VERSION 5.8 ;
BUSBITCHARS "[]" ;
DIVIDERCHAR "/" ;
UNITS
    DATABASE MICRONS 1000 ;
END UNITS

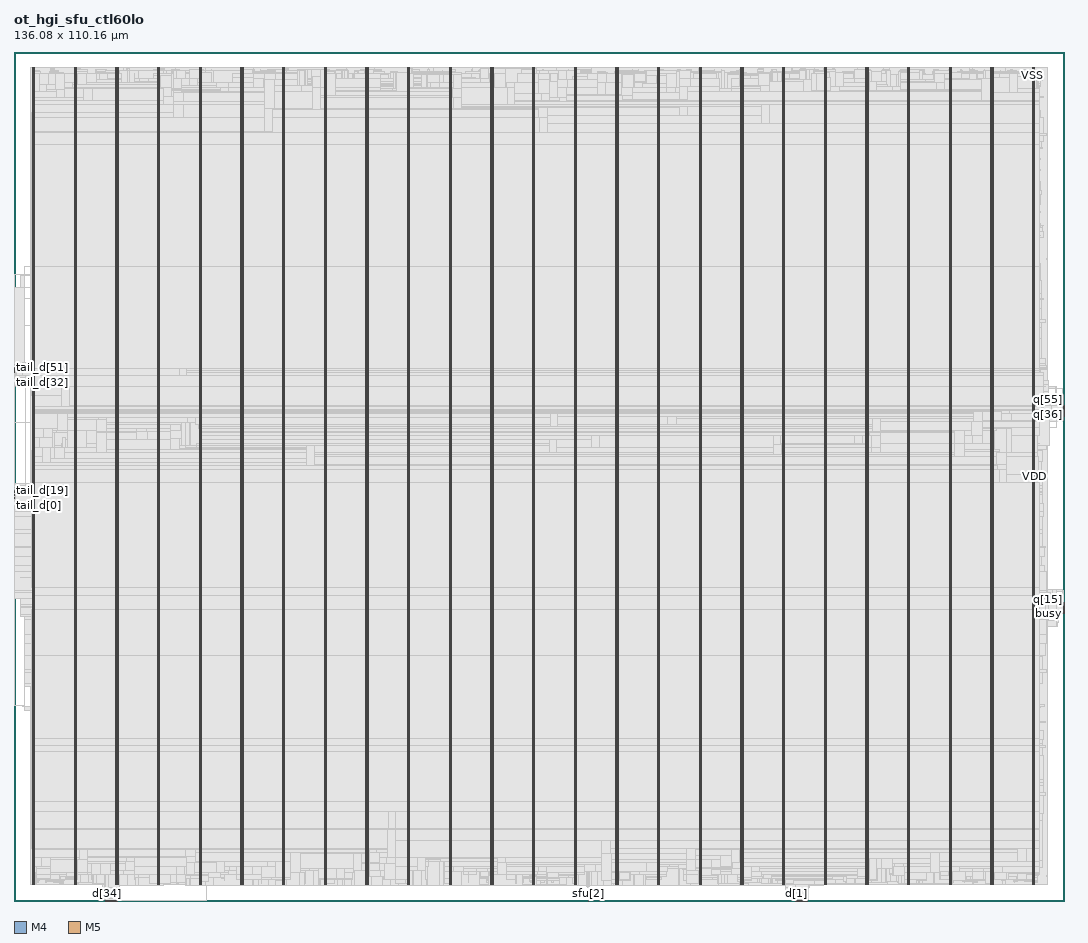
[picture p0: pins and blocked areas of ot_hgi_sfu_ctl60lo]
MACRO ot_hgi_sfu_ctl60lo
  FOREIGN ot_hgi_sfu_ctl60lo 0 0 ;
  CLASS BLOCK ;
  SIZE 136.08 BY 110.16 ;
  PIN busy
    DIRECTION OUTPUT ;
    USE SIGNAL ;
    PORT
      LAYER M4 ;
        RECT  135.996 37.2 136.08 37.224 ;
    END
  END busy
  PIN clk
    DIRECTION INPUT ;
    USE SIGNAL ;
    PORT
      LAYER M5 ;
        RECT  101.328 0 101.352 0.084 ;
    END
  END clk
  PIN coll
    DIRECTION OUTPUT ;
    USE SIGNAL ;
    PORT
      LAYER M4 ;
        RECT  135.996 37.248 136.08 37.272 ;
    END
  END coll
  PIN d[0]
    DIRECTION INPUT ;
    USE SIGNAL ;
    PORT
      LAYER M5 ;
        RECT  101.376 0 101.4 0.084 ;
    END
  END d[0]
  PIN d[10]
    DIRECTION INPUT ;
    USE SIGNAL ;
    PORT
      LAYER M5 ;
        RECT  101.856 0 101.88 0.084 ;
    END
  END d[10]
  PIN d[11]
    DIRECTION INPUT ;
    USE SIGNAL ;
    PORT
      LAYER M5 ;
        RECT  101.904 0 101.928 0.084 ;
    END
  END d[11]
  PIN d[12]
    DIRECTION INPUT ;
    USE SIGNAL ;
    PORT
      LAYER M5 ;
        RECT  101.952 0 101.976 0.084 ;
    END
  END d[12]
  PIN d[13]
    DIRECTION INPUT ;
    USE SIGNAL ;
    PORT
      LAYER M5 ;
        RECT  102 0 102.024 0.084 ;
    END
  END d[13]
  PIN d[14]
    DIRECTION INPUT ;
    USE SIGNAL ;
    PORT
      LAYER M5 ;
        RECT  102.048 0 102.072 0.084 ;
    END
  END d[14]
  PIN d[15]
    DIRECTION INPUT ;
    USE SIGNAL ;
    PORT
      LAYER M5 ;
        RECT  102.096 0 102.12 0.084 ;
    END
  END d[15]
  PIN d[16]
    DIRECTION INPUT ;
    USE SIGNAL ;
    PORT
      LAYER M5 ;
        RECT  102.144 0 102.168 0.084 ;
    END
  END d[16]
  PIN d[17]
    DIRECTION INPUT ;
    USE SIGNAL ;
    PORT
      LAYER M5 ;
        RECT  102.192 0 102.216 0.084 ;
    END
  END d[17]
  PIN d[18]
    DIRECTION INPUT ;
    USE SIGNAL ;
    PORT
      LAYER M5 ;
        RECT  102.24 0 102.264 0.084 ;
    END
  END d[18]
  PIN d[19]
    DIRECTION INPUT ;
    USE SIGNAL ;
    PORT
      LAYER M5 ;
        RECT  102.288 0 102.312 0.084 ;
    END
  END d[19]
  PIN d[1]
    DIRECTION INPUT ;
    USE SIGNAL ;
    PORT
      LAYER M5 ;
        RECT  101.424 0 101.448 0.084 ;
    END
  END d[1]
  PIN d[20]
    DIRECTION INPUT ;
    USE SIGNAL ;
    PORT
      LAYER M5 ;
        RECT  102.336 0 102.36 0.084 ;
    END
  END d[20]
  PIN d[21]
    DIRECTION INPUT ;
    USE SIGNAL ;
    PORT
      LAYER M5 ;
        RECT  102.384 0 102.408 0.084 ;
    END
  END d[21]
  PIN d[22]
    DIRECTION INPUT ;
    USE SIGNAL ;
    PORT
      LAYER M5 ;
        RECT  102.432 0 102.456 0.084 ;
    END
  END d[22]
  PIN d[23]
    DIRECTION INPUT ;
    USE SIGNAL ;
    PORT
      LAYER M5 ;
        RECT  102.48 0 102.504 0.084 ;
    END
  END d[23]
  PIN d[24]
    DIRECTION INPUT ;
    USE SIGNAL ;
    PORT
      LAYER M5 ;
        RECT  102.528 0 102.552 0.084 ;
    END
  END d[24]
  PIN d[25]
    DIRECTION INPUT ;
    USE SIGNAL ;
    PORT
      LAYER M5 ;
        RECT  102.576 0 102.6 0.084 ;
    END
  END d[25]
  PIN d[26]
    DIRECTION INPUT ;
    USE SIGNAL ;
    PORT
      LAYER M5 ;
        RECT  102.624 0 102.648 0.084 ;
    END
  END d[26]
  PIN d[27]
    DIRECTION INPUT ;
    USE SIGNAL ;
    PORT
      LAYER M5 ;
        RECT  102.672 0 102.696 0.084 ;
    END
  END d[27]
  PIN d[28]
    DIRECTION INPUT ;
    USE SIGNAL ;
    PORT
      LAYER M5 ;
        RECT  102.72 0 102.744 0.084 ;
    END
  END d[28]
  PIN d[29]
    DIRECTION INPUT ;
    USE SIGNAL ;
    PORT
      LAYER M5 ;
        RECT  102.768 0 102.792 0.084 ;
    END
  END d[29]
  PIN d[2]
    DIRECTION INPUT ;
    USE SIGNAL ;
    PORT
      LAYER M5 ;
        RECT  101.472 0 101.496 0.084 ;
    END
  END d[2]
  PIN d[30]
    DIRECTION INPUT ;
    USE SIGNAL ;
    PORT
      LAYER M5 ;
        RECT  102.816 0 102.84 0.084 ;
    END
  END d[30]
  PIN d[31]
    DIRECTION INPUT ;
    USE SIGNAL ;
    PORT
      LAYER M5 ;
        RECT  11.856 0 11.88 0.084 ;
    END
  END d[31]
  PIN d[32]
    DIRECTION INPUT ;
    USE SIGNAL ;
    PORT
      LAYER M5 ;
        RECT  11.904 0 11.928 0.084 ;
    END
  END d[32]
  PIN d[33]
    DIRECTION INPUT ;
    USE SIGNAL ;
    PORT
      LAYER M5 ;
        RECT  11.952 0 11.976 0.084 ;
    END
  END d[33]
  PIN d[34]
    DIRECTION INPUT ;
    USE SIGNAL ;
    PORT
      LAYER M5 ;
        RECT  12 0 12.024 0.084 ;
    END
  END d[34]
  PIN d[35]
    DIRECTION INPUT ;
    USE SIGNAL ;
    PORT
      LAYER M5 ;
        RECT  12.048 0 12.072 0.084 ;
    END
  END d[35]
  PIN d[36]
    DIRECTION INPUT ;
    USE SIGNAL ;
    PORT
      LAYER M5 ;
        RECT  12.096 0 12.12 0.084 ;
    END
  END d[36]
  PIN d[37]
    DIRECTION INPUT ;
    USE SIGNAL ;
    PORT
      LAYER M5 ;
        RECT  12.144 0 12.168 0.084 ;
    END
  END d[37]
  PIN d[38]
    DIRECTION INPUT ;
    USE SIGNAL ;
    PORT
      LAYER M5 ;
        RECT  12.192 0 12.216 0.084 ;
    END
  END d[38]
  PIN d[39]
    DIRECTION INPUT ;
    USE SIGNAL ;
    PORT
      LAYER M5 ;
        RECT  12.24 0 12.264 0.084 ;
    END
  END d[39]
  PIN d[3]
    DIRECTION INPUT ;
    USE SIGNAL ;
    PORT
      LAYER M5 ;
        RECT  101.52 0 101.544 0.084 ;
    END
  END d[3]
  PIN d[40]
    DIRECTION INPUT ;
    USE SIGNAL ;
    PORT
      LAYER M5 ;
        RECT  12.288 0 12.312 0.084 ;
    END
  END d[40]
  PIN d[41]
    DIRECTION INPUT ;
    USE SIGNAL ;
    PORT
      LAYER M5 ;
        RECT  12.336 0 12.36 0.084 ;
    END
  END d[41]
  PIN d[42]
    DIRECTION INPUT ;
    USE SIGNAL ;
    PORT
      LAYER M5 ;
        RECT  12.384 0 12.408 0.084 ;
    END
  END d[42]
  PIN d[43]
    DIRECTION INPUT ;
    USE SIGNAL ;
    PORT
      LAYER M5 ;
        RECT  12.432 0 12.456 0.084 ;
    END
  END d[43]
  PIN d[44]
    DIRECTION INPUT ;
    USE SIGNAL ;
    PORT
      LAYER M5 ;
        RECT  12.48 0 12.504 0.084 ;
    END
  END d[44]
  PIN d[45]
    DIRECTION INPUT ;
    USE SIGNAL ;
    PORT
      LAYER M5 ;
        RECT  12.528 0 12.552 0.084 ;
    END
  END d[45]
  PIN d[46]
    DIRECTION INPUT ;
    USE SIGNAL ;
    PORT
      LAYER M5 ;
        RECT  12.576 0 12.6 0.084 ;
    END
  END d[46]
  PIN d[47]
    DIRECTION INPUT ;
    USE SIGNAL ;
    PORT
      LAYER M5 ;
        RECT  12.624 0 12.648 0.084 ;
    END
  END d[47]
  PIN d[48]
    DIRECTION INPUT ;
    USE SIGNAL ;
    PORT
      LAYER M5 ;
        RECT  12.672 0 12.696 0.084 ;
    END
  END d[48]
  PIN d[49]
    DIRECTION INPUT ;
    USE SIGNAL ;
    PORT
      LAYER M5 ;
        RECT  12.72 0 12.744 0.084 ;
    END
  END d[49]
  PIN d[4]
    DIRECTION INPUT ;
    USE SIGNAL ;
    PORT
      LAYER M5 ;
        RECT  101.568 0 101.592 0.084 ;
    END
  END d[4]
  PIN d[50]
    DIRECTION INPUT ;
    USE SIGNAL ;
    PORT
      LAYER M5 ;
        RECT  12.768 0 12.792 0.084 ;
    END
  END d[50]
  PIN d[51]
    DIRECTION INPUT ;
    USE SIGNAL ;
    PORT
      LAYER M5 ;
        RECT  12.816 0 12.84 0.084 ;
    END
  END d[51]
  PIN d[52]
    DIRECTION INPUT ;
    USE SIGNAL ;
    PORT
      LAYER M5 ;
        RECT  12.864 0 12.888 0.084 ;
    END
  END d[52]
  PIN d[53]
    DIRECTION INPUT ;
    USE SIGNAL ;
    PORT
      LAYER M5 ;
        RECT  12.912 0 12.936 0.084 ;
    END
  END d[53]
  PIN d[54]
    DIRECTION INPUT ;
    USE SIGNAL ;
    PORT
      LAYER M5 ;
        RECT  12.96 0 12.984 0.084 ;
    END
  END d[54]
  PIN d[55]
    DIRECTION INPUT ;
    USE SIGNAL ;
    PORT
      LAYER M5 ;
        RECT  13.008 0 13.032 0.084 ;
    END
  END d[55]
  PIN d[56]
    DIRECTION INPUT ;
    USE SIGNAL ;
    PORT
      LAYER M5 ;
        RECT  13.056 0 13.08 0.084 ;
    END
  END d[56]
  PIN d[57]
    DIRECTION INPUT ;
    USE SIGNAL ;
    PORT
      LAYER M5 ;
        RECT  13.104 0 13.128 0.084 ;
    END
  END d[57]
  PIN d[58]
    DIRECTION INPUT ;
    USE SIGNAL ;
    PORT
      LAYER M5 ;
        RECT  13.152 0 13.176 0.084 ;
    END
  END d[58]
  PIN d[59]
    DIRECTION INPUT ;
    USE SIGNAL ;
    PORT
      LAYER M5 ;
        RECT  13.2 0 13.224 0.084 ;
    END
  END d[59]
  PIN d[5]
    DIRECTION INPUT ;
    USE SIGNAL ;
    PORT
      LAYER M5 ;
        RECT  101.616 0 101.64 0.084 ;
    END
  END d[5]
  PIN d[6]
    DIRECTION INPUT ;
    USE SIGNAL ;
    PORT
      LAYER M5 ;
        RECT  101.664 0 101.688 0.084 ;
    END
  END d[6]
  PIN d[7]
    DIRECTION INPUT ;
    USE SIGNAL ;
    PORT
      LAYER M5 ;
        RECT  101.712 0 101.736 0.084 ;
    END
  END d[7]
  PIN d[8]
    DIRECTION INPUT ;
    USE SIGNAL ;
    PORT
      LAYER M5 ;
        RECT  101.76 0 101.784 0.084 ;
    END
  END d[8]
  PIN d[9]
    DIRECTION INPUT ;
    USE SIGNAL ;
    PORT
      LAYER M5 ;
        RECT  101.808 0 101.832 0.084 ;
    END
  END d[9]
  PIN q[0]
    DIRECTION OUTPUT ;
    USE SIGNAL ;
    PORT
      LAYER M4 ;
        RECT  135.996 37.296 136.08 37.32 ;
    END
  END q[0]
  PIN q[10]
    DIRECTION OUTPUT ;
    USE SIGNAL ;
    PORT
      LAYER M4 ;
        RECT  135.996 37.776 136.08 37.8 ;
    END
  END q[10]
  PIN q[11]
    DIRECTION OUTPUT ;
    USE SIGNAL ;
    PORT
      LAYER M4 ;
        RECT  135.996 37.824 136.08 37.848 ;
    END
  END q[11]
  PIN q[12]
    DIRECTION OUTPUT ;
    USE SIGNAL ;
    PORT
      LAYER M4 ;
        RECT  135.996 37.872 136.08 37.896 ;
    END
  END q[12]
  PIN q[13]
    DIRECTION OUTPUT ;
    USE SIGNAL ;
    PORT
      LAYER M4 ;
        RECT  135.996 37.92 136.08 37.944 ;
    END
  END q[13]
  PIN q[14]
    DIRECTION OUTPUT ;
    USE SIGNAL ;
    PORT
      LAYER M4 ;
        RECT  135.996 37.968 136.08 37.992 ;
    END
  END q[14]
  PIN q[15]
    DIRECTION OUTPUT ;
    USE SIGNAL ;
    PORT
      LAYER M4 ;
        RECT  135.996 38.016 136.08 38.04 ;
    END
  END q[15]
  PIN q[16]
    DIRECTION OUTPUT ;
    USE SIGNAL ;
    PORT
      LAYER M4 ;
        RECT  135.996 38.064 136.08 38.088 ;
    END
  END q[16]
  PIN q[17]
    DIRECTION OUTPUT ;
    USE SIGNAL ;
    PORT
      LAYER M4 ;
        RECT  135.996 38.112 136.08 38.136 ;
    END
  END q[17]
  PIN q[18]
    DIRECTION OUTPUT ;
    USE SIGNAL ;
    PORT
      LAYER M4 ;
        RECT  135.996 38.16 136.08 38.184 ;
    END
  END q[18]
  PIN q[19]
    DIRECTION OUTPUT ;
    USE SIGNAL ;
    PORT
      LAYER M4 ;
        RECT  135.996 38.208 136.08 38.232 ;
    END
  END q[19]
  PIN q[1]
    DIRECTION OUTPUT ;
    USE SIGNAL ;
    PORT
      LAYER M4 ;
        RECT  135.996 37.344 136.08 37.368 ;
    END
  END q[1]
  PIN q[20]
    DIRECTION OUTPUT ;
    USE SIGNAL ;
    PORT
      LAYER M4 ;
        RECT  135.996 38.256 136.08 38.28 ;
    END
  END q[20]
  PIN q[21]
    DIRECTION OUTPUT ;
    USE SIGNAL ;
    PORT
      LAYER M4 ;
        RECT  135.996 38.304 136.08 38.328 ;
    END
  END q[21]
  PIN q[22]
    DIRECTION OUTPUT ;
    USE SIGNAL ;
    PORT
      LAYER M4 ;
        RECT  135.996 38.352 136.08 38.376 ;
    END
  END q[22]
  PIN q[23]
    DIRECTION OUTPUT ;
    USE SIGNAL ;
    PORT
      LAYER M4 ;
        RECT  135.996 38.4 136.08 38.424 ;
    END
  END q[23]
  PIN q[24]
    DIRECTION OUTPUT ;
    USE SIGNAL ;
    PORT
      LAYER M4 ;
        RECT  135.996 38.448 136.08 38.472 ;
    END
  END q[24]
  PIN q[25]
    DIRECTION OUTPUT ;
    USE SIGNAL ;
    PORT
      LAYER M4 ;
        RECT  135.996 38.496 136.08 38.52 ;
    END
  END q[25]
  PIN q[26]
    DIRECTION OUTPUT ;
    USE SIGNAL ;
    PORT
      LAYER M4 ;
        RECT  135.996 38.544 136.08 38.568 ;
    END
  END q[26]
  PIN q[27]
    DIRECTION OUTPUT ;
    USE SIGNAL ;
    PORT
      LAYER M4 ;
        RECT  135.996 38.592 136.08 38.616 ;
    END
  END q[27]
  PIN q[28]
    DIRECTION OUTPUT ;
    USE SIGNAL ;
    PORT
      LAYER M4 ;
        RECT  135.996 38.64 136.08 38.664 ;
    END
  END q[28]
  PIN q[29]
    DIRECTION OUTPUT ;
    USE SIGNAL ;
    PORT
      LAYER M4 ;
        RECT  135.996 38.688 136.08 38.712 ;
    END
  END q[29]
  PIN q[2]
    DIRECTION OUTPUT ;
    USE SIGNAL ;
    PORT
      LAYER M4 ;
        RECT  135.996 37.392 136.08 37.416 ;
    END
  END q[2]
  PIN q[30]
    DIRECTION OUTPUT ;
    USE SIGNAL ;
    PORT
      LAYER M4 ;
        RECT  135.996 62.784 136.08 62.808 ;
    END
  END q[30]
  PIN q[31]
    DIRECTION OUTPUT ;
    USE SIGNAL ;
    PORT
      LAYER M4 ;
        RECT  135.996 62.832 136.08 62.856 ;
    END
  END q[31]
  PIN q[32]
    DIRECTION OUTPUT ;
    USE SIGNAL ;
    PORT
      LAYER M4 ;
        RECT  135.996 62.88 136.08 62.904 ;
    END
  END q[32]
  PIN q[33]
    DIRECTION OUTPUT ;
    USE SIGNAL ;
    PORT
      LAYER M4 ;
        RECT  135.996 62.928 136.08 62.952 ;
    END
  END q[33]
  PIN q[34]
    DIRECTION OUTPUT ;
    USE SIGNAL ;
    PORT
      LAYER M4 ;
        RECT  135.996 62.976 136.08 63 ;
    END
  END q[34]
  PIN q[35]
    DIRECTION OUTPUT ;
    USE SIGNAL ;
    PORT
      LAYER M4 ;
        RECT  135.996 63.024 136.08 63.048 ;
    END
  END q[35]
  PIN q[36]
    DIRECTION OUTPUT ;
    USE SIGNAL ;
    PORT
      LAYER M4 ;
        RECT  135.996 63.072 136.08 63.096 ;
    END
  END q[36]
  PIN q[37]
    DIRECTION OUTPUT ;
    USE SIGNAL ;
    PORT
      LAYER M4 ;
        RECT  135.996 63.12 136.08 63.144 ;
    END
  END q[37]
  PIN q[38]
    DIRECTION OUTPUT ;
    USE SIGNAL ;
    PORT
      LAYER M4 ;
        RECT  135.996 63.168 136.08 63.192 ;
    END
  END q[38]
  PIN q[39]
    DIRECTION OUTPUT ;
    USE SIGNAL ;
    PORT
      LAYER M4 ;
        RECT  135.996 63.216 136.08 63.24 ;
    END
  END q[39]
  PIN q[3]
    DIRECTION OUTPUT ;
    USE SIGNAL ;
    PORT
      LAYER M4 ;
        RECT  135.996 37.44 136.08 37.464 ;
    END
  END q[3]
  PIN q[40]
    DIRECTION OUTPUT ;
    USE SIGNAL ;
    PORT
      LAYER M4 ;
        RECT  135.996 63.264 136.08 63.288 ;
    END
  END q[40]
  PIN q[41]
    DIRECTION OUTPUT ;
    USE SIGNAL ;
    PORT
      LAYER M4 ;
        RECT  135.996 63.312 136.08 63.336 ;
    END
  END q[41]
  PIN q[42]
    DIRECTION OUTPUT ;
    USE SIGNAL ;
    PORT
      LAYER M4 ;
        RECT  135.996 63.36 136.08 63.384 ;
    END
  END q[42]
  PIN q[43]
    DIRECTION OUTPUT ;
    USE SIGNAL ;
    PORT
      LAYER M4 ;
        RECT  135.996 63.408 136.08 63.432 ;
    END
  END q[43]
  PIN q[44]
    DIRECTION OUTPUT ;
    USE SIGNAL ;
    PORT
      LAYER M4 ;
        RECT  135.996 63.456 136.08 63.48 ;
    END
  END q[44]
  PIN q[45]
    DIRECTION OUTPUT ;
    USE SIGNAL ;
    PORT
      LAYER M4 ;
        RECT  135.996 63.504 136.08 63.528 ;
    END
  END q[45]
  PIN q[46]
    DIRECTION OUTPUT ;
    USE SIGNAL ;
    PORT
      LAYER M4 ;
        RECT  135.996 63.552 136.08 63.576 ;
    END
  END q[46]
  PIN q[47]
    DIRECTION OUTPUT ;
    USE SIGNAL ;
    PORT
      LAYER M4 ;
        RECT  135.996 63.6 136.08 63.624 ;
    END
  END q[47]
  PIN q[48]
    DIRECTION OUTPUT ;
    USE SIGNAL ;
    PORT
      LAYER M4 ;
        RECT  135.996 63.648 136.08 63.672 ;
    END
  END q[48]
  PIN q[49]
    DIRECTION OUTPUT ;
    USE SIGNAL ;
    PORT
      LAYER M4 ;
        RECT  135.996 63.696 136.08 63.72 ;
    END
  END q[49]
  PIN q[4]
    DIRECTION OUTPUT ;
    USE SIGNAL ;
    PORT
      LAYER M4 ;
        RECT  135.996 37.488 136.08 37.512 ;
    END
  END q[4]
  PIN q[50]
    DIRECTION OUTPUT ;
    USE SIGNAL ;
    PORT
      LAYER M4 ;
        RECT  135.996 63.744 136.08 63.768 ;
    END
  END q[50]
  PIN q[51]
    DIRECTION OUTPUT ;
    USE SIGNAL ;
    PORT
      LAYER M4 ;
        RECT  135.996 63.792 136.08 63.816 ;
    END
  END q[51]
  PIN q[52]
    DIRECTION OUTPUT ;
    USE SIGNAL ;
    PORT
      LAYER M4 ;
        RECT  135.996 63.84 136.08 63.864 ;
    END
  END q[52]
  PIN q[53]
    DIRECTION OUTPUT ;
    USE SIGNAL ;
    PORT
      LAYER M4 ;
        RECT  135.996 63.888 136.08 63.912 ;
    END
  END q[53]
  PIN q[54]
    DIRECTION OUTPUT ;
    USE SIGNAL ;
    PORT
      LAYER M4 ;
        RECT  135.996 63.936 136.08 63.96 ;
    END
  END q[54]
  PIN q[55]
    DIRECTION OUTPUT ;
    USE SIGNAL ;
    PORT
      LAYER M4 ;
        RECT  135.996 63.984 136.08 64.008 ;
    END
  END q[55]
  PIN q[56]
    DIRECTION OUTPUT ;
    USE SIGNAL ;
    PORT
      LAYER M4 ;
        RECT  135.996 64.032 136.08 64.056 ;
    END
  END q[56]
  PIN q[57]
    DIRECTION OUTPUT ;
    USE SIGNAL ;
    PORT
      LAYER M4 ;
        RECT  135.996 64.08 136.08 64.104 ;
    END
  END q[57]
  PIN q[58]
    DIRECTION OUTPUT ;
    USE SIGNAL ;
    PORT
      LAYER M4 ;
        RECT  135.996 64.128 136.08 64.152 ;
    END
  END q[58]
  PIN q[59]
    DIRECTION OUTPUT ;
    USE SIGNAL ;
    PORT
      LAYER M4 ;
        RECT  135.996 64.176 136.08 64.2 ;
    END
  END q[59]
  PIN q[5]
    DIRECTION OUTPUT ;
    USE SIGNAL ;
    PORT
      LAYER M4 ;
        RECT  135.996 37.536 136.08 37.56 ;
    END
  END q[5]
  PIN q[6]
    DIRECTION OUTPUT ;
    USE SIGNAL ;
    PORT
      LAYER M4 ;
        RECT  135.996 37.584 136.08 37.608 ;
    END
  END q[6]
  PIN q[7]
    DIRECTION OUTPUT ;
    USE SIGNAL ;
    PORT
      LAYER M4 ;
        RECT  135.996 37.632 136.08 37.656 ;
    END
  END q[7]
  PIN q[8]
    DIRECTION OUTPUT ;
    USE SIGNAL ;
    PORT
      LAYER M4 ;
        RECT  135.996 37.68 136.08 37.704 ;
    END
  END q[8]
  PIN q[9]
    DIRECTION OUTPUT ;
    USE SIGNAL ;
    PORT
      LAYER M4 ;
        RECT  135.996 37.728 136.08 37.752 ;
    END
  END q[9]
  PIN rst_n
    DIRECTION INPUT ;
    USE SIGNAL ;
    PORT
      LAYER M5 ;
        RECT  13.248 0 13.272 0.084 ;
    END
  END rst_n
  PIN sfu[0]
    DIRECTION INPUT ;
    USE SIGNAL ;
    PORT
      LAYER M5 ;
        RECT  13.296 0 13.32 0.084 ;
    END
  END sfu[0]
  PIN sfu[1]
    DIRECTION INPUT ;
    USE SIGNAL ;
    PORT
      LAYER M5 ;
        RECT  13.344 0 13.368 0.084 ;
    END
  END sfu[1]
  PIN sfu[2]
    DIRECTION INPUT ;
    USE SIGNAL ;
    PORT
      LAYER M5 ;
        RECT  74.448 0 74.472 0.084 ;
    END
  END sfu[2]
  PIN tail_d[0]
    DIRECTION INPUT ;
    USE SIGNAL ;
    PORT
      LAYER M4 ;
        RECT  0 52.224 0.084 52.248 ;
    END
  END tail_d[0]
  PIN tail_d[10]
    DIRECTION INPUT ;
    USE SIGNAL ;
    PORT
      LAYER M4 ;
        RECT  0 52.704 0.084 52.728 ;
    END
  END tail_d[10]
  PIN tail_d[11]
    DIRECTION INPUT ;
    USE SIGNAL ;
    PORT
      LAYER M4 ;
        RECT  0 52.752 0.084 52.776 ;
    END
  END tail_d[11]
  PIN tail_d[12]
    DIRECTION INPUT ;
    USE SIGNAL ;
    PORT
      LAYER M4 ;
        RECT  0 52.8 0.084 52.824 ;
    END
  END tail_d[12]
  PIN tail_d[13]
    DIRECTION INPUT ;
    USE SIGNAL ;
    PORT
      LAYER M4 ;
        RECT  0 52.848 0.084 52.872 ;
    END
  END tail_d[13]
  PIN tail_d[14]
    DIRECTION INPUT ;
    USE SIGNAL ;
    PORT
      LAYER M4 ;
        RECT  0 52.896 0.084 52.92 ;
    END
  END tail_d[14]
  PIN tail_d[15]
    DIRECTION INPUT ;
    USE SIGNAL ;
    PORT
      LAYER M4 ;
        RECT  0 52.944 0.084 52.968 ;
    END
  END tail_d[15]
  PIN tail_d[16]
    DIRECTION INPUT ;
    USE SIGNAL ;
    PORT
      LAYER M4 ;
        RECT  0 52.992 0.084 53.016 ;
    END
  END tail_d[16]
  PIN tail_d[17]
    DIRECTION INPUT ;
    USE SIGNAL ;
    PORT
      LAYER M4 ;
        RECT  0 53.04 0.084 53.064 ;
    END
  END tail_d[17]
  PIN tail_d[18]
    DIRECTION INPUT ;
    USE SIGNAL ;
    PORT
      LAYER M4 ;
        RECT  0 53.088 0.084 53.112 ;
    END
  END tail_d[18]
  PIN tail_d[19]
    DIRECTION INPUT ;
    USE SIGNAL ;
    PORT
      LAYER M4 ;
        RECT  0 53.136 0.084 53.16 ;
    END
  END tail_d[19]
  PIN tail_d[1]
    DIRECTION INPUT ;
    USE SIGNAL ;
    PORT
      LAYER M4 ;
        RECT  0 52.272 0.084 52.296 ;
    END
  END tail_d[1]
  PIN tail_d[20]
    DIRECTION INPUT ;
    USE SIGNAL ;
    PORT
      LAYER M4 ;
        RECT  0 53.184 0.084 53.208 ;
    END
  END tail_d[20]
  PIN tail_d[21]
    DIRECTION INPUT ;
    USE SIGNAL ;
    PORT
      LAYER M4 ;
        RECT  0 53.232 0.084 53.256 ;
    END
  END tail_d[21]
  PIN tail_d[22]
    DIRECTION INPUT ;
    USE SIGNAL ;
    PORT
      LAYER M4 ;
        RECT  0 53.28 0.084 53.304 ;
    END
  END tail_d[22]
  PIN tail_d[23]
    DIRECTION INPUT ;
    USE SIGNAL ;
    PORT
      LAYER M4 ;
        RECT  0 53.328 0.084 53.352 ;
    END
  END tail_d[23]
  PIN tail_d[24]
    DIRECTION INPUT ;
    USE SIGNAL ;
    PORT
      LAYER M4 ;
        RECT  0 53.376 0.084 53.4 ;
    END
  END tail_d[24]
  PIN tail_d[25]
    DIRECTION INPUT ;
    USE SIGNAL ;
    PORT
      LAYER M4 ;
        RECT  0 53.424 0.084 53.448 ;
    END
  END tail_d[25]
  PIN tail_d[26]
    DIRECTION INPUT ;
    USE SIGNAL ;
    PORT
      LAYER M4 ;
        RECT  0 53.472 0.084 53.496 ;
    END
  END tail_d[26]
  PIN tail_d[27]
    DIRECTION INPUT ;
    USE SIGNAL ;
    PORT
      LAYER M4 ;
        RECT  0 53.52 0.084 53.544 ;
    END
  END tail_d[27]
  PIN tail_d[28]
    DIRECTION INPUT ;
    USE SIGNAL ;
    PORT
      LAYER M4 ;
        RECT  0 53.568 0.084 53.592 ;
    END
  END tail_d[28]
  PIN tail_d[29]
    DIRECTION INPUT ;
    USE SIGNAL ;
    PORT
      LAYER M4 ;
        RECT  0 53.616 0.084 53.64 ;
    END
  END tail_d[29]
  PIN tail_d[2]
    DIRECTION INPUT ;
    USE SIGNAL ;
    PORT
      LAYER M4 ;
        RECT  0 52.32 0.084 52.344 ;
    END
  END tail_d[2]
  PIN tail_d[30]
    DIRECTION INPUT ;
    USE SIGNAL ;
    PORT
      LAYER M4 ;
        RECT  0 53.664 0.084 53.688 ;
    END
  END tail_d[30]
  PIN tail_d[31]
    DIRECTION INPUT ;
    USE SIGNAL ;
    PORT
      LAYER M4 ;
        RECT  0 53.712 0.084 53.736 ;
    END
  END tail_d[31]
  PIN tail_d[32]
    DIRECTION INPUT ;
    USE SIGNAL ;
    PORT
      LAYER M4 ;
        RECT  0 68.256 0.084 68.28 ;
    END
  END tail_d[32]
  PIN tail_d[33]
    DIRECTION INPUT ;
    USE SIGNAL ;
    PORT
      LAYER M4 ;
        RECT  0 68.304 0.084 68.328 ;
    END
  END tail_d[33]
  PIN tail_d[34]
    DIRECTION INPUT ;
    USE SIGNAL ;
    PORT
      LAYER M4 ;
        RECT  0 68.352 0.084 68.376 ;
    END
  END tail_d[34]
  PIN tail_d[35]
    DIRECTION INPUT ;
    USE SIGNAL ;
    PORT
      LAYER M4 ;
        RECT  0 68.4 0.084 68.424 ;
    END
  END tail_d[35]
  PIN tail_d[36]
    DIRECTION INPUT ;
    USE SIGNAL ;
    PORT
      LAYER M4 ;
        RECT  0 68.448 0.084 68.472 ;
    END
  END tail_d[36]
  PIN tail_d[37]
    DIRECTION INPUT ;
    USE SIGNAL ;
    PORT
      LAYER M4 ;
        RECT  0 68.496 0.084 68.52 ;
    END
  END tail_d[37]
  PIN tail_d[38]
    DIRECTION INPUT ;
    USE SIGNAL ;
    PORT
      LAYER M4 ;
        RECT  0 68.544 0.084 68.568 ;
    END
  END tail_d[38]
  PIN tail_d[39]
    DIRECTION INPUT ;
    USE SIGNAL ;
    PORT
      LAYER M4 ;
        RECT  0 68.592 0.084 68.616 ;
    END
  END tail_d[39]
  PIN tail_d[3]
    DIRECTION INPUT ;
    USE SIGNAL ;
    PORT
      LAYER M4 ;
        RECT  0 52.368 0.084 52.392 ;
    END
  END tail_d[3]
  PIN tail_d[40]
    DIRECTION INPUT ;
    USE SIGNAL ;
    PORT
      LAYER M4 ;
        RECT  0 68.64 0.084 68.664 ;
    END
  END tail_d[40]
  PIN tail_d[41]
    DIRECTION INPUT ;
    USE SIGNAL ;
    PORT
      LAYER M4 ;
        RECT  0 68.688 0.084 68.712 ;
    END
  END tail_d[41]
  PIN tail_d[42]
    DIRECTION INPUT ;
    USE SIGNAL ;
    PORT
      LAYER M4 ;
        RECT  0 68.736 0.084 68.76 ;
    END
  END tail_d[42]
  PIN tail_d[43]
    DIRECTION INPUT ;
    USE SIGNAL ;
    PORT
      LAYER M4 ;
        RECT  0 68.784 0.084 68.808 ;
    END
  END tail_d[43]
  PIN tail_d[44]
    DIRECTION INPUT ;
    USE SIGNAL ;
    PORT
      LAYER M4 ;
        RECT  0 68.832 0.084 68.856 ;
    END
  END tail_d[44]
  PIN tail_d[45]
    DIRECTION INPUT ;
    USE SIGNAL ;
    PORT
      LAYER M4 ;
        RECT  0 68.88 0.084 68.904 ;
    END
  END tail_d[45]
  PIN tail_d[46]
    DIRECTION INPUT ;
    USE SIGNAL ;
    PORT
      LAYER M4 ;
        RECT  0 68.928 0.084 68.952 ;
    END
  END tail_d[46]
  PIN tail_d[47]
    DIRECTION INPUT ;
    USE SIGNAL ;
    PORT
      LAYER M4 ;
        RECT  0 68.976 0.084 69 ;
    END
  END tail_d[47]
  PIN tail_d[48]
    DIRECTION INPUT ;
    USE SIGNAL ;
    PORT
      LAYER M4 ;
        RECT  0 69.024 0.084 69.048 ;
    END
  END tail_d[48]
  PIN tail_d[49]
    DIRECTION INPUT ;
    USE SIGNAL ;
    PORT
      LAYER M4 ;
        RECT  0 69.072 0.084 69.096 ;
    END
  END tail_d[49]
  PIN tail_d[4]
    DIRECTION INPUT ;
    USE SIGNAL ;
    PORT
      LAYER M4 ;
        RECT  0 52.416 0.084 52.44 ;
    END
  END tail_d[4]
  PIN tail_d[50]
    DIRECTION INPUT ;
    USE SIGNAL ;
    PORT
      LAYER M4 ;
        RECT  0 69.12 0.084 69.144 ;
    END
  END tail_d[50]
  PIN tail_d[51]
    DIRECTION INPUT ;
    USE SIGNAL ;
    PORT
      LAYER M4 ;
        RECT  0 69.168 0.084 69.192 ;
    END
  END tail_d[51]
  PIN tail_d[52]
    DIRECTION INPUT ;
    USE SIGNAL ;
    PORT
      LAYER M4 ;
        RECT  0 69.216 0.084 69.24 ;
    END
  END tail_d[52]
  PIN tail_d[53]
    DIRECTION INPUT ;
    USE SIGNAL ;
    PORT
      LAYER M4 ;
        RECT  0 69.264 0.084 69.288 ;
    END
  END tail_d[53]
  PIN tail_d[54]
    DIRECTION INPUT ;
    USE SIGNAL ;
    PORT
      LAYER M4 ;
        RECT  0 69.312 0.084 69.336 ;
    END
  END tail_d[54]
  PIN tail_d[55]
    DIRECTION INPUT ;
    USE SIGNAL ;
    PORT
      LAYER M4 ;
        RECT  0 69.36 0.084 69.384 ;
    END
  END tail_d[55]
  PIN tail_d[56]
    DIRECTION INPUT ;
    USE SIGNAL ;
    PORT
      LAYER M4 ;
        RECT  0 69.408 0.084 69.432 ;
    END
  END tail_d[56]
  PIN tail_d[57]
    DIRECTION INPUT ;
    USE SIGNAL ;
    PORT
      LAYER M4 ;
        RECT  0 69.456 0.084 69.48 ;
    END
  END tail_d[57]
  PIN tail_d[58]
    DIRECTION INPUT ;
    USE SIGNAL ;
    PORT
      LAYER M4 ;
        RECT  0 69.504 0.084 69.528 ;
    END
  END tail_d[58]
  PIN tail_d[59]
    DIRECTION INPUT ;
    USE SIGNAL ;
    PORT
      LAYER M4 ;
        RECT  0 69.552 0.084 69.576 ;
    END
  END tail_d[59]
  PIN tail_d[5]
    DIRECTION INPUT ;
    USE SIGNAL ;
    PORT
      LAYER M4 ;
        RECT  0 52.464 0.084 52.488 ;
    END
  END tail_d[5]
  PIN tail_d[6]
    DIRECTION INPUT ;
    USE SIGNAL ;
    PORT
      LAYER M4 ;
        RECT  0 52.512 0.084 52.536 ;
    END
  END tail_d[6]
  PIN tail_d[7]
    DIRECTION INPUT ;
    USE SIGNAL ;
    PORT
      LAYER M4 ;
        RECT  0 52.56 0.084 52.584 ;
    END
  END tail_d[7]
  PIN tail_d[8]
    DIRECTION INPUT ;
    USE SIGNAL ;
    PORT
      LAYER M4 ;
        RECT  0 52.608 0.084 52.632 ;
    END
  END tail_d[8]
  PIN tail_d[9]
    DIRECTION INPUT ;
    USE SIGNAL ;
    PORT
      LAYER M4 ;
        RECT  0 52.656 0.084 52.68 ;
    END
  END tail_d[9]
  PIN tail_v
    DIRECTION INPUT ;
    USE SIGNAL ;
    PORT
      LAYER M4 ;
        RECT  0 69.6 0.084 69.624 ;
    END
  END tail_v
  PIN v
    DIRECTION INPUT ;
    USE SIGNAL ;
    PORT
      LAYER M5 ;
        RECT  74.496 0 74.52 0.084 ;
    END
  END v
  PIN vo
    DIRECTION OUTPUT ;
    USE SIGNAL ;
    PORT
      LAYER M4 ;
        RECT  135.996 64.224 136.08 64.248 ;
    END
  END vo
  PIN VDD
    DIRECTION INOUT ;
    USE POWER ;
    PORT
      LAYER M5 ;
        RECT  132.192 2.151 132.312 108.009 ;
        RECT  126.792 2.151 126.912 108.009 ;
        RECT  121.392 2.151 121.512 108.009 ;
        RECT  115.992 2.151 116.112 108.009 ;
        RECT  110.592 2.151 110.712 108.009 ;
        RECT  105.192 2.151 105.312 108.009 ;
        RECT  99.792 2.151 99.912 108.009 ;
        RECT  94.392 2.151 94.512 108.009 ;
        RECT  88.992 2.151 89.112 108.009 ;
        RECT  83.592 2.151 83.712 108.009 ;
        RECT  78.192 2.151 78.312 108.009 ;
        RECT  72.792 2.151 72.912 108.009 ;
        RECT  67.392 2.151 67.512 108.009 ;
        RECT  61.992 2.151 62.112 108.009 ;
        RECT  56.592 2.151 56.712 108.009 ;
        RECT  51.192 2.151 51.312 108.009 ;
        RECT  45.792 2.151 45.912 108.009 ;
        RECT  40.392 2.151 40.512 108.009 ;
        RECT  34.992 2.151 35.112 108.009 ;
        RECT  29.592 2.151 29.712 108.009 ;
        RECT  24.192 2.151 24.312 108.009 ;
        RECT  18.792 2.151 18.912 108.009 ;
        RECT  13.392 2.151 13.512 108.009 ;
        RECT  7.992 2.151 8.112 108.009 ;
        RECT  2.592 2.151 2.712 108.009 ;
    END
  END VDD
  PIN VSS
    DIRECTION INOUT ;
    USE GROUND ;
    PORT
      LAYER M5 ;
        RECT  132 2.137 132.12 108.023 ;
        RECT  126.6 2.137 126.72 108.023 ;
        RECT  121.2 2.137 121.32 108.023 ;
        RECT  115.8 2.137 115.92 108.023 ;
        RECT  110.4 2.137 110.52 108.023 ;
        RECT  105 2.137 105.12 108.023 ;
        RECT  99.6 2.137 99.72 108.023 ;
        RECT  94.2 2.137 94.32 108.023 ;
        RECT  88.8 2.137 88.92 108.023 ;
        RECT  83.4 2.137 83.52 108.023 ;
        RECT  78 2.137 78.12 108.023 ;
        RECT  72.6 2.137 72.72 108.023 ;
        RECT  67.2 2.137 67.32 108.023 ;
        RECT  61.8 2.137 61.92 108.023 ;
        RECT  56.4 2.137 56.52 108.023 ;
        RECT  51 2.137 51.12 108.023 ;
        RECT  45.6 2.137 45.72 108.023 ;
        RECT  40.2 2.137 40.32 108.023 ;
        RECT  34.8 2.137 34.92 108.023 ;
        RECT  29.4 2.137 29.52 108.023 ;
        RECT  24 2.137 24.12 108.023 ;
        RECT  18.6 2.137 18.72 108.023 ;
        RECT  13.2 2.137 13.32 108.023 ;
        RECT  7.8 2.137 7.92 108.023 ;
        RECT  2.4 2.137 2.52 108.023 ;
    END
  END VSS
  # OT_OBS_CLOSED layer=M5 d_um=1.536 added=273
  OBS
    LAYER RVTN ;
     RECT  2.16 2.16 133.92 2.295 ;
     RECT  2.16 2.565 133.92 2.835 ;
     RECT  2.16 3.105 133.92 3.375 ;
     RECT  2.16 3.645 133.92 3.915 ;
     RECT  2.16 4.185 133.92 4.455 ;
     RECT  2.16 4.725 133.92 4.995 ;
     RECT  2.16 5.265 133.92 5.535 ;
     RECT  2.16 5.805 133.92 6.075 ;
     RECT  2.16 6.345 133.92 6.615 ;
     RECT  2.16 6.885 133.92 7.155 ;
     RECT  2.16 7.425 133.92 7.695 ;
     RECT  2.16 7.965 133.92 8.235 ;
     RECT  2.16 8.505 133.92 8.775 ;
     RECT  2.16 9.045 133.92 9.315 ;
     RECT  2.16 9.585 133.92 9.855 ;
     RECT  2.16 10.125 133.92 10.395 ;
     RECT  2.16 10.665 133.92 10.935 ;
     RECT  2.16 11.205 133.92 11.475 ;
     RECT  2.16 11.745 133.92 12.015 ;
     RECT  2.16 12.285 133.92 12.555 ;
     RECT  2.16 12.825 133.92 13.095 ;
     RECT  2.16 13.365 133.92 13.635 ;
     RECT  2.16 13.905 133.92 14.175 ;
     RECT  2.16 14.445 133.92 14.715 ;
     RECT  2.16 14.985 133.92 15.255 ;
     RECT  2.16 15.525 133.92 15.795 ;
     RECT  2.16 16.065 133.92 16.335 ;
     RECT  2.16 16.605 133.92 16.875 ;
     RECT  2.16 17.145 133.92 17.415 ;
     RECT  2.16 17.685 133.92 17.955 ;
     RECT  2.16 18.225 133.92 18.495 ;
     RECT  2.16 18.765 133.92 19.035 ;
     RECT  2.16 19.305 133.92 19.575 ;
     RECT  2.16 19.845 133.92 20.115 ;
     RECT  2.16 20.385 133.92 20.655 ;
     RECT  2.16 20.925 133.92 21.195 ;
     RECT  2.16 21.465 133.92 21.735 ;
     RECT  2.16 22.005 133.92 22.275 ;
     RECT  2.16 22.545 133.92 22.815 ;
     RECT  2.16 23.085 133.92 23.355 ;
     RECT  2.16 23.625 133.92 23.895 ;
     RECT  2.16 24.165 133.92 24.435 ;
     RECT  2.16 24.705 133.92 24.975 ;
     RECT  2.16 25.245 133.92 25.515 ;
     RECT  2.16 25.785 133.92 26.055 ;
     RECT  2.16 26.325 133.92 26.595 ;
     RECT  2.16 26.865 133.92 27.135 ;
     RECT  2.16 27.405 133.92 27.675 ;
     RECT  2.16 27.945 133.92 28.215 ;
     RECT  2.16 28.485 133.92 28.755 ;
     RECT  2.16 29.025 133.92 29.295 ;
     RECT  2.16 29.565 133.92 29.835 ;
     RECT  2.16 30.105 133.92 30.375 ;
     RECT  2.16 30.645 133.92 30.915 ;
     RECT  2.16 31.185 133.92 31.455 ;
     RECT  2.16 31.725 133.92 31.995 ;
     RECT  2.16 32.265 133.92 32.535 ;
     RECT  2.16 32.805 133.92 33.075 ;
     RECT  2.16 33.345 133.92 33.615 ;
     RECT  2.16 33.885 133.92 34.155 ;
     RECT  2.16 34.425 133.92 34.695 ;
     RECT  2.16 34.965 133.92 35.235 ;
     RECT  2.16 35.505 133.92 35.775 ;
     RECT  2.16 36.045 133.92 36.315 ;
     RECT  2.16 36.585 133.92 36.855 ;
     RECT  2.16 37.125 133.92 37.395 ;
     RECT  2.16 37.665 133.92 37.935 ;
     RECT  2.16 38.205 133.92 38.475 ;
     RECT  2.16 38.745 133.92 39.015 ;
     RECT  2.16 39.285 133.92 39.555 ;
     RECT  2.16 39.825 133.92 40.095 ;
     RECT  2.16 40.365 133.92 40.635 ;
     RECT  2.16 40.905 133.92 41.175 ;
     RECT  2.16 41.445 133.92 41.715 ;
     RECT  2.16 41.985 133.92 42.255 ;
     RECT  2.16 42.525 133.92 42.795 ;
     RECT  2.16 43.065 133.92 43.335 ;
     RECT  2.16 43.605 133.92 43.875 ;
     RECT  2.16 44.145 133.92 44.415 ;
     RECT  2.16 44.685 133.92 44.955 ;
     RECT  2.16 45.225 133.92 45.495 ;
     RECT  2.16 45.765 133.92 46.035 ;
     RECT  2.16 46.305 133.92 46.575 ;
     RECT  2.16 46.845 133.92 47.115 ;
     RECT  2.16 47.385 133.92 47.655 ;
     RECT  2.16 47.925 133.92 48.195 ;
     RECT  2.16 48.465 133.92 48.735 ;
     RECT  2.16 49.005 133.92 49.275 ;
     RECT  2.16 49.545 133.92 49.815 ;
     RECT  2.16 50.085 133.92 50.355 ;
     RECT  2.16 50.625 133.92 50.895 ;
     RECT  2.16 51.165 133.92 51.435 ;
     RECT  2.16 51.705 133.92 51.975 ;
     RECT  2.16 52.245 133.92 52.515 ;
     RECT  2.16 52.785 133.92 53.055 ;
     RECT  2.16 53.325 133.92 53.595 ;
     RECT  2.16 53.865 133.92 54.135 ;
     RECT  2.16 54.405 133.92 54.675 ;
     RECT  2.16 54.945 133.92 55.215 ;
     RECT  2.16 55.485 133.92 55.755 ;
     RECT  2.16 56.025 133.92 56.295 ;
     RECT  2.16 56.565 133.92 56.835 ;
     RECT  2.16 57.105 133.92 57.375 ;
     RECT  2.16 57.645 133.92 57.915 ;
     RECT  2.16 58.185 133.92 58.455 ;
     RECT  2.16 58.725 133.92 58.995 ;
     RECT  2.16 59.265 133.92 59.535 ;
     RECT  2.16 59.805 133.92 60.075 ;
     RECT  2.16 60.345 133.92 60.615 ;
     RECT  2.16 60.885 133.92 61.155 ;
     RECT  2.16 61.425 133.92 61.695 ;
     RECT  2.16 61.965 133.92 62.235 ;
     RECT  2.16 62.505 133.92 62.775 ;
     RECT  2.16 63.045 133.92 63.315 ;
     RECT  2.16 63.585 133.92 63.855 ;
     RECT  2.16 64.125 133.92 64.395 ;
     RECT  2.16 64.665 133.92 64.935 ;
     RECT  2.16 65.205 133.92 65.475 ;
     RECT  2.16 65.745 133.92 66.015 ;
     RECT  2.16 66.285 133.92 66.555 ;
     RECT  2.16 66.825 133.92 67.095 ;
     RECT  2.16 67.365 133.92 67.635 ;
     RECT  2.16 67.905 133.92 68.175 ;
     RECT  2.16 68.445 133.92 68.715 ;
     RECT  2.16 68.985 133.92 69.255 ;
     RECT  2.16 69.525 133.92 69.795 ;
     RECT  2.16 70.065 133.92 70.335 ;
     RECT  2.16 70.605 133.92 70.875 ;
     RECT  2.16 71.145 133.92 71.415 ;
     RECT  2.16 71.685 133.92 71.955 ;
     RECT  2.16 72.225 133.92 72.495 ;
     RECT  2.16 72.765 133.92 73.035 ;
     RECT  2.16 73.305 133.92 73.575 ;
     RECT  2.16 73.845 133.92 74.115 ;
     RECT  2.16 74.385 133.92 74.655 ;
     RECT  2.16 74.925 133.92 75.195 ;
     RECT  2.16 75.465 133.92 75.735 ;
     RECT  2.16 76.005 133.92 76.275 ;
     RECT  2.16 76.545 133.92 76.815 ;
     RECT  2.16 77.085 133.92 77.355 ;
     RECT  2.16 77.625 133.92 77.895 ;
     RECT  2.16 78.165 133.92 78.435 ;
     RECT  2.16 78.705 133.92 78.975 ;
     RECT  2.16 79.245 133.92 79.515 ;
     RECT  2.16 79.785 133.92 80.055 ;
     RECT  2.16 80.325 133.92 80.595 ;
     RECT  2.16 80.865 133.92 81.135 ;
     RECT  2.16 81.405 133.92 81.675 ;
     RECT  2.16 81.945 133.92 82.215 ;
     RECT  2.16 82.485 133.92 82.755 ;
     RECT  2.16 83.025 133.92 83.295 ;
     RECT  2.16 83.565 133.92 83.835 ;
     RECT  2.16 84.105 133.92 84.375 ;
     RECT  2.16 84.645 133.92 84.915 ;
     RECT  2.16 85.185 133.92 85.455 ;
     RECT  2.16 85.725 133.92 85.995 ;
     RECT  2.16 86.265 133.92 86.535 ;
     RECT  2.16 86.805 133.92 87.075 ;
     RECT  2.16 87.345 133.92 87.615 ;
     RECT  2.16 87.885 133.92 88.155 ;
     RECT  2.16 88.425 133.92 88.695 ;
     RECT  2.16 88.965 133.92 89.235 ;
     RECT  2.16 89.505 133.92 89.775 ;
     RECT  2.16 90.045 133.92 90.315 ;
     RECT  2.16 90.585 133.92 90.855 ;
     RECT  2.16 91.125 133.92 91.395 ;
     RECT  2.16 91.665 133.92 91.935 ;
     RECT  2.16 92.205 133.92 92.475 ;
     RECT  2.16 92.745 133.92 93.015 ;
     RECT  2.16 93.285 133.92 93.555 ;
     RECT  2.16 93.825 133.92 94.095 ;
     RECT  2.16 94.365 133.92 94.635 ;
     RECT  2.16 94.905 133.92 95.175 ;
     RECT  2.16 95.445 133.92 95.715 ;
     RECT  2.16 95.985 133.92 96.255 ;
     RECT  2.16 96.525 133.92 96.795 ;
     RECT  2.16 97.065 133.92 97.335 ;
     RECT  2.16 97.605 133.92 97.875 ;
     RECT  2.16 98.145 133.92 98.415 ;
     RECT  2.16 98.685 133.92 98.955 ;
     RECT  2.16 99.225 133.92 99.495 ;
     RECT  2.16 99.765 133.92 100.035 ;
     RECT  2.16 100.305 133.92 100.575 ;
     RECT  2.16 100.845 133.92 101.115 ;
     RECT  2.16 101.385 133.92 101.655 ;
     RECT  2.16 101.925 133.92 102.195 ;
     RECT  2.16 102.465 133.92 102.735 ;
     RECT  2.16 103.005 133.92 103.275 ;
     RECT  2.16 103.545 133.92 103.815 ;
     RECT  2.16 104.085 133.92 104.355 ;
     RECT  2.16 104.625 133.92 104.895 ;
     RECT  2.16 105.165 133.92 105.435 ;
     RECT  2.16 105.705 133.92 105.975 ;
     RECT  2.16 106.245 133.92 106.515 ;
     RECT  2.16 106.785 133.92 107.055 ;
     RECT  2.16 107.325 133.92 107.595 ;
     RECT  2.16 107.865 133.92 108 ;
    LAYER RVTP ;
     RECT  2.16 2.295 133.92 2.565 ;
     RECT  2.16 2.835 133.92 3.105 ;
     RECT  2.16 3.375 133.92 3.645 ;
     RECT  2.16 3.915 133.92 4.185 ;
     RECT  2.16 4.455 133.92 4.725 ;
     RECT  2.16 4.995 133.92 5.265 ;
     RECT  2.16 5.535 133.92 5.805 ;
     RECT  2.16 6.075 133.92 6.345 ;
     RECT  2.16 6.615 133.92 6.885 ;
     RECT  2.16 7.155 133.92 7.425 ;
     RECT  2.16 7.695 133.92 7.965 ;
     RECT  2.16 8.235 133.92 8.505 ;
     RECT  2.16 8.775 133.92 9.045 ;
     RECT  2.16 9.315 133.92 9.585 ;
     RECT  2.16 9.855 133.92 10.125 ;
     RECT  2.16 10.395 133.92 10.665 ;
     RECT  2.16 10.935 133.92 11.205 ;
     RECT  2.16 11.475 133.92 11.745 ;
     RECT  2.16 12.015 133.92 12.285 ;
     RECT  2.16 12.555 133.92 12.825 ;
     RECT  2.16 13.095 133.92 13.365 ;
     RECT  2.16 13.635 133.92 13.905 ;
     RECT  2.16 14.175 133.92 14.445 ;
     RECT  2.16 14.715 133.92 14.985 ;
     RECT  2.16 15.255 133.92 15.525 ;
     RECT  2.16 15.795 133.92 16.065 ;
     RECT  2.16 16.335 133.92 16.605 ;
     RECT  2.16 16.875 133.92 17.145 ;
     RECT  2.16 17.415 133.92 17.685 ;
     RECT  2.16 17.955 133.92 18.225 ;
     RECT  2.16 18.495 133.92 18.765 ;
     RECT  2.16 19.035 133.92 19.305 ;
     RECT  2.16 19.575 133.92 19.845 ;
     RECT  2.16 20.115 133.92 20.385 ;
     RECT  2.16 20.655 133.92 20.925 ;
     RECT  2.16 21.195 133.92 21.465 ;
     RECT  2.16 21.735 133.92 22.005 ;
     RECT  2.16 22.275 133.92 22.545 ;
     RECT  2.16 22.815 133.92 23.085 ;
     RECT  2.16 23.355 133.92 23.625 ;
     RECT  2.16 23.895 133.92 24.165 ;
     RECT  2.16 24.435 133.92 24.705 ;
     RECT  2.16 24.975 133.92 25.245 ;
     RECT  2.16 25.515 133.92 25.785 ;
     RECT  2.16 26.055 133.92 26.325 ;
     RECT  2.16 26.595 133.92 26.865 ;
     RECT  2.16 27.135 133.92 27.405 ;
     RECT  2.16 27.675 133.92 27.945 ;
     RECT  2.16 28.215 133.92 28.485 ;
     RECT  2.16 28.755 133.92 29.025 ;
     RECT  2.16 29.295 133.92 29.565 ;
     RECT  2.16 29.835 133.92 30.105 ;
     RECT  2.16 30.375 133.92 30.645 ;
     RECT  2.16 30.915 133.92 31.185 ;
     RECT  2.16 31.455 133.92 31.725 ;
     RECT  2.16 31.995 133.92 32.265 ;
     RECT  2.16 32.535 133.92 32.805 ;
     RECT  2.16 33.075 133.92 33.345 ;
     RECT  2.16 33.615 133.92 33.885 ;
     RECT  2.16 34.155 133.92 34.425 ;
     RECT  2.16 34.695 133.92 34.965 ;
     RECT  2.16 35.235 133.92 35.505 ;
     RECT  2.16 35.775 133.92 36.045 ;
     RECT  2.16 36.315 133.92 36.585 ;
     RECT  2.16 36.855 133.92 37.125 ;
     RECT  2.16 37.395 133.92 37.665 ;
     RECT  2.16 37.935 133.92 38.205 ;
     RECT  2.16 38.475 133.92 38.745 ;
     RECT  2.16 39.015 133.92 39.285 ;
     RECT  2.16 39.555 133.92 39.825 ;
     RECT  2.16 40.095 133.92 40.365 ;
     RECT  2.16 40.635 133.92 40.905 ;
     RECT  2.16 41.175 133.92 41.445 ;
     RECT  2.16 41.715 133.92 41.985 ;
     RECT  2.16 42.255 133.92 42.525 ;
     RECT  2.16 42.795 133.92 43.065 ;
     RECT  2.16 43.335 133.92 43.605 ;
     RECT  2.16 43.875 133.92 44.145 ;
     RECT  2.16 44.415 133.92 44.685 ;
     RECT  2.16 44.955 133.92 45.225 ;
     RECT  2.16 45.495 133.92 45.765 ;
     RECT  2.16 46.035 133.92 46.305 ;
     RECT  2.16 46.575 133.92 46.845 ;
     RECT  2.16 47.115 133.92 47.385 ;
     RECT  2.16 47.655 133.92 47.925 ;
     RECT  2.16 48.195 133.92 48.465 ;
     RECT  2.16 48.735 133.92 49.005 ;
     RECT  2.16 49.275 133.92 49.545 ;
     RECT  2.16 49.815 133.92 50.085 ;
     RECT  2.16 50.355 133.92 50.625 ;
     RECT  2.16 50.895 133.92 51.165 ;
     RECT  2.16 51.435 133.92 51.705 ;
     RECT  2.16 51.975 133.92 52.245 ;
     RECT  2.16 52.515 133.92 52.785 ;
     RECT  2.16 53.055 133.92 53.325 ;
     RECT  2.16 53.595 133.92 53.865 ;
     RECT  2.16 54.135 133.92 54.405 ;
     RECT  2.16 54.675 133.92 54.945 ;
     RECT  2.16 55.215 133.92 55.485 ;
     RECT  2.16 55.755 133.92 56.025 ;
     RECT  2.16 56.295 133.92 56.565 ;
     RECT  2.16 56.835 133.92 57.105 ;
     RECT  2.16 57.375 133.92 57.645 ;
     RECT  2.16 57.915 133.92 58.185 ;
     RECT  2.16 58.455 133.92 58.725 ;
     RECT  2.16 58.995 133.92 59.265 ;
     RECT  2.16 59.535 133.92 59.805 ;
     RECT  2.16 60.075 133.92 60.345 ;
     RECT  2.16 60.615 133.92 60.885 ;
     RECT  2.16 61.155 133.92 61.425 ;
     RECT  2.16 61.695 133.92 61.965 ;
     RECT  2.16 62.235 133.92 62.505 ;
     RECT  2.16 62.775 133.92 63.045 ;
     RECT  2.16 63.315 133.92 63.585 ;
     RECT  2.16 63.855 133.92 64.125 ;
     RECT  2.16 64.395 133.92 64.665 ;
     RECT  2.16 64.935 133.92 65.205 ;
     RECT  2.16 65.475 133.92 65.745 ;
     RECT  2.16 66.015 133.92 66.285 ;
     RECT  2.16 66.555 133.92 66.825 ;
     RECT  2.16 67.095 133.92 67.365 ;
     RECT  2.16 67.635 133.92 67.905 ;
     RECT  2.16 68.175 133.92 68.445 ;
     RECT  2.16 68.715 133.92 68.985 ;
     RECT  2.16 69.255 133.92 69.525 ;
     RECT  2.16 69.795 133.92 70.065 ;
     RECT  2.16 70.335 133.92 70.605 ;
     RECT  2.16 70.875 133.92 71.145 ;
     RECT  2.16 71.415 133.92 71.685 ;
     RECT  2.16 71.955 133.92 72.225 ;
     RECT  2.16 72.495 133.92 72.765 ;
     RECT  2.16 73.035 133.92 73.305 ;
     RECT  2.16 73.575 133.92 73.845 ;
     RECT  2.16 74.115 133.92 74.385 ;
     RECT  2.16 74.655 133.92 74.925 ;
     RECT  2.16 75.195 133.92 75.465 ;
     RECT  2.16 75.735 133.92 76.005 ;
     RECT  2.16 76.275 133.92 76.545 ;
     RECT  2.16 76.815 133.92 77.085 ;
     RECT  2.16 77.355 133.92 77.625 ;
     RECT  2.16 77.895 133.92 78.165 ;
     RECT  2.16 78.435 133.92 78.705 ;
     RECT  2.16 78.975 133.92 79.245 ;
     RECT  2.16 79.515 133.92 79.785 ;
     RECT  2.16 80.055 133.92 80.325 ;
     RECT  2.16 80.595 133.92 80.865 ;
     RECT  2.16 81.135 133.92 81.405 ;
     RECT  2.16 81.675 133.92 81.945 ;
     RECT  2.16 82.215 133.92 82.485 ;
     RECT  2.16 82.755 133.92 83.025 ;
     RECT  2.16 83.295 133.92 83.565 ;
     RECT  2.16 83.835 133.92 84.105 ;
     RECT  2.16 84.375 133.92 84.645 ;
     RECT  2.16 84.915 133.92 85.185 ;
     RECT  2.16 85.455 133.92 85.725 ;
     RECT  2.16 85.995 133.92 86.265 ;
     RECT  2.16 86.535 133.92 86.805 ;
     RECT  2.16 87.075 133.92 87.345 ;
     RECT  2.16 87.615 133.92 87.885 ;
     RECT  2.16 88.155 133.92 88.425 ;
     RECT  2.16 88.695 133.92 88.965 ;
     RECT  2.16 89.235 133.92 89.505 ;
     RECT  2.16 89.775 133.92 90.045 ;
     RECT  2.16 90.315 133.92 90.585 ;
     RECT  2.16 90.855 133.92 91.125 ;
     RECT  2.16 91.395 133.92 91.665 ;
     RECT  2.16 91.935 133.92 92.205 ;
     RECT  2.16 92.475 133.92 92.745 ;
     RECT  2.16 93.015 133.92 93.285 ;
     RECT  2.16 93.555 133.92 93.825 ;
     RECT  2.16 94.095 133.92 94.365 ;
     RECT  2.16 94.635 133.92 94.905 ;
     RECT  2.16 95.175 133.92 95.445 ;
     RECT  2.16 95.715 133.92 95.985 ;
     RECT  2.16 96.255 133.92 96.525 ;
     RECT  2.16 96.795 133.92 97.065 ;
     RECT  2.16 97.335 133.92 97.605 ;
     RECT  2.16 97.875 133.92 98.145 ;
     RECT  2.16 98.415 133.92 98.685 ;
     RECT  2.16 98.955 133.92 99.225 ;
     RECT  2.16 99.495 133.92 99.765 ;
     RECT  2.16 100.035 133.92 100.305 ;
     RECT  2.16 100.575 133.92 100.845 ;
     RECT  2.16 101.115 133.92 101.385 ;
     RECT  2.16 101.655 133.92 101.925 ;
     RECT  2.16 102.195 133.92 102.465 ;
     RECT  2.16 102.735 133.92 103.005 ;
     RECT  2.16 103.275 133.92 103.545 ;
     RECT  2.16 103.815 133.92 104.085 ;
     RECT  2.16 104.355 133.92 104.625 ;
     RECT  2.16 104.895 133.92 105.165 ;
     RECT  2.16 105.435 133.92 105.705 ;
     RECT  2.16 105.975 133.92 106.245 ;
     RECT  2.16 106.515 133.92 106.785 ;
     RECT  2.16 107.055 133.92 107.325 ;
     RECT  2.16 107.595 133.92 107.865 ;
    LAYER M1 ;
     RECT  2.16 2.151 133.92 108.009 ;
    LAYER M2 ;
     RECT  0.031 69.426 0.067 69.444 ;
     RECT  0.031 54.072 0.103 54.09 ;
     RECT  0.067 69.156 0.103 69.444 ;
     RECT  0.031 52.686 0.139 52.704 ;
     RECT  0.103 53.496 0.139 54.09 ;
     RECT  0.103 68.724 0.139 69.444 ;
     RECT  0.139 52.416 0.247 54.09 ;
     RECT  0.139 67.806 0.247 67.824 ;
     RECT  0.139 68.724 0.247 69.669 ;
     RECT  0.247 67.806 0.311 69.669 ;
     RECT  0.247 52.326 0.347 54.09 ;
     RECT  0.499 50.976 0.535 50.994 ;
     RECT  0.347 52.326 0.535 52.434 ;
     RECT  0.311 67.806 0.707 69.552 ;
     RECT  0.067 81.144 0.823 81.162 ;
     RECT  0.707 69.264 0.851 69.552 ;
     RECT  0.535 50.976 0.887 52.434 ;
     RECT  0.031 25.326 1.147 25.344 ;
     RECT  1.147 25.254 1.175 25.344 ;
     RECT  1.175 25.254 1.399 25.272 ;
     RECT  0.851 69.534 1.427 69.552 ;
     RECT  0.895 41.994 1.435 42.012 ;
     RECT  0.823 36.936 1.471 36.954 ;
     RECT  0.823 81.036 2.155 81.162 ;
     RECT  1.399 24.75 2.16 25.272 ;
     RECT  1.975 27.846 2.16 27.864 ;
     RECT  1.471 36.396 2.16 36.954 ;
     RECT  1.435 41.994 2.16 42.174 ;
     RECT  0.887 50.976 2.16 52.344 ;
     RECT  0.347 53.334 2.16 54.09 ;
     RECT  0.067 61.974 2.16 61.992 ;
     RECT  0.707 67.806 2.16 68.4 ;
     RECT  0.247 74.556 2.16 74.574 ;
     RECT  0.211 78.066 2.16 78.084 ;
     RECT  0.139 79.452 2.16 79.47 ;
     RECT  2.155 81.036 2.16 81.324 ;
     RECT  2.16 2.151 13.135 108.009 ;
     RECT  13.135 2.151 14.143 108.054 ;
     RECT  14.143 2.106 14.639 108.054 ;
     RECT  14.639 2.151 14.963 108.054 ;
     RECT  14.963 2.151 19.543 108.009 ;
     RECT  19.543 2.106 24.799 108.009 ;
     RECT  24.799 2.07 46.759 108.009 ;
     RECT  46.759 2.034 54.419 108.009 ;
     RECT  100.363 1.152 100.679 1.17 ;
     RECT  54.419 2.07 100.795 108.009 ;
     RECT  100.795 1.728 100.895 108.009 ;
     RECT  100.895 2.07 102.019 108.009 ;
     RECT  102.019 2.034 102.551 108.009 ;
     RECT  102.551 2.07 104.963 108.009 ;
     RECT  104.963 2.106 128.507 108.009 ;
     RECT  128.507 2.151 133.92 108.009 ;
     RECT  133.92 60.696 133.943 61.416 ;
     RECT  133.92 65.556 133.943 65.574 ;
     RECT  133.92 68.958 133.979 68.976 ;
     RECT  133.92 66.456 134.015 67.464 ;
     RECT  134.015 66.456 134.087 66.924 ;
     RECT  133.92 62.208 134.123 64.656 ;
     RECT  133.92 59.076 134.231 59.094 ;
     RECT  133.92 37.17 134.555 40.428 ;
     RECT  134.087 66.456 135.059 66.654 ;
     RECT  134.555 37.602 135.095 40.428 ;
     RECT  133.943 61.398 135.095 61.416 ;
     RECT  133.92 35.586 135.131 36.414 ;
     RECT  135.095 37.602 135.131 37.62 ;
     RECT  134.123 62.208 135.131 64.314 ;
     RECT  135.131 62.208 135.167 62.424 ;
     RECT  135.131 35.586 135.239 36.306 ;
     RECT  135.239 35.586 135.275 36.108 ;
     RECT  135.275 36.09 135.311 36.108 ;
     RECT  135.095 38.646 135.815 39.204 ;
     RECT  135.131 64.098 135.815 64.314 ;
     RECT  135.815 38.646 135.851 39.114 ;
     RECT  135.851 38.646 135.859 38.664 ;
     RECT  135.095 40.176 135.887 40.428 ;
     RECT  135.167 62.208 135.887 62.226 ;
     RECT  135.815 64.098 135.887 64.224 ;
     RECT  135.859 38.214 135.923 38.664 ;
     RECT  135.887 64.098 135.923 64.116 ;
     RECT  135.059 66.456 135.923 66.474 ;
     RECT  135.923 38.214 136.067 38.232 ;
     RECT  135.887 40.176 136.067 40.194 ;
    LAYER M3 ;
     RECT  11.556 0.139 11.574 0.187 ;
     RECT  13.14 0.139 13.158 0.187 ;
     RECT  100.872 0.139 100.89 0.187 ;
     RECT  13.14 0.187 13.698 0.283 ;
     RECT  99.972 0.475 99.99 0.523 ;
     RECT  100.872 0.187 101.358 0.523 ;
     RECT  11.556 0.187 11.97 0.571 ;
     RECT  99.972 0.523 101.358 0.571 ;
     RECT  102.492 0.139 102.51 0.571 ;
     RECT  11.556 0.571 12.33 1.099 ;
     RECT  13.104 0.283 13.698 1.099 ;
     RECT  11.556 1.099 13.698 1.147 ;
     RECT  99.972 0.571 102.51 1.723 ;
     RECT  99.972 1.723 102.582 1.771 ;
     RECT  74.34 1.723 74.358 1.819 ;
     RECT  24.912 0.043 24.93 2.065 ;
     RECT  11.412 1.147 13.698 2.101 ;
     RECT  19.368 2.059 19.386 2.101 ;
     RECT  24.804 2.065 24.93 2.101 ;
     RECT  50.616 2.029 50.742 2.101 ;
     RECT  54.396 2.029 54.414 2.101 ;
     RECT  19.368 2.101 19.566 2.143 ;
     RECT  24.804 2.101 25.434 2.143 ;
     RECT  50.544 2.101 50.742 2.143 ;
     RECT  99.972 1.771 103.122 2.143 ;
     RECT  104.94 2.065 104.958 2.143 ;
     RECT  11.412 2.101 14.634 2.191 ;
     RECT  18.615 2.143 19.566 2.191 ;
     RECT  24.015 2.143 25.434 2.191 ;
     RECT  29.415 2.143 29.505 2.191 ;
     RECT  34.815 2.143 34.905 2.191 ;
     RECT  45.615 2.143 45.705 2.191 ;
     RECT  46.764 2.029 46.782 2.191 ;
     RECT  58.968 2.101 58.986 2.191 ;
     RECT  74.232 1.819 74.358 2.191 ;
     RECT  78.015 2.143 78.105 2.191 ;
     RECT  90.252 2.101 90.27 2.191 ;
     RECT  91.224 2.059 91.242 2.191 ;
     RECT  94.215 2.143 94.305 2.191 ;
     RECT  99.615 2.143 103.122 2.191 ;
     RECT  110.415 2.143 110.505 2.191 ;
     RECT  126.615 2.143 126.705 2.191 ;
     RECT  18.216 2.191 19.566 2.227 ;
     RECT  49.5 2.101 49.518 2.227 ;
     RECT  53.064 2.101 53.082 2.227 ;
     RECT  54.324 2.101 54.414 2.227 ;
     RECT  55.368 2.191 55.386 2.227 ;
     RECT  77.184 2.191 77.202 2.227 ;
     RECT  78.015 2.191 78.39 2.227 ;
     RECT  83.415 2.143 83.505 2.227 ;
     RECT  114.588 2.191 114.606 2.227 ;
     RECT  115.815 2.143 115.905 2.227 ;
     RECT  17.64 2.227 19.566 2.251 ;
     RECT  31.68 2.191 31.698 2.251 ;
     RECT  36.828 2.101 36.846 2.251 ;
     RECT  40.215 2.143 40.305 2.251 ;
     RECT  88.815 2.143 88.905 2.251 ;
     RECT  99.615 2.191 104.13 2.251 ;
     RECT  115.815 2.227 116.19 2.251 ;
     RECT  126.324 2.191 126.705 2.251 ;
     RECT  2.415 2.143 2.505 2.263 ;
     RECT  7.815 2.143 7.905 2.263 ;
     RECT  17.64 2.251 20.286 2.263 ;
     RECT  31.68 2.251 32.058 2.263 ;
     RECT  48.528 2.227 48.546 2.263 ;
     RECT  49.5 2.227 49.626 2.263 ;
     RECT  53.064 2.227 53.406 2.263 ;
     RECT  54.324 2.227 55.386 2.263 ;
     RECT  76.392 2.191 76.41 2.263 ;
     RECT  77.184 2.227 78.39 2.263 ;
     RECT  83.415 2.227 84.222 2.263 ;
     RECT  90.252 2.191 91.242 2.263 ;
     RECT  94.032 2.191 94.41 2.263 ;
     RECT  95.148 2.191 95.166 2.263 ;
     RECT  99 2.251 104.13 2.263 ;
     RECT  104.94 2.143 105.105 2.263 ;
     RECT  109.728 2.191 110.505 2.263 ;
     RECT  10.188 2.191 14.634 2.299 ;
     RECT  16.848 2.263 20.286 2.299 ;
     RECT  21.096 2.227 21.114 2.299 ;
     RECT  22.752 2.101 22.842 2.299 ;
     RECT  31.464 2.263 32.058 2.299 ;
     RECT  34.092 2.191 34.905 2.299 ;
     RECT  36.504 2.251 36.846 2.299 ;
     RECT  37.656 2.251 37.674 2.299 ;
     RECT  42.444 2.263 42.75 2.299 ;
     RECT  45.615 2.191 46.782 2.299 ;
     RECT  47.772 2.263 49.626 2.299 ;
     RECT  53.064 2.263 55.386 2.299 ;
     RECT  56.415 2.143 56.505 2.299 ;
     RECT  58.968 2.191 59.058 2.299 ;
     RECT  72.432 2.101 72.882 2.299 ;
     RECT  76.392 2.263 78.39 2.299 ;
     RECT  82.548 2.263 82.566 2.299 ;
     RECT  83.415 2.263 85.482 2.299 ;
     RECT  86.724 2.227 87.102 2.299 ;
     RECT  88.632 2.251 88.905 2.299 ;
     RECT  99 2.263 105.105 2.299 ;
     RECT  106.344 2.263 106.686 2.299 ;
     RECT  107.748 2.227 107.766 2.299 ;
     RECT  109.404 2.263 110.505 2.299 ;
     RECT  115.815 2.251 116.802 2.299 ;
     RECT  117.54 2.227 117.558 2.299 ;
     RECT  121.215 2.143 121.305 2.299 ;
     RECT  2.415 2.263 2.97 2.335 ;
     RECT  21.096 2.299 21.294 2.335 ;
     RECT  33.732 2.299 34.905 2.335 ;
     RECT  36.504 2.299 37.674 2.335 ;
     RECT  38.772 2.299 38.79 2.335 ;
     RECT  41.544 2.227 41.562 2.335 ;
     RECT  42.444 2.299 42.966 2.335 ;
     RECT  58.464 2.299 59.454 2.335 ;
     RECT  61.815 2.143 61.905 2.335 ;
     RECT  64.98 2.251 64.998 2.335 ;
     RECT  67.215 2.143 67.305 2.335 ;
     RECT  68.256 2.299 68.274 2.335 ;
     RECT  72.432 2.299 72.954 2.335 ;
     RECT  76.392 2.299 78.678 2.335 ;
     RECT  96.912 2.299 96.93 2.335 ;
     RECT  107.712 2.299 107.766 2.335 ;
     RECT  114.588 2.227 114.858 2.335 ;
     RECT  115.815 2.299 117.558 2.335 ;
     RECT  57.42 2.335 57.438 2.347 ;
     RECT  58.464 2.335 59.706 2.347 ;
     RECT  61.272 2.335 61.938 2.347 ;
     RECT  94.032 2.263 95.166 2.347 ;
     RECT  107.424 2.335 107.766 2.347 ;
     RECT  2.415 2.335 3.042 2.371 ;
     RECT  5.832 2.263 6.39 2.371 ;
     RECT  7.815 2.263 8.406 2.371 ;
     RECT  16.596 2.299 20.286 2.371 ;
     RECT  21.096 2.335 21.33 2.371 ;
     RECT  22.752 2.299 22.986 2.371 ;
     RECT  36.468 2.335 37.674 2.371 ;
     RECT  38.736 2.335 38.79 2.371 ;
     RECT  40.215 2.251 40.59 2.371 ;
     RECT  41.544 2.335 43.542 2.371 ;
     RECT  45.615 2.299 49.626 2.371 ;
     RECT  50.544 2.143 51.105 2.371 ;
     RECT  57.42 2.347 59.706 2.371 ;
     RECT  64.368 2.335 64.998 2.371 ;
     RECT  71.892 2.335 72.954 2.371 ;
     RECT  73.692 2.191 74.466 2.371 ;
     RECT  76.212 2.335 78.678 2.371 ;
     RECT  88.632 2.299 88.974 2.371 ;
     RECT  90.252 2.263 91.89 2.371 ;
     RECT  99 2.299 106.686 2.371 ;
     RECT  114.444 2.335 114.858 2.371 ;
     RECT  115.74 2.335 117.558 2.371 ;
     RECT  118.584 2.299 118.674 2.371 ;
     RECT  132.015 2.143 132.105 2.371 ;
     RECT  33.66 2.335 34.905 2.413 ;
     RECT  45.615 2.371 51.105 2.413 ;
     RECT  53.064 2.299 56.505 2.413 ;
     RECT  66.924 2.335 67.305 2.413 ;
     RECT  108.828 2.299 110.505 2.413 ;
     RECT  125.892 2.251 126.705 2.413 ;
     RECT  16.596 2.371 21.33 2.443 ;
     RECT  57.42 2.371 60.21 2.443 ;
     RECT  87.984 2.371 91.89 2.443 ;
     RECT  108.828 2.413 110.697 2.443 ;
     RECT  113.22 2.299 113.238 2.443 ;
     RECT  4.14 2.371 4.158 2.461 ;
     RECT  29.415 2.191 29.862 2.461 ;
     RECT  30.78 2.299 32.058 2.461 ;
     RECT  40.215 2.371 43.542 2.461 ;
     RECT  44.46 2.347 44.478 2.461 ;
     RECT  53.064 2.413 56.697 2.461 ;
     RECT  57.42 2.443 60.282 2.461 ;
     RECT  70.668 2.299 70.686 2.461 ;
     RECT  71.892 2.371 74.466 2.461 ;
     RECT  75.564 2.371 78.75 2.461 ;
     RECT  86.652 2.299 87.102 2.461 ;
     RECT  87.984 2.443 91.998 2.461 ;
     RECT  108.828 2.443 110.79 2.461 ;
     RECT  121.215 2.299 121.554 2.461 ;
     RECT  124.272 2.299 124.29 2.461 ;
     RECT  29.268 2.461 29.862 2.491 ;
     RECT  30.708 2.461 32.382 2.491 ;
     RECT  33.66 2.413 35.097 2.491 ;
     RECT  35.928 2.371 38.79 2.491 ;
     RECT  96.228 2.335 96.93 2.491 ;
     RECT  97.812 2.371 97.83 2.491 ;
     RECT  33.552 2.491 35.097 2.497 ;
     RECT  63.216 2.371 63.342 2.497 ;
     RECT  64.26 2.371 64.998 2.497 ;
     RECT  66.924 2.413 67.497 2.497 ;
     RECT  81.864 2.299 85.482 2.497 ;
     RECT  93.996 2.347 95.166 2.497 ;
     RECT  114.444 2.371 117.558 2.497 ;
     RECT  119.88 2.461 120.042 2.497 ;
     RECT  123.228 2.335 123.246 2.497 ;
     RECT  129.708 2.461 129.726 2.497 ;
     RECT  132.015 2.371 132.678 2.497 ;
     RECT  2.415 2.371 3.114 2.533 ;
     RECT  4.14 2.461 4.23 2.533 ;
     RECT  5.148 2.371 6.39 2.533 ;
     RECT  22.5 2.371 22.986 2.533 ;
     RECT  24.015 2.191 25.614 2.533 ;
     RECT  27.504 2.461 27.594 2.533 ;
     RECT  44.388 2.461 44.478 2.533 ;
     RECT  81.36 2.497 85.482 2.533 ;
     RECT  129.708 2.497 129.978 2.533 ;
     RECT  131.688 2.497 132.678 2.533 ;
     RECT  33.48 2.497 35.097 2.539 ;
     RECT  35.892 2.491 38.79 2.539 ;
     RECT  40.215 2.461 43.65 2.539 ;
     RECT  93.492 2.497 95.166 2.539 ;
     RECT  96.228 2.491 97.83 2.539 ;
     RECT  10.188 2.299 15.678 2.569 ;
     RECT  29.268 2.491 32.382 2.569 ;
     RECT  39.564 2.539 43.65 2.569 ;
     RECT  44.388 2.533 44.658 2.569 ;
     RECT  45.615 2.413 51.297 2.569 ;
     RECT  52.596 2.461 60.282 2.569 ;
     RECT  79.668 2.533 79.686 2.569 ;
     RECT  80.964 2.533 85.482 2.569 ;
     RECT  86.652 2.461 91.998 2.569 ;
     RECT  112.86 2.443 113.238 2.569 ;
     RECT  114.444 2.497 117.81 2.569 ;
     RECT  118.584 2.371 118.746 2.569 ;
     RECT  122.868 2.497 123.246 2.569 ;
     RECT  124.272 2.461 124.83 2.569 ;
     RECT  98.784 2.371 106.686 2.587 ;
     RECT  108.828 2.461 111.402 2.587 ;
     RECT  10.152 2.569 15.678 2.605 ;
     RECT  27.108 2.533 27.594 2.605 ;
     RECT  29.052 2.569 32.382 2.605 ;
     RECT  33.48 2.539 38.79 2.605 ;
     RECT  39.528 2.569 51.297 2.605 ;
     RECT  52.524 2.569 60.282 2.605 ;
     RECT  61.272 2.347 62.298 2.605 ;
     RECT  68.256 2.335 68.706 2.605 ;
     RECT  69.66 2.371 69.894 2.605 ;
     RECT  98.676 2.587 106.686 2.605 ;
     RECT  107.424 2.347 107.802 2.605 ;
     RECT  108.828 2.587 111.474 2.605 ;
     RECT  112.788 2.569 113.454 2.605 ;
     RECT  114.444 2.569 118.818 2.605 ;
     RECT  119.88 2.497 120.15 2.605 ;
     RECT  121.215 2.461 121.806 2.605 ;
     RECT  122.868 2.569 124.83 2.605 ;
     RECT  128.16 2.101 128.502 2.605 ;
     RECT  61.272 2.605 62.37 2.635 ;
     RECT  2.415 2.533 3.186 2.641 ;
     RECT  4.14 2.533 6.39 2.641 ;
     RECT  7.815 2.371 9.126 2.641 ;
     RECT  10.08 2.605 15.678 2.641 ;
     RECT  16.596 2.443 21.402 2.641 ;
     RECT  22.284 2.533 22.986 2.641 ;
     RECT  24.015 2.533 25.722 2.641 ;
     RECT  52.344 2.605 60.282 2.641 ;
     RECT  63.216 2.497 64.998 2.641 ;
     RECT  65.736 2.371 66.042 2.641 ;
     RECT  66.78 2.497 67.497 2.641 ;
     RECT  68.256 2.605 69.894 2.641 ;
     RECT  70.632 2.461 70.686 2.641 ;
     RECT  71.892 2.461 78.75 2.641 ;
     RECT  79.668 2.569 85.482 2.641 ;
     RECT  86.652 2.569 92.322 2.641 ;
     RECT  93.492 2.539 97.83 2.641 ;
     RECT  112.716 2.605 113.454 2.641 ;
     RECT  114.192 2.605 118.818 2.641 ;
     RECT  122.76 2.605 124.83 2.641 ;
     RECT  125.892 2.413 126.897 2.641 ;
     RECT  129.528 2.533 129.978 2.641 ;
     RECT  130.968 2.533 132.678 2.641 ;
     RECT  2.415 2.641 3.258 2.731 ;
     RECT  4.14 2.641 6.57 2.731 ;
     RECT  26.928 2.605 32.382 2.731 ;
     RECT  33.48 2.605 51.297 2.731 ;
     RECT  98.676 2.605 111.474 2.731 ;
     RECT  7.815 2.641 15.678 2.767 ;
     RECT  61.272 2.635 62.478 2.767 ;
     RECT  63.216 2.641 66.042 2.767 ;
     RECT  128.016 2.605 128.502 2.767 ;
     RECT  2.415 2.731 6.57 2.779 ;
     RECT  7.344 2.767 15.678 2.779 ;
     RECT  16.524 2.641 22.986 2.803 ;
     RECT  24.015 2.641 25.83 2.803 ;
     RECT  79.668 2.641 85.878 2.803 ;
     RECT  86.652 2.641 97.83 2.803 ;
     RECT  98.604 2.731 111.474 2.803 ;
     RECT  122.76 2.641 126.897 2.803 ;
     RECT  128.016 2.767 128.754 2.803 ;
     RECT  16.524 2.803 25.83 2.827 ;
     RECT  26.928 2.731 51.297 2.827 ;
     RECT  2.415 2.779 15.678 2.839 ;
     RECT  16.524 2.827 25.866 2.839 ;
     RECT  71.604 2.641 78.75 2.839 ;
     RECT  119.844 2.605 120.438 2.839 ;
     RECT  121.215 2.605 121.842 2.839 ;
     RECT  26.676 2.827 51.297 2.875 ;
     RECT  52.344 2.641 60.354 2.875 ;
     RECT  79.632 2.803 111.474 2.875 ;
     RECT  119.844 2.839 121.842 2.875 ;
     RECT  122.76 2.803 128.754 2.875 ;
     RECT  26.676 2.875 60.354 2.911 ;
     RECT  61.272 2.767 66.042 2.911 ;
     RECT  66.78 2.641 70.686 2.911 ;
     RECT  2.415 2.839 25.866 2.971 ;
     RECT  26.676 2.911 70.686 2.971 ;
     RECT  2.415 2.971 70.686 3.001 ;
     RECT  71.568 2.839 78.75 3.001 ;
     RECT  119.844 2.875 128.754 3.001 ;
     RECT  2.415 3.001 78.75 3.037 ;
     RECT  79.524 2.875 111.474 3.037 ;
     RECT  2.415 3.037 111.474 3.067 ;
     RECT  119.7 3.001 128.754 3.109 ;
     RECT  129.528 2.641 132.678 3.109 ;
     RECT  2.415 3.067 111.978 3.181 ;
     RECT  112.716 2.641 118.818 3.181 ;
     RECT  2.415 3.181 118.818 3.259 ;
     RECT  119.7 3.109 132.678 3.259 ;
     RECT  2.415 3.259 132.678 3.271 ;
     RECT  133.776 3.181 133.794 3.299 ;
     RECT  2.415 3.271 132.75 3.307 ;
     RECT  2.415 3.307 132.822 3.407 ;
     RECT  37.512 3.407 132.822 3.437 ;
     RECT  60.552 3.437 132.822 3.911 ;
     RECT  77.184 3.911 132.822 3.919 ;
     RECT  2.415 3.407 36.774 4.225 ;
     RECT  37.512 3.437 59.778 4.225 ;
     RECT  77.184 3.919 132.894 4.225 ;
     RECT  77.184 4.225 132.966 4.301 ;
     RECT  92.88 4.301 132.966 4.387 ;
     RECT  2.415 4.225 59.778 4.507 ;
     RECT  60.552 3.911 76.41 4.507 ;
     RECT  2.415 4.507 76.41 4.765 ;
     RECT  77.184 4.301 92.07 4.765 ;
     RECT  2.415 4.765 92.07 5.197 ;
     RECT  92.88 4.387 133.29 5.197 ;
     RECT  2.415 5.197 133.29 10.411 ;
     RECT  2.304 10.411 133.29 11.281 ;
     RECT  2.304 11.281 133.362 13.711 ;
     RECT  2.304 13.711 133.686 14.099 ;
     RECT  2.304 14.099 133.362 15.025 ;
     RECT  2.232 15.025 133.362 15.295 ;
     RECT  2.232 15.295 133.434 15.719 ;
     RECT  2.232 15.719 133.362 18.797 ;
     RECT  2.232 18.797 133.29 19.921 ;
     RECT  2.232 19.921 133.686 20.183 ;
     RECT  2.232 20.183 133.29 20.461 ;
     RECT  2.196 20.461 133.29 20.965 ;
     RECT  2.196 20.965 133.362 22.073 ;
     RECT  2.196 22.073 132.786 22.891 ;
     RECT  2.196 22.891 132.894 23.125 ;
     RECT  2.196 23.125 133.038 23.161 ;
     RECT  2.196 23.161 133.686 23.279 ;
     RECT  2.196 23.279 132.858 23.885 ;
     RECT  2.232 23.885 132.858 24.241 ;
     RECT  2.232 24.241 132.93 24.629 ;
     RECT  2.268 24.629 132.93 24.673 ;
     RECT  2.268 24.673 132.966 25.099 ;
     RECT  1.404 24.745 1.422 25.249 ;
     RECT  2.268 25.099 133.074 25.249 ;
     RECT  1.152 25.249 1.422 25.349 ;
     RECT  2.268 25.249 133.506 25.439 ;
     RECT  2.268 25.439 132.75 26.401 ;
     RECT  2.268 26.401 132.786 26.941 ;
     RECT  2.268 26.941 132.93 27.059 ;
     RECT  2.268 27.059 132.894 27.365 ;
     RECT  2.268 27.365 132.822 27.401 ;
     RECT  1.404 25.349 1.422 27.841 ;
     RECT  2.268 27.401 132.75 27.841 ;
     RECT  1.404 27.841 132.75 28.147 ;
     RECT  1.404 28.147 133.254 29.605 ;
     RECT  1.404 29.605 133.794 30.029 ;
     RECT  1.404 30.029 133.254 31.801 ;
     RECT  1.404 31.801 133.722 33.349 ;
     RECT  1.404 33.349 133.794 34.501 ;
     RECT  135.252 35.581 135.27 35.851 ;
     RECT  135.144 35.851 135.27 36.085 ;
     RECT  135.144 36.085 135.306 36.391 ;
     RECT  1.404 34.501 133.83 36.475 ;
     RECT  1.404 36.475 134.01 36.931 ;
     RECT  0.828 36.931 134.01 37.165 ;
     RECT  135.108 36.391 135.306 37.165 ;
     RECT  0.828 37.165 135.306 38.059 ;
     RECT  0.828 38.059 135.918 38.209 ;
     RECT  0.828 38.209 136.062 38.429 ;
     RECT  135.072 38.429 136.062 39.209 ;
     RECT  0.036 25.321 0.054 39.211 ;
     RECT  0.828 38.429 134.298 39.211 ;
     RECT  135.072 39.209 135.09 39.587 ;
     RECT  0.036 39.211 134.298 39.929 ;
     RECT  0.036 39.929 134.226 40.019 ;
     RECT  0.036 40.019 133.83 40.199 ;
     RECT  135.864 39.209 136.062 40.199 ;
     RECT  135.864 40.199 135.882 40.433 ;
     RECT  0.036 40.199 133.794 42.719 ;
     RECT  0.036 42.719 133.542 43.529 ;
     RECT  0.036 43.529 133.182 44.689 ;
     RECT  0.036 44.689 133.578 45.805 ;
     RECT  0.036 45.805 133.722 45.959 ;
     RECT  0.036 45.959 133.254 47.623 ;
     RECT  0.036 47.623 133.326 48.119 ;
     RECT  0.036 48.119 133.254 49.819 ;
     RECT  0.036 49.819 133.398 50.459 ;
     RECT  0.036 50.459 133.362 51.539 ;
     RECT  0.036 51.539 133.254 52.685 ;
     RECT  0.036 52.685 1.458 52.709 ;
     RECT  2.268 52.685 133.254 53.131 ;
     RECT  2.268 53.131 133.326 53.453 ;
     RECT  0.144 52.709 1.458 53.491 ;
     RECT  0.108 53.491 1.458 53.549 ;
     RECT  1.116 53.549 1.458 53.597 ;
     RECT  0.108 53.549 0.342 53.645 ;
     RECT  0.108 53.645 0.27 53.803 ;
     RECT  2.304 53.453 133.326 53.825 ;
     RECT  0.072 53.803 0.27 53.837 ;
     RECT  0.072 53.837 0.09 54.067 ;
     RECT  2.304 53.825 133.254 54.599 ;
     RECT  2.304 54.599 133.11 56.911 ;
     RECT  2.304 56.911 133.254 58.415 ;
     RECT  2.415 58.415 133.254 58.531 ;
     RECT  2.415 58.531 133.866 59.071 ;
     RECT  0.036 54.067 0.09 61.997 ;
     RECT  135.072 61.393 135.09 62.401 ;
     RECT  135.864 62.203 135.882 62.401 ;
     RECT  2.415 59.071 134.226 62.581 ;
     RECT  135.072 62.401 135.882 62.581 ;
     RECT  2.415 62.581 135.882 63.581 ;
     RECT  135.036 63.581 135.882 63.835 ;
     RECT  135.036 63.835 135.918 64.085 ;
     RECT  135.792 64.085 135.918 64.319 ;
     RECT  2.415 63.581 134.118 64.661 ;
     RECT  2.415 64.661 134.082 65.641 ;
     RECT  2.376 65.641 134.082 65.713 ;
     RECT  2.34 65.713 134.082 65.975 ;
     RECT  135.9 64.319 135.918 66.479 ;
     RECT  135.036 64.085 135.054 66.659 ;
     RECT  2.376 65.975 134.082 66.929 ;
     RECT  2.376 66.929 134.01 67.469 ;
     RECT  0.036 61.997 0.054 67.801 ;
     RECT  0.036 67.801 0.162 68.155 ;
     RECT  0.036 68.155 0.198 68.377 ;
     RECT  0.036 68.377 0.27 68.539 ;
     RECT  0.036 68.539 0.45 68.719 ;
     RECT  2.376 67.469 133.974 68.827 ;
     RECT  2.304 68.827 133.974 68.981 ;
     RECT  0.036 68.719 0.702 69.019 ;
     RECT  1.44 53.597 1.458 69.019 ;
     RECT  2.304 68.981 133.794 69.061 ;
     RECT  2.268 69.061 133.794 69.101 ;
     RECT  0.036 69.019 1.458 69.449 ;
     RECT  2.304 69.101 133.794 69.449 ;
     RECT  0.072 69.449 1.458 69.629 ;
     RECT  2.34 69.449 133.722 69.719 ;
     RECT  2.376 69.719 133.722 70.259 ;
     RECT  2.415 70.259 133.182 72.841 ;
     RECT  2.34 72.841 133.182 74.353 ;
     RECT  2.304 74.353 133.182 75.001 ;
     RECT  2.304 75.001 133.722 75.389 ;
     RECT  2.304 75.389 133.182 76.739 ;
     RECT  2.376 76.739 133.182 77.971 ;
     RECT  2.34 77.971 133.398 78.089 ;
     RECT  2.34 78.089 133.182 78.673 ;
     RECT  0.072 69.629 1.422 79.475 ;
     RECT  2.304 78.673 133.182 80.429 ;
     RECT  0.828 79.475 1.422 81.059 ;
     RECT  0.072 79.475 0.09 81.167 ;
     RECT  2.304 80.429 133.074 81.301 ;
     RECT  2.16 81.301 133.074 82.013 ;
     RECT  1.404 81.059 1.422 82.253 ;
     RECT  2.16 82.013 133.002 82.679 ;
     RECT  2.16 82.679 132.93 83.219 ;
     RECT  133.776 83.101 133.794 83.219 ;
     RECT  2.16 83.219 132.894 83.261 ;
     RECT  2.196 83.261 132.894 83.597 ;
     RECT  2.268 83.597 132.894 84.839 ;
     RECT  2.268 84.839 132.822 85.765 ;
     RECT  2.268 85.765 132.894 85.999 ;
     RECT  2.268 85.999 133.362 86.729 ;
     RECT  2.268 86.729 133.254 87.511 ;
     RECT  2.268 87.511 133.398 87.581 ;
     RECT  2.268 87.581 133.074 87.677 ;
     RECT  2.268 87.677 133.002 87.809 ;
     RECT  2.268 87.809 132.93 88.079 ;
     RECT  2.268 88.079 132.858 89.239 ;
     RECT  2.268 89.239 133.074 89.339 ;
     RECT  2.268 89.339 132.966 90.275 ;
     RECT  2.304 90.275 132.966 90.319 ;
     RECT  2.304 90.319 133.002 91.561 ;
     RECT  2.304 91.561 133.146 92.129 ;
     RECT  2.304 92.129 133.002 92.975 ;
     RECT  2.34 92.975 133.002 93.209 ;
     RECT  2.34 93.209 132.966 93.749 ;
     RECT  2.415 93.749 132.966 94.711 ;
     RECT  2.415 94.711 133.074 94.829 ;
     RECT  2.415 94.829 132.966 96.061 ;
     RECT  2.415 96.061 133.074 96.179 ;
     RECT  2.415 96.179 132.966 97.501 ;
     RECT  2.415 97.501 133.254 97.601 ;
     RECT  2.415 97.601 133.182 98.491 ;
     RECT  2.415 98.491 133.398 99.265 ;
     RECT  2.415 99.265 133.794 99.419 ;
     RECT  2.415 99.419 133.398 101.579 ;
     RECT  2.415 101.579 133.002 102.091 ;
     RECT  2.304 102.091 133.002 102.155 ;
     RECT  2.376 102.155 133.002 102.389 ;
     RECT  2.376 102.389 132.966 102.533 ;
     RECT  2.376 102.533 132.858 102.659 ;
     RECT  2.376 102.659 132.75 103.235 ;
     RECT  2.415 103.235 132.75 104.045 ;
     RECT  74.34 104.045 132.75 104.161 ;
     RECT  74.34 104.161 133.362 104.279 ;
     RECT  2.415 104.045 73.602 104.899 ;
     RECT  74.34 104.279 132.93 104.899 ;
     RECT  133.776 105.241 133.794 105.359 ;
     RECT  2.415 104.899 132.93 105.511 ;
     RECT  2.415 105.511 133.038 105.629 ;
     RECT  32.976 105.629 120.258 105.725 ;
     RECT  32.976 105.725 113.67 105.737 ;
     RECT  114.408 105.725 120.258 105.773 ;
     RECT  32.976 105.737 113.598 105.809 ;
     RECT  32.976 105.809 113.562 105.899 ;
     RECT  120.996 105.629 133.038 106.007 ;
     RECT  32.976 105.899 113.526 106.205 ;
     RECT  121.176 106.007 133.038 106.321 ;
     RECT  121.176 106.321 133.29 106.475 ;
     RECT  2.415 105.629 32.238 106.519 ;
     RECT  32.976 106.205 41.67 106.519 ;
     RECT  42.444 106.205 113.526 106.547 ;
     RECT  114.516 105.773 120.258 106.555 ;
     RECT  114.516 106.555 120.294 106.717 ;
     RECT  110.34 106.547 113.526 106.733 ;
     RECT  42.444 106.547 109.602 106.745 ;
     RECT  114.408 106.717 120.294 106.753 ;
     RECT  121.176 106.475 132.894 106.753 ;
     RECT  42.444 106.745 109.494 106.817 ;
     RECT  110.376 106.733 113.526 106.861 ;
     RECT  114.408 106.753 132.894 106.861 ;
     RECT  110.376 106.861 132.894 106.979 ;
     RECT  2.415 106.519 41.67 107.051 ;
     RECT  44.1 106.817 109.494 107.051 ;
     RECT  44.1 107.051 109.422 107.087 ;
     RECT  110.376 106.979 113.598 107.117 ;
     RECT  2.415 107.051 9.558 107.123 ;
     RECT  112.356 107.117 113.598 107.123 ;
     RECT  10.332 107.051 41.67 107.159 ;
     RECT  77.832 107.087 109.422 107.159 ;
     RECT  114.372 106.979 132.894 107.159 ;
     RECT  114.372 107.159 118.134 107.165 ;
     RECT  27.936 107.159 41.67 107.179 ;
     RECT  27.936 107.179 41.706 107.221 ;
     RECT  42.444 106.817 43.326 107.221 ;
     RECT  2.415 107.123 6.642 107.249 ;
     RECT  7.56 107.123 9.558 107.249 ;
     RECT  10.332 107.159 27.162 107.249 ;
     RECT  44.1 107.087 57.186 107.249 ;
     RECT  58.284 107.087 76.914 107.249 ;
     RECT  77.832 107.159 109.35 107.249 ;
     RECT  112.356 107.123 113.562 107.249 ;
     RECT  114.624 107.165 118.134 107.249 ;
     RECT  4.356 107.249 6.642 107.285 ;
     RECT  27.936 107.221 43.326 107.285 ;
     RECT  44.1 107.249 49.698 107.285 ;
     RECT  58.464 107.249 74.862 107.285 ;
     RECT  85.824 107.249 95.418 107.285 ;
     RECT  4.572 107.285 6.462 107.321 ;
     RECT  10.512 107.249 27.162 107.321 ;
     RECT  50.94 107.249 57.186 107.321 ;
     RECT  61.488 107.285 74.862 107.321 ;
     RECT  4.572 107.321 6.102 107.357 ;
     RECT  77.832 107.249 85.086 107.357 ;
     RECT  85.824 107.285 94.914 107.357 ;
     RECT  96.372 107.249 109.35 107.357 ;
     RECT  110.376 107.117 111.618 107.357 ;
     RECT  114.624 107.249 118.062 107.357 ;
     RECT  4.572 107.357 5.922 107.393 ;
     RECT  10.512 107.321 27.018 107.393 ;
     RECT  27.936 107.285 38.79 107.393 ;
     RECT  61.488 107.321 69.534 107.393 ;
     RECT  92.916 107.357 94.914 107.393 ;
     RECT  96.372 107.357 106.506 107.393 ;
     RECT  118.98 107.159 132.894 107.393 ;
     RECT  122.292 107.393 132.894 107.401 ;
     RECT  82.656 107.357 85.086 107.405 ;
     RECT  10.512 107.393 24.498 107.429 ;
     RECT  25.56 107.393 27.018 107.429 ;
     RECT  63.648 107.393 69.534 107.429 ;
     RECT  75.636 107.249 76.878 107.429 ;
     RECT  97.992 107.393 106.506 107.429 ;
     RECT  2.415 107.249 3.438 107.519 ;
     RECT  10.512 107.429 21.402 107.519 ;
     RECT  25.596 107.429 27.018 107.519 ;
     RECT  27.936 107.393 29.79 107.519 ;
     RECT  30.528 107.393 38.79 107.519 ;
     RECT  39.6 107.285 43.326 107.519 ;
     RECT  44.172 107.285 48.006 107.519 ;
     RECT  48.744 107.285 49.698 107.519 ;
     RECT  51.015 107.321 57.186 107.519 ;
     RECT  58.464 107.285 60.714 107.519 ;
     RECT  61.488 107.393 62.73 107.519 ;
     RECT  69.372 107.429 69.534 107.519 ;
     RECT  70.272 107.321 74.862 107.519 ;
     RECT  75.636 107.429 76.698 107.519 ;
     RECT  77.832 107.357 81.918 107.519 ;
     RECT  82.656 107.405 85.05 107.519 ;
     RECT  85.824 107.357 92.142 107.519 ;
     RECT  92.916 107.393 94.497 107.519 ;
     RECT  96.372 107.393 97.146 107.519 ;
     RECT  98.1 107.429 106.506 107.519 ;
     RECT  107.388 107.357 109.35 107.519 ;
     RECT  114.696 107.357 118.062 107.519 ;
     RECT  118.98 107.393 121.497 107.519 ;
     RECT  122.292 107.401 133.038 107.519 ;
     RECT  82.656 107.519 84.906 107.549 ;
     RECT  98.136 107.519 106.506 107.549 ;
     RECT  108.9 107.519 109.35 107.549 ;
     RECT  4.572 107.393 5.778 107.555 ;
     RECT  7.776 107.249 9.558 107.555 ;
     RECT  10.512 107.519 13.497 107.555 ;
     RECT  16.092 107.519 19.494 107.555 ;
     RECT  20.34 107.519 21.402 107.555 ;
     RECT  26.676 107.519 27.018 107.555 ;
     RECT  30.528 107.519 31.158 107.555 ;
     RECT  48.744 107.519 48.762 107.555 ;
     RECT  53.496 107.519 53.874 107.555 ;
     RECT  54.72 107.519 55.53 107.555 ;
     RECT  58.464 107.519 58.482 107.555 ;
     RECT  59.328 107.519 60.714 107.555 ;
     RECT  61.488 107.519 62.298 107.555 ;
     RECT  63.648 107.429 68.634 107.555 ;
     RECT  69.372 107.519 69.39 107.555 ;
     RECT  70.272 107.519 70.47 107.555 ;
     RECT  75.636 107.519 75.654 107.555 ;
     RECT  77.904 107.519 80.982 107.555 ;
     RECT  82.656 107.549 84.618 107.555 ;
     RECT  85.932 107.519 86.346 107.555 ;
     RECT  87.12 107.519 90.738 107.555 ;
     RECT  98.136 107.549 106.47 107.555 ;
     RECT  107.388 107.519 107.658 107.555 ;
     RECT  110.376 107.357 111.258 107.555 ;
     RECT  119.16 107.519 120.15 107.555 ;
     RECT  122.292 107.519 124.866 107.555 ;
     RECT  127.872 107.519 129.978 107.555 ;
     RECT  12.78 107.555 13.497 107.591 ;
     RECT  16.092 107.555 16.578 107.591 ;
     RECT  17.748 107.555 19.494 107.591 ;
     RECT  26.748 107.555 27.018 107.591 ;
     RECT  27.936 107.519 29.697 107.591 ;
     RECT  30.636 107.555 31.158 107.591 ;
     RECT  55.476 107.555 55.53 107.591 ;
     RECT  60.228 107.555 60.714 107.591 ;
     RECT  78.015 107.555 80.982 107.591 ;
     RECT  88.776 107.555 90.738 107.591 ;
     RECT  93.636 107.519 94.497 107.591 ;
     RECT  101.052 107.555 104.274 107.591 ;
     RECT  108.936 107.549 109.35 107.591 ;
     RECT  114.804 107.519 118.062 107.591 ;
     RECT  123.876 107.555 124.866 107.591 ;
     RECT  127.872 107.555 127.89 107.591 ;
     RECT  128.7 107.555 129.978 107.591 ;
     RECT  16.56 107.591 16.578 107.597 ;
     RECT  25.596 107.519 25.866 107.597 ;
     RECT  31.968 107.519 38.79 107.597 ;
     RECT  112.392 107.249 113.562 107.597 ;
     RECT  125.604 107.519 126.897 107.597 ;
     RECT  4.68 107.555 5.778 107.627 ;
     RECT  26.892 107.591 26.91 107.627 ;
     RECT  28.116 107.591 28.458 107.627 ;
     RECT  31.968 107.597 35.586 107.627 ;
     RECT  44.172 107.519 47.61 107.627 ;
     RECT  60.3 107.591 60.462 107.627 ;
     RECT  78.015 107.591 79.29 107.627 ;
     RECT  81.72 107.519 81.846 107.627 ;
     RECT  83.34 107.555 84.618 107.627 ;
     RECT  90.072 107.591 90.738 107.627 ;
     RECT  110.415 107.555 111.15 107.627 ;
     RECT  112.392 107.597 113.418 107.627 ;
     RECT  125.784 107.597 126.897 107.627 ;
     RECT  129.204 107.591 129.978 107.627 ;
     RECT  130.788 107.519 132.894 107.627 ;
     RECT  22.248 107.429 24.498 107.645 ;
     RECT  28.44 107.627 28.458 107.645 ;
     RECT  2.415 107.519 3.294 107.663 ;
     RECT  12.852 107.591 13.497 107.663 ;
     RECT  18 107.591 19.494 107.663 ;
     RECT  39.6 107.519 40.842 107.663 ;
     RECT  41.796 107.519 43.326 107.663 ;
     RECT  55.476 107.591 55.494 107.663 ;
     RECT  64.728 107.555 67.497 107.663 ;
     RECT  78.015 107.627 79.002 107.663 ;
     RECT  80.136 107.591 80.226 107.663 ;
     RECT  81.72 107.627 81.738 107.663 ;
     RECT  88.776 107.591 89.298 107.663 ;
     RECT  122.724 107.555 122.958 107.663 ;
     RECT  123.876 107.591 124.614 107.663 ;
     RECT  131.436 107.627 132.786 107.663 ;
     RECT  44.604 107.627 47.61 107.693 ;
     RECT  71.856 107.519 74.862 107.693 ;
     RECT  91.656 107.519 92.106 107.693 ;
     RECT  7.815 107.555 9.558 107.699 ;
     RECT  10.512 107.555 12.006 107.699 ;
     RECT  18.072 107.663 19.494 107.699 ;
     RECT  22.788 107.645 24.498 107.699 ;
     RECT  25.596 107.597 25.614 107.699 ;
     RECT  30.672 107.591 31.158 107.699 ;
     RECT  31.968 107.627 31.986 107.699 ;
     RECT  32.832 107.627 35.586 107.699 ;
     RECT  36.756 107.597 38.79 107.699 ;
     RECT  39.672 107.663 40.842 107.699 ;
     RECT  41.796 107.663 43.254 107.699 ;
     RECT  44.964 107.693 47.61 107.699 ;
     RECT  51.015 107.519 52.578 107.699 ;
     RECT  56.415 107.519 57.186 107.699 ;
     RECT  60.3 107.627 60.426 107.699 ;
     RECT  64.728 107.663 65.718 107.699 ;
     RECT  68.544 107.555 68.634 107.699 ;
     RECT  71.856 107.693 71.874 107.699 ;
     RECT  72.615 107.693 74.862 107.699 ;
     RECT  80.136 107.663 80.154 107.699 ;
     RECT  80.964 107.591 80.982 107.699 ;
     RECT  85.968 107.555 86.346 107.699 ;
     RECT  90.72 107.627 90.738 107.699 ;
     RECT  91.656 107.693 91.746 107.699 ;
     RECT  94.068 107.591 94.497 107.699 ;
     RECT  96.372 107.519 97.11 107.699 ;
     RECT  98.136 107.555 98.874 107.699 ;
     RECT  101.736 107.591 104.274 107.699 ;
     RECT  110.415 107.627 111.042 107.699 ;
     RECT  117.216 107.591 118.062 107.699 ;
     RECT  121.104 107.519 121.497 107.699 ;
     RECT  122.724 107.663 122.742 107.699 ;
     RECT  123.876 107.663 124.47 107.699 ;
     RECT  125.784 107.627 125.802 107.699 ;
     RECT  129.204 107.627 129.402 107.699 ;
     RECT  131.436 107.663 132.297 107.699 ;
     RECT  2.415 107.663 2.697 107.747 ;
     RECT  13.14 107.663 13.497 107.747 ;
     RECT  22.788 107.699 24.297 107.747 ;
     RECT  29.415 107.591 29.697 107.747 ;
     RECT  45.615 107.699 45.897 107.747 ;
     RECT  56.415 107.699 56.697 107.747 ;
     RECT  61.815 107.555 62.097 107.747 ;
     RECT  66.492 107.663 67.497 107.747 ;
     RECT  72.615 107.699 74.826 107.747 ;
     RECT  78.015 107.663 78.297 107.747 ;
     RECT  88.776 107.663 89.097 107.747 ;
     RECT  94.215 107.699 94.497 107.747 ;
     RECT  99.615 107.555 99.897 107.747 ;
     RECT  105.015 107.555 106.47 107.747 ;
     RECT  110.415 107.699 110.697 107.747 ;
     RECT  114.948 107.591 116.097 107.747 ;
     RECT  121.215 107.699 121.497 107.747 ;
     RECT  126.615 107.627 126.897 107.747 ;
     RECT  131.472 107.699 132.297 107.747 ;
     RECT  4.68 107.627 5.31 107.789 ;
     RECT  7.815 107.699 8.874 107.789 ;
     RECT  10.512 107.699 11.466 107.789 ;
     RECT  20.448 107.555 21.402 107.789 ;
     RECT  22.788 107.747 24.105 107.789 ;
     RECT  30.924 107.699 31.158 107.789 ;
     RECT  33.192 107.699 35.586 107.789 ;
     RECT  36.756 107.699 37.998 107.789 ;
     RECT  38.772 107.699 38.79 107.789 ;
     RECT  39.888 107.699 40.842 107.789 ;
     RECT  42.084 107.699 42.21 107.789 ;
     RECT  46.62 107.699 46.818 107.789 ;
     RECT  47.592 107.699 47.61 107.789 ;
     RECT  51.015 107.699 52.038 107.789 ;
     RECT  53.532 107.555 53.874 107.789 ;
     RECT  59.328 107.555 59.454 107.789 ;
     RECT  63.648 107.555 63.918 107.789 ;
     RECT  64.728 107.699 64.746 107.789 ;
     RECT  65.556 107.699 65.718 107.789 ;
     RECT  66.492 107.747 67.305 107.789 ;
     RECT  73.44 107.747 74.826 107.789 ;
     RECT  83.376 107.627 84.114 107.789 ;
     RECT  86.184 107.699 86.346 107.789 ;
     RECT  87.12 107.555 87.822 107.789 ;
     RECT  101.736 107.699 103.698 107.789 ;
     RECT  105.912 107.747 106.47 107.789 ;
     RECT  108.972 107.591 109.35 107.789 ;
     RECT  112.572 107.627 113.418 107.789 ;
     RECT  114.948 107.747 115.905 107.789 ;
     RECT  117.216 107.699 117.918 107.789 ;
     RECT  119.16 107.555 119.826 107.789 ;
     RECT  10.512 107.789 10.53 107.825 ;
     RECT  13.14 107.747 13.374 107.825 ;
     RECT  18.615 107.699 19.494 107.825 ;
     RECT  20.448 107.789 20.97 107.825 ;
     RECT  31.068 107.789 31.158 107.825 ;
     RECT  33.192 107.789 33.858 107.825 ;
     RECT  36.756 107.789 36.774 107.825 ;
     RECT  37.836 107.789 37.854 107.825 ;
     RECT  39.888 107.789 40.305 107.825 ;
     RECT  42.192 107.789 42.21 107.825 ;
     RECT  46.62 107.789 46.638 107.825 ;
     RECT  53.64 107.789 53.73 107.825 ;
     RECT  59.328 107.789 59.418 107.825 ;
     RECT  63.648 107.789 63.666 107.825 ;
     RECT  70.272 107.555 70.326 107.825 ;
     RECT  96.372 107.699 97.074 107.825 ;
     RECT  101.736 107.789 102.654 107.825 ;
     RECT  106.128 107.789 106.47 107.825 ;
     RECT  114.948 107.789 114.966 107.825 ;
     RECT  117.216 107.789 117.234 107.825 ;
     RECT  119.16 107.789 119.178 107.825 ;
     RECT  131.472 107.747 132.105 107.825 ;
     RECT  4.752 107.789 5.31 107.861 ;
     RECT  7.815 107.789 8.586 107.861 ;
     RECT  18.615 107.825 19.422 107.861 ;
     RECT  53.712 107.825 53.73 107.861 ;
     RECT  59.4 107.825 59.418 107.861 ;
     RECT  88.776 107.747 88.905 107.861 ;
     RECT  96.516 107.825 97.074 107.861 ;
     RECT  106.128 107.825 106.398 107.861 ;
     RECT  5.076 107.861 5.31 107.897 ;
     RECT  14.724 107.519 14.958 107.897 ;
     RECT  20.952 107.825 20.97 107.897 ;
     RECT  31.068 107.825 31.086 107.897 ;
     RECT  70.308 107.825 70.326 107.897 ;
     RECT  96.516 107.861 96.966 107.897 ;
     RECT  5.292 107.897 5.31 107.933 ;
     RECT  13.14 107.825 13.338 107.933 ;
     RECT  34.815 107.789 35.586 107.933 ;
     RECT  43.056 107.699 43.074 107.933 ;
     RECT  74.808 107.789 74.826 107.933 ;
     RECT  101.88 107.825 102.402 107.933 ;
     RECT  106.128 107.861 106.29 107.933 ;
     RECT  109.332 107.789 109.35 107.933 ;
     RECT  18.615 107.861 19.242 107.969 ;
     RECT  60.408 107.699 60.426 107.969 ;
     RECT  96.516 107.897 96.534 107.969 ;
     RECT  103.68 107.789 103.698 107.969 ;
     RECT  112.644 107.789 113.418 107.969 ;
     RECT  123.876 107.699 124.182 107.969 ;
     RECT  2.415 107.747 2.505 108.017 ;
     RECT  7.815 107.861 7.905 108.017 ;
     RECT  13.14 107.933 13.305 108.017 ;
     RECT  18.615 107.969 18.705 108.017 ;
     RECT  24.015 107.789 24.105 108.017 ;
     RECT  29.415 107.747 29.505 108.017 ;
     RECT  34.815 107.933 34.905 108.017 ;
     RECT  40.215 107.825 40.305 108.017 ;
     RECT  45.615 107.747 45.705 108.017 ;
     RECT  51.015 107.789 51.105 108.017 ;
     RECT  56.415 107.747 56.505 108.017 ;
     RECT  61.815 107.747 61.905 108.017 ;
     RECT  67.215 107.789 67.305 108.017 ;
     RECT  72.615 107.747 72.705 108.017 ;
     RECT  78.015 107.747 78.105 108.017 ;
     RECT  83.415 107.789 83.505 108.017 ;
     RECT  88.815 107.861 88.905 108.017 ;
     RECT  94.215 107.747 94.305 108.017 ;
     RECT  99.615 107.747 99.705 108.017 ;
     RECT  105.015 107.747 105.105 108.017 ;
     RECT  110.415 107.747 110.505 108.017 ;
     RECT  115.815 107.789 115.905 108.017 ;
     RECT  121.215 107.747 121.305 108.017 ;
     RECT  126.615 107.747 126.705 108.017 ;
     RECT  132.015 107.825 132.105 108.017 ;
     RECT  13.14 108.017 13.158 108.059 ;
     RECT  14.94 107.897 14.958 108.059 ;
    LAYER M4 ;
     RECT  0.06 52.224 0.061 53.736 ;
     RECT  0.061 52.224 0.133 53.832 ;
     RECT  0.06 68.256 0.169 69.624 ;
     RECT  0.169 68.16 1.105 69.624 ;
     RECT  2.185 21.456 2.245 21.48 ;
     RECT  1.393 82.224 2.245 82.248 ;
     RECT  2.149 83.232 2.245 83.256 ;
     RECT  2.185 23.856 2.293 23.88 ;
     RECT  0.133 51.168 2.293 53.832 ;
     RECT  2.245 20.976 2.329 21.48 ;
     RECT  2.293 6.816 2.408 6.84 ;
     RECT  2.293 10.416 2.408 10.44 ;
     RECT  2.245 19.44 2.408 19.464 ;
     RECT  2.329 20.976 2.408 21.96 ;
     RECT  2.293 23.664 2.408 23.88 ;
     RECT  2.293 27.312 2.408 27.336 ;
     RECT  2.293 37.68 2.408 37.704 ;
     RECT  0.205 39.216 2.408 39.24 ;
     RECT  2.293 40.704 2.408 40.728 ;
     RECT  0.853 41.952 2.408 41.976 ;
     RECT  2.293 46.656 2.408 46.68 ;
     RECT  2.293 51.072 2.408 53.832 ;
     RECT  2.293 57.6 2.408 57.624 ;
     RECT  2.293 65.52 2.408 65.544 ;
     RECT  1.105 68.16 2.408 69.768 ;
     RECT  2.245 82.224 2.408 83.256 ;
     RECT  2.293 85.104 2.408 85.128 ;
     RECT  2.329 87.264 2.408 87.288 ;
     RECT  2.293 88.368 2.408 88.392 ;
     RECT  2.293 89.52 2.408 89.544 ;
     RECT  2.245 90.528 2.408 90.552 ;
     RECT  2.293 91.872 2.408 92.664 ;
     RECT  2.245 98.064 2.408 98.088 ;
     RECT  2.293 100.224 2.408 100.248 ;
     RECT  2.293 102.096 2.408 102.12 ;
     RECT  2.408 2.148 2.512 108.012 ;
     RECT  2.512 2.418 2.704 107.742 ;
     RECT  2.704 2.832 2.819 6.552 ;
     RECT  2.704 19.92 2.819 22.2 ;
     RECT  2.704 35.952 2.819 49.512 ;
     RECT  2.704 85.92 2.819 99.768 ;
     RECT  2.704 106.704 2.819 107.208 ;
     RECT  2.819 2.88 2.867 6.552 ;
     RECT  2.819 45.984 2.867 49.512 ;
     RECT  2.704 56.784 2.867 60.168 ;
     RECT  2.819 96.672 2.867 99.768 ;
     RECT  2.704 102.624 2.867 105.48 ;
     RECT  2.819 19.92 2.909 21.96 ;
     RECT  2.704 8.88 2.915 14.856 ;
     RECT  2.704 15.984 2.915 18.6 ;
     RECT  2.909 19.92 2.915 21.528 ;
     RECT  2.867 96.672 2.963 97.56 ;
     RECT  2.704 23.904 3.011 34.824 ;
     RECT  2.963 96.864 3.011 97.56 ;
     RECT  2.867 98.592 3.011 99.768 ;
     RECT  2.867 102.624 3.011 105.144 ;
     RECT  2.915 8.88 3.059 13.416 ;
     RECT  2.915 19.968 3.059 21.528 ;
     RECT  3.059 9.6 3.107 13.416 ;
     RECT  3.059 19.968 3.107 21.48 ;
     RECT  2.704 72.336 3.107 84.936 ;
     RECT  3.107 72.336 3.125 79.032 ;
     RECT  2.915 16.032 3.155 18.6 ;
     RECT  3.011 24.864 3.203 34.824 ;
     RECT  2.704 101.28 3.299 101.304 ;
     RECT  2.819 107.184 3.299 107.208 ;
     RECT  3.011 102.624 3.377 102.84 ;
     RECT  2.867 56.784 3.395 58.776 ;
     RECT  3.125 72.336 3.395 76.824 ;
     RECT  2.819 85.92 3.395 95.448 ;
     RECT  3.377 102.816 3.395 102.84 ;
     RECT  3.011 96.96 3.413 97.56 ;
     RECT  2.867 4.512 3.485 6.552 ;
     RECT  2.819 35.952 3.521 44.808 ;
     RECT  2.704 61.968 3.521 63.816 ;
     RECT  3.011 103.872 3.521 105.144 ;
     RECT  3.485 4.512 3.635 4.68 ;
     RECT  2.704 50.736 3.635 53.928 ;
     RECT  3.395 57.84 3.731 58.776 ;
     RECT  3.203 28.992 3.733 34.824 ;
     RECT  3.395 85.92 3.737 86.712 ;
     RECT  3.521 61.968 3.769 62.184 ;
     RECT  3.635 50.928 3.805 53.928 ;
     RECT  3.155 16.032 3.809 18.072 ;
     RECT  3.809 18.048 3.827 18.072 ;
     RECT  2.867 60.144 3.827 60.168 ;
     RECT  2.867 45.984 3.841 49.464 ;
     RECT  3.395 87.792 3.841 95.448 ;
     RECT  3.521 63.264 3.845 63.816 ;
     RECT  3.805 7.632 3.875 7.944 ;
     RECT  3.845 63.792 3.875 63.816 ;
     RECT  3.841 45.792 3.881 49.464 ;
     RECT  2.915 14.736 3.913 14.856 ;
     RECT  3.809 16.032 3.913 16.968 ;
     RECT  3.107 80.016 3.913 84.936 ;
     RECT  3.881 45.792 3.917 47.112 ;
     RECT  3.395 72.864 3.917 76.824 ;
     RECT  3.841 87.792 3.923 95.688 ;
     RECT  3.917 45.792 3.925 46.824 ;
     RECT  3.485 5.664 3.953 6.552 ;
     RECT  3.805 23.52 3.971 23.544 ;
     RECT  3.805 50.928 3.971 54.36 ;
     RECT  3.923 91.584 3.973 95.688 ;
     RECT  3.203 24.864 3.985 27.912 ;
     RECT  2.704 64.944 3.985 71.16 ;
     RECT  3.521 103.872 3.985 103.896 ;
     RECT  3.107 9.6 3.989 11.976 ;
     RECT  3.107 20.016 4.021 21.48 ;
     RECT  3.881 48.144 4.021 49.464 ;
     RECT  3.011 98.592 4.021 98.616 ;
     RECT  3.011 99.696 4.021 99.768 ;
     RECT  3.917 73.68 4.025 76.824 ;
     RECT  3.985 64.752 4.067 71.16 ;
     RECT  3.985 103.2 4.067 103.896 ;
     RECT  3.125 77.904 4.069 79.032 ;
     RECT  3.913 80.016 4.069 85.512 ;
     RECT  4.025 73.872 4.097 76.824 ;
     RECT  3.395 56.784 4.129 56.808 ;
     RECT  4.021 98.592 4.129 101.16 ;
     RECT  4.097 74.544 4.169 76.824 ;
     RECT  3.923 87.792 4.169 90.504 ;
     RECT  3.953 6.528 4.201 6.552 ;
     RECT  4.021 20.016 4.201 21.816 ;
     RECT  4.093 22.8 4.201 23.304 ;
     RECT  4.201 6.528 4.237 6.6 ;
     RECT  3.875 7.632 4.237 7.656 ;
     RECT  3.973 91.584 4.237 95.784 ;
     RECT  3.413 96.96 4.237 97.368 ;
     RECT  3.521 104.88 4.237 105.144 ;
     RECT  4.129 98.4 4.261 101.16 ;
     RECT  4.237 6.528 4.307 7.656 ;
     RECT  4.237 91.584 4.307 97.368 ;
     RECT  4.237 104.88 4.307 105.768 ;
     RECT  3.913 55.392 4.309 55.416 ;
     RECT  4.129 56.688 4.309 56.808 ;
     RECT  4.261 98.4 4.313 101.592 ;
     RECT  3.989 9.648 4.345 11.976 ;
     RECT  3.107 13.104 4.345 13.416 ;
     RECT  3.731 58.704 4.381 58.776 ;
     RECT  4.169 74.592 4.405 76.824 ;
     RECT  4.069 77.904 4.405 85.512 ;
     RECT  4.309 55.392 4.453 56.808 ;
     RECT  3.737 86.64 4.453 86.712 ;
     RECT  4.169 87.792 4.453 90.36 ;
     RECT  4.201 20.016 4.457 23.304 ;
     RECT  3.985 24.528 4.489 27.912 ;
     RECT  3.521 36.336 4.489 44.52 ;
     RECT  3.925 45.552 4.489 46.824 ;
     RECT  4.453 54.672 4.493 57.336 ;
     RECT  4.457 20.016 4.499 22.776 ;
     RECT  4.417 102.816 4.499 102.84 ;
     RECT  4.499 20.016 4.501 22.728 ;
     RECT  4.067 65.568 4.525 71.16 ;
     RECT  4.345 107.184 4.525 107.208 ;
     RECT  4.489 72.672 4.547 72.696 ;
     RECT  4.307 7.632 4.601 7.656 ;
     RECT  4.489 24.528 4.633 27.96 ;
     RECT  3.733 28.992 4.633 35.16 ;
     RECT  3.769 61.68 4.633 62.184 ;
     RECT  4.213 18.192 4.669 18.216 ;
     RECT  4.633 24.528 4.669 35.16 ;
     RECT  4.669 24.336 4.691 35.16 ;
     RECT  4.669 18.192 4.693 18.696 ;
     RECT  4.501 19.728 4.693 22.728 ;
     RECT  4.067 103.872 4.693 103.896 ;
     RECT  4.307 104.88 4.693 105.192 ;
     RECT  2.867 2.88 4.705 3.384 ;
     RECT  4.405 74.592 4.705 85.512 ;
     RECT  4.453 86.64 4.705 90.36 ;
     RECT  4.345 9.648 4.709 13.416 ;
     RECT  4.691 24.336 4.739 28.008 ;
     RECT  4.693 103.872 4.787 105.192 ;
     RECT  4.493 56.304 4.813 57.336 ;
     RECT  4.691 28.992 4.837 35.16 ;
     RECT  4.709 10.272 4.885 13.416 ;
     RECT  3.913 14.736 4.885 16.968 ;
     RECT  4.489 36.336 4.921 46.824 ;
     RECT  4.021 48.144 4.921 49.608 ;
     RECT  4.381 58.704 4.921 58.872 ;
     RECT  4.525 65.568 4.933 71.208 ;
     RECT  4.789 72.576 4.933 72.6 ;
     RECT  4.705 2.832 4.957 3.384 ;
     RECT  4.849 102.432 4.961 102.456 ;
     RECT  4.921 36.336 4.979 49.608 ;
     RECT  4.921 58.704 4.979 59.832 ;
     RECT  3.635 4.656 4.981 4.68 ;
     RECT  4.981 4.656 4.993 5.448 ;
     RECT  4.307 6.528 4.993 6.6 ;
     RECT  4.957 2.832 5.027 3.432 ;
     RECT  4.885 10.272 5.029 17.208 ;
     RECT  4.693 18.192 5.029 22.728 ;
     RECT  4.813 56.304 5.029 57.432 ;
     RECT  4.979 58.704 5.029 58.872 ;
     RECT  4.633 61.248 5.029 62.184 ;
     RECT  4.885 63.216 5.029 63.24 ;
     RECT  4.307 91.584 5.033 95.928 ;
     RECT  4.979 47.328 5.065 49.608 ;
     RECT  4.993 8.304 5.075 8.328 ;
     RECT  5.029 10.272 5.075 22.728 ;
     RECT  5.033 91.584 5.077 95.688 ;
     RECT  4.313 98.4 5.137 101.16 ;
     RECT  4.787 103.872 5.137 103.896 ;
     RECT  5.029 56.304 5.141 58.872 ;
     RECT  5.029 61.248 5.141 63.24 ;
     RECT  4.837 28.992 5.209 35.352 ;
     RECT  4.979 36.336 5.209 46.056 ;
     RECT  5.141 61.968 5.245 63.24 ;
     RECT  4.705 74.592 5.245 90.36 ;
     RECT  5.077 91.392 5.245 95.688 ;
     RECT  4.525 106.176 5.245 107.208 ;
     RECT  4.739 24.528 5.249 28.008 ;
     RECT  5.065 47.328 5.267 49.944 ;
     RECT  5.137 98.352 5.267 101.16 ;
     RECT  4.787 104.88 5.267 105.192 ;
     RECT  5.267 47.424 5.317 49.944 ;
     RECT  3.971 50.928 5.317 53.592 ;
     RECT  5.245 74.592 5.317 95.688 ;
     RECT  4.307 97.2 5.317 97.368 ;
     RECT  5.267 98.352 5.317 99.528 ;
     RECT  5.249 24.528 5.357 27.96 ;
     RECT  5.245 61.968 5.357 63.672 ;
     RECT  5.317 47.424 5.425 53.592 ;
     RECT  4.493 54.672 5.425 55.272 ;
     RECT  4.933 65.568 5.425 72.6 ;
     RECT  5.317 97.2 5.425 99.528 ;
     RECT  5.075 14.928 5.429 22.728 ;
     RECT  5.425 97.056 5.461 99.528 ;
     RECT  4.993 4.656 5.507 6.6 ;
     RECT  5.425 47.424 5.537 55.272 ;
     RECT  5.267 104.88 5.537 105.144 ;
     RECT  5.461 60.672 5.603 60.984 ;
     RECT  5.537 54.672 5.605 55.272 ;
     RECT  5.141 56.304 5.605 58.728 ;
     RECT  5.507 4.656 5.641 4.68 ;
     RECT  5.267 100.608 5.677 101.16 ;
     RECT  5.075 10.272 5.713 13.416 ;
     RECT  5.209 28.992 5.713 46.056 ;
     RECT  5.425 64.656 5.713 72.6 ;
     RECT  5.507 5.712 5.749 6.6 ;
     RECT  5.101 8.448 5.749 8.568 ;
     RECT  5.713 9.696 5.749 13.416 ;
     RECT  5.713 28.944 5.753 46.056 ;
     RECT  5.245 106.176 5.753 107.4 ;
     RECT  5.429 19.728 5.785 22.728 ;
     RECT  5.137 103.488 5.785 103.896 ;
     RECT  5.537 104.88 5.785 104.952 ;
     RECT  5.753 28.944 5.795 43.08 ;
     RECT  5.357 62.4 5.821 63.672 ;
     RECT  5.713 64.656 5.821 72.696 ;
     RECT  5.749 8.448 5.825 13.416 ;
     RECT  5.785 19.728 5.845 23.352 ;
     RECT  5.357 24.528 5.845 27.864 ;
     RECT  5.825 8.448 5.861 8.568 ;
     RECT  5.317 74.448 5.897 95.688 ;
     RECT  5.845 102.384 5.897 102.408 ;
     RECT  5.753 106.176 5.897 107.208 ;
     RECT  5.027 2.832 5.929 3.384 ;
     RECT  5.749 5.712 5.929 6.648 ;
     RECT  5.897 74.448 5.941 89.496 ;
     RECT  5.461 96.96 5.965 99.528 ;
     RECT  5.929 2.688 5.987 3.384 ;
     RECT  5.821 62.4 6.109 72.696 ;
     RECT  5.929 5.712 6.145 7.224 ;
     RECT  5.861 8.448 6.145 8.52 ;
     RECT  5.605 54.672 6.181 58.728 ;
     RECT  5.753 45.12 6.257 46.056 ;
     RECT  5.825 9.6 6.289 13.416 ;
     RECT  5.429 14.928 6.289 18.168 ;
     RECT  6.181 54.672 6.289 59.352 ;
     RECT  6.109 62.4 6.289 72.936 ;
     RECT  5.941 74.016 6.289 89.496 ;
     RECT  5.537 47.424 6.325 53.592 ;
     RECT  5.845 19.728 6.361 27.864 ;
     RECT  5.795 28.944 6.361 41.784 ;
     RECT  6.257 45.168 6.397 46.056 ;
     RECT  5.897 106.176 6.401 106.2 ;
     RECT  6.289 14.784 6.433 18.168 ;
     RECT  6.289 9.6 6.437 13.464 ;
     RECT  5.965 96.72 6.469 99.528 ;
     RECT  5.677 100.608 6.469 101.4 ;
     RECT  5.641 4.512 6.541 4.68 ;
     RECT  6.145 5.712 6.541 8.52 ;
     RECT  6.505 61.344 6.541 61.368 ;
     RECT  6.289 62.4 6.541 89.496 ;
     RECT  6.469 96.72 6.563 101.4 ;
     RECT  6.437 10.128 6.577 13.464 ;
     RECT  6.433 14.496 6.577 18.168 ;
     RECT  6.361 19.728 6.577 41.784 ;
     RECT  5.897 90.48 6.577 95.688 ;
     RECT  6.563 96.72 6.577 99.576 ;
     RECT  6.289 54.672 6.617 60.072 ;
     RECT  5.987 2.784 6.653 3.384 ;
     RECT  5.897 107.184 6.653 107.208 ;
     RECT  6.577 10.128 6.659 41.784 ;
     RECT  6.325 47.136 6.685 53.592 ;
     RECT  6.617 54.672 6.685 59.832 ;
     RECT  5.785 103.488 6.721 104.952 ;
     RECT  6.659 10.128 6.725 18.84 ;
     RECT  6.653 3.024 6.829 3.384 ;
     RECT  6.829 3.024 6.937 3.432 ;
     RECT  6.541 4.512 6.937 8.52 ;
     RECT  6.721 102.624 6.937 104.952 ;
     RECT  6.829 106.032 6.937 106.056 ;
     RECT  6.659 19.824 6.973 41.784 ;
     RECT  5.795 42.816 6.973 43.08 ;
     RECT  6.937 44.064 6.973 44.088 ;
     RECT  6.397 45.168 6.973 46.152 ;
     RECT  6.685 47.136 6.973 59.832 ;
     RECT  6.937 102.624 7.093 106.056 ;
     RECT  6.563 100.608 7.261 101.4 ;
     RECT  6.541 61.344 7.369 89.496 ;
     RECT  6.577 90.48 7.369 99.576 ;
     RECT  7.369 61.344 7.549 99.576 ;
     RECT  7.549 60.864 7.573 99.576 ;
     RECT  7.261 100.608 7.573 101.448 ;
     RECT  6.973 19.824 7.585 44.088 ;
     RECT  6.973 45.168 7.585 59.832 ;
     RECT  7.573 60.864 7.621 101.448 ;
     RECT  7.093 102.432 7.621 106.056 ;
     RECT  6.725 10.128 7.669 18.216 ;
     RECT  6.937 3.024 7.808 8.52 ;
     RECT  7.669 9.6 7.808 18.216 ;
     RECT  7.585 19.824 7.808 59.832 ;
     RECT  7.621 60.864 7.808 106.056 ;
     RECT  7.808 2.148 7.912 108.012 ;
     RECT  7.912 2.4 8.104 107.742 ;
     RECT  8.104 60.672 8.243 107.256 ;
     RECT  8.104 2.4 8.561 8.52 ;
     RECT  8.561 6.048 9.277 8.52 ;
     RECT  8.104 9.552 9.277 59.592 ;
     RECT  8.243 60.672 9.349 107.016 ;
     RECT  9.349 60.672 9.425 107.208 ;
     RECT  8.561 2.4 9.601 4.728 ;
     RECT  9.277 6.048 9.601 59.592 ;
     RECT  9.425 60.672 9.713 107.016 ;
     RECT  9.601 2.4 10.213 59.592 ;
     RECT  9.713 60.672 10.213 104.376 ;
     RECT  10.213 2.4 10.357 104.376 ;
     RECT  9.713 105.408 10.501 107.016 ;
     RECT  10.501 105.408 10.691 107.784 ;
     RECT  10.357 2.304 10.753 104.376 ;
     RECT  10.691 105.408 10.753 107.352 ;
     RECT  11.401 1.152 11.689 1.176 ;
     RECT  10.753 2.304 11.689 107.352 ;
     RECT  11.545 0.144 11.761 0.168 ;
     RECT  11.689 1.152 11.761 107.352 ;
     RECT  11.761 0.144 11.905 107.352 ;
     RECT  11.905 0.144 13.091 107.64 ;
     RECT  13.091 1.728 13.205 107.64 ;
     RECT  13.205 1.824 13.208 107.64 ;
     RECT  13.208 1.824 13.312 108.012 ;
     RECT  13.312 1.824 13.385 107.742 ;
     RECT  13.091 0.144 13.429 0.312 ;
     RECT  13.385 1.92 13.504 107.742 ;
     RECT  13.504 1.92 13.619 107.64 ;
     RECT  13.429 0.048 13.667 0.312 ;
     RECT  13.667 0.048 13.709 0.216 ;
     RECT  13.619 2.064 14.681 107.64 ;
     RECT  14.681 103.296 14.969 107.64 ;
     RECT  14.681 2.064 15.757 102.12 ;
     RECT  15.757 2.064 16.117 102.264 ;
     RECT  14.969 103.44 16.117 107.64 ;
     RECT  16.117 2.064 18.608 107.64 ;
     RECT  18.608 2.064 18.712 108.012 ;
     RECT  18.712 2.064 18.904 107.742 ;
     RECT  18.904 2.064 19.379 107.592 ;
     RECT  19.379 2.064 19.397 101.16 ;
     RECT  19.379 102.144 19.721 107.592 ;
     RECT  19.397 2.256 20.045 101.16 ;
     RECT  20.045 2.256 20.339 100.632 ;
     RECT  19.721 102.192 20.437 107.592 ;
     RECT  20.437 102.192 20.627 107.784 ;
     RECT  20.627 102.192 20.689 107.592 ;
     RECT  20.339 2.448 21.049 100.632 ;
     RECT  20.689 101.616 21.049 107.592 ;
     RECT  21.049 2.448 22.237 107.592 ;
     RECT  22.237 2.448 22.261 107.64 ;
     RECT  22.261 2.064 22.741 107.64 ;
     RECT  22.741 2.064 22.817 107.784 ;
     RECT  22.817 2.064 24.008 107.64 ;
     RECT  24.008 2.064 24.112 108.012 ;
     RECT  24.112 2.064 24.304 107.742 ;
     RECT  24.304 2.064 24.833 107.64 ;
     RECT  13.709 0.048 24.941 0.072 ;
     RECT  24.833 2.064 25.837 100.344 ;
     RECT  24.833 101.328 25.837 107.64 ;
     RECT  25.837 2.064 29.408 107.64 ;
     RECT  29.408 2.064 29.512 108.012 ;
     RECT  29.512 2.064 29.704 107.742 ;
     RECT  29.704 2.064 30.913 107.64 ;
     RECT  30.913 2.064 30.995 107.784 ;
     RECT  30.995 2.064 31.043 107.208 ;
     RECT  31.043 2.064 31.745 107.016 ;
     RECT  31.745 106.56 32.029 107.016 ;
     RECT  31.745 2.064 32.929 105.192 ;
     RECT  32.029 106.56 32.929 107.352 ;
     RECT  32.929 2.064 33.829 107.352 ;
     RECT  33.829 2.064 34.808 107.784 ;
     RECT  34.808 2.064 34.912 108.012 ;
     RECT  34.912 2.064 35.104 107.742 ;
     RECT  35.104 2.064 35.345 107.592 ;
     RECT  35.345 105.408 36.745 107.592 ;
     RECT  36.745 105.408 36.803 107.784 ;
     RECT  35.345 2.064 36.961 104.376 ;
     RECT  36.803 105.408 36.961 107.688 ;
     RECT  36.961 2.064 37.649 107.688 ;
     RECT  37.649 103.536 37.825 107.688 ;
     RECT  37.825 103.536 38.081 107.784 ;
     RECT  38.081 103.536 38.261 105.576 ;
     RECT  38.261 103.536 38.513 105.528 ;
     RECT  38.081 106.56 38.627 107.784 ;
     RECT  37.649 2.064 38.761 102.504 ;
     RECT  38.513 103.536 38.761 105.432 ;
     RECT  38.761 2.064 39.517 105.432 ;
     RECT  38.627 106.56 39.517 107.112 ;
     RECT  39.517 2.064 39.589 107.112 ;
     RECT  39.589 2.064 39.661 107.64 ;
     RECT  39.661 2.064 39.733 107.688 ;
     RECT  39.733 2.064 40.208 107.784 ;
     RECT  40.208 2.064 40.312 108.012 ;
     RECT  40.312 2.064 40.504 107.742 ;
     RECT  40.504 107.52 41.533 107.688 ;
     RECT  41.533 107.328 41.677 107.688 ;
     RECT  40.504 2.064 41.893 105.672 ;
     RECT  41.677 107.184 42.433 107.688 ;
     RECT  41.893 2.064 42.541 105.816 ;
     RECT  42.433 106.944 42.541 107.688 ;
     RECT  42.541 2.064 42.851 107.688 ;
     RECT  42.851 106.272 43.265 107.688 ;
     RECT  43.265 106.272 43.337 107.64 ;
     RECT  42.851 2.064 43.733 105.24 ;
     RECT  43.733 103.296 43.861 105.24 ;
     RECT  43.337 106.272 43.861 107.208 ;
     RECT  43.861 103.296 44.021 107.208 ;
     RECT  44.021 103.488 44.057 107.208 ;
     RECT  43.733 2.064 44.165 102.168 ;
     RECT  44.057 104.016 44.485 107.208 ;
     RECT  44.485 104.016 44.557 107.4 ;
     RECT  44.557 104.016 44.593 107.544 ;
     RECT  44.593 104.016 45.457 107.688 ;
     RECT  44.165 2.064 45.608 102.12 ;
     RECT  45.457 103.824 45.608 107.688 ;
     RECT  45.608 2.064 45.712 108.012 ;
     RECT  45.712 2.064 45.904 107.784 ;
     RECT  45.904 2.064 46.289 105.24 ;
     RECT  46.289 104.544 46.361 105.24 ;
     RECT  45.904 106.272 46.649 107.784 ;
     RECT  46.361 104.592 46.933 105.24 ;
     RECT  46.649 106.272 46.933 107.208 ;
     RECT  46.933 104.592 47.507 107.208 ;
     RECT  47.507 104.592 47.513 107.16 ;
     RECT  47.513 104.592 47.555 105.48 ;
     RECT  47.555 104.592 47.617 105.24 ;
     RECT  46.289 2.064 47.725 103.32 ;
     RECT  47.725 2.064 47.797 103.464 ;
     RECT  47.617 104.448 47.797 105.24 ;
     RECT  47.513 106.656 48.517 107.16 ;
     RECT  48.517 106.656 48.733 107.208 ;
     RECT  48.733 106.656 48.805 107.4 ;
     RECT  47.797 2.064 48.809 105.24 ;
     RECT  48.809 104.016 49.129 105.24 ;
     RECT  48.805 106.608 49.129 107.4 ;
     RECT  49.129 104.016 49.637 107.4 ;
     RECT  48.809 2.064 49.777 102.648 ;
     RECT  49.637 104.016 49.777 107.16 ;
     RECT  49.777 2.064 49.781 107.16 ;
     RECT  49.781 2.064 51.001 105.96 ;
     RECT  49.781 107.04 51.001 107.064 ;
     RECT  51.001 2.064 51.008 107.064 ;
     RECT  51.008 2.064 51.112 108.012 ;
     RECT  51.112 2.064 51.587 107.832 ;
     RECT  51.587 2.064 51.779 107.208 ;
     RECT  51.779 2.064 51.833 107.064 ;
     RECT  51.833 2.064 52.801 105.672 ;
     RECT  51.833 106.704 52.801 107.064 ;
     RECT  52.801 2.064 53.485 107.064 ;
     RECT  53.485 2.064 53.603 107.208 ;
     RECT  53.603 2.064 55.141 107.064 ;
     RECT  55.141 2.064 55.645 107.112 ;
     RECT  55.645 2.064 56.408 107.208 ;
     RECT  56.408 2.064 56.512 108.012 ;
     RECT  56.512 2.064 56.704 107.742 ;
     RECT  56.704 2.064 58.019 107.304 ;
     RECT  58.019 2.064 60.293 107.256 ;
     RECT  60.293 3.168 60.397 107.256 ;
     RECT  60.293 2.064 61.441 2.088 ;
     RECT  60.397 3.168 61.441 107.88 ;
     RECT  61.441 2.064 61.808 107.88 ;
     RECT  61.808 2.064 61.912 108.012 ;
     RECT  61.912 2.064 65.945 107.88 ;
     RECT  65.945 2.064 67.208 2.088 ;
     RECT  65.945 3.12 67.208 107.88 ;
     RECT  67.208 2.064 67.312 108.012 ;
     RECT  67.312 2.064 67.673 107.88 ;
     RECT  67.673 3.12 67.745 107.88 ;
     RECT  67.745 3.168 67.763 107.88 ;
     RECT  67.763 3.168 68.141 107.688 ;
     RECT  67.673 2.064 69.061 2.088 ;
     RECT  68.141 3.168 69.061 104.664 ;
     RECT  69.061 2.064 69.113 104.664 ;
     RECT  69.113 3.168 69.217 104.664 ;
     RECT  68.141 106.032 69.217 107.688 ;
     RECT  69.217 3.168 70.549 107.688 ;
     RECT  69.113 2.064 71.557 2.088 ;
     RECT  70.549 3.12 71.557 107.688 ;
     RECT  71.557 2.064 72.608 107.688 ;
     RECT  72.608 2.064 72.712 108.012 ;
     RECT  72.712 2.064 73.109 107.784 ;
     RECT  73.109 105.408 73.475 107.784 ;
     RECT  73.109 2.064 74.221 104.424 ;
     RECT  74.221 1.824 74.293 104.424 ;
     RECT  73.475 105.408 74.293 107.352 ;
     RECT  74.293 1.824 74.329 107.352 ;
     RECT  74.329 1.728 74.483 107.352 ;
     RECT  74.483 1.824 74.531 107.352 ;
     RECT  74.531 2.064 74.549 107.352 ;
     RECT  74.549 2.064 74.873 107.304 ;
     RECT  74.873 2.064 75.665 107.208 ;
     RECT  75.665 2.064 76.421 107.112 ;
     RECT  76.421 5.472 76.789 107.112 ;
     RECT  76.789 5.472 76.925 107.208 ;
     RECT  76.925 5.472 77.033 107.112 ;
     RECT  76.421 2.064 77.389 4.2 ;
     RECT  77.389 2.064 77.677 4.248 ;
     RECT  77.033 5.52 77.893 107.112 ;
     RECT  77.677 2.064 78.008 4.488 ;
     RECT  77.893 5.52 78.008 107.208 ;
     RECT  78.008 2.064 78.112 108.012 ;
     RECT  78.112 2.064 78.304 107.742 ;
     RECT  78.304 2.064 78.803 107.208 ;
     RECT  78.803 2.064 80.233 107.112 ;
     RECT  80.233 2.064 80.387 107.208 ;
     RECT  80.387 2.064 81.637 107.112 ;
     RECT  81.637 2.064 81.877 107.4 ;
     RECT  81.877 2.064 83.408 107.592 ;
     RECT  83.408 2.064 83.512 108.012 ;
     RECT  83.512 2.064 83.704 107.742 ;
     RECT  83.704 2.064 86.173 107.592 ;
     RECT  86.173 2.064 86.243 107.784 ;
     RECT  86.243 2.064 87.725 107.592 ;
     RECT  87.725 2.064 88.808 107.4 ;
     RECT  88.808 2.064 88.912 108.012 ;
     RECT  88.912 2.064 89.104 107.742 ;
     RECT  89.104 2.064 91.253 107.352 ;
     RECT  91.253 2.304 91.645 107.352 ;
     RECT  91.645 2.304 92.117 107.688 ;
     RECT  92.117 2.304 92.405 107.352 ;
     RECT  92.405 2.304 93.985 107.112 ;
     RECT  93.985 2.304 94.208 107.208 ;
     RECT  94.208 2.148 94.312 108.012 ;
     RECT  94.312 2.304 94.504 107.742 ;
     RECT  94.504 2.304 94.709 107.112 ;
     RECT  94.709 2.352 96.397 107.112 ;
     RECT  96.397 2.352 96.653 107.4 ;
     RECT  96.653 2.352 96.901 107.16 ;
     RECT  96.901 2.304 97.765 107.16 ;
     RECT  97.765 2.304 97.981 107.208 ;
     RECT  97.981 2.304 98.125 107.4 ;
     RECT  98.125 2.304 98.309 107.64 ;
     RECT  98.309 2.304 98.989 107.4 ;
     RECT  98.989 2.256 99.608 107.4 ;
     RECT  99.608 2.148 99.712 108.012 ;
     RECT  99.712 2.256 99.904 107.742 ;
     RECT  99.961 0.48 100.357 0.504 ;
     RECT  99.904 2.256 100.433 107.304 ;
     RECT  100.433 2.256 100.547 107.208 ;
     RECT  100.357 0.48 100.861 0.552 ;
     RECT  100.547 2.256 101.005 107.112 ;
     RECT  100.861 0.144 101.411 0.552 ;
     RECT  101.411 0.192 101.437 0.552 ;
     RECT  101.437 0.192 101.651 1.128 ;
     RECT  101.005 2.208 101.653 107.112 ;
     RECT  101.653 2.208 101.761 107.544 ;
     RECT  101.651 0.192 102.469 0.6 ;
     RECT  102.469 0.144 102.563 0.6 ;
     RECT  101.761 1.728 102.611 107.688 ;
     RECT  102.611 1.776 102.697 107.688 ;
     RECT  102.563 0.144 102.947 0.168 ;
     RECT  102.697 1.776 103.133 107.784 ;
     RECT  103.133 2.208 103.601 107.784 ;
     RECT  103.601 2.208 104.033 107.688 ;
     RECT  104.033 2.304 105.008 107.688 ;
     RECT  105.008 2.148 105.112 108.012 ;
     RECT  105.112 2.304 105.304 107.742 ;
     RECT  105.304 2.304 106.517 107.544 ;
     RECT  106.517 2.304 108.889 107.4 ;
     RECT  108.889 2.304 108.949 107.544 ;
     RECT  108.949 2.304 109.001 107.784 ;
     RECT  109.001 2.304 109.109 107.544 ;
     RECT  109.109 2.304 110.408 106.824 ;
     RECT  110.408 2.148 110.512 108.012 ;
     RECT  110.512 2.418 110.704 107.742 ;
     RECT  110.704 2.448 111.161 107.592 ;
     RECT  111.161 2.448 112.381 107.544 ;
     RECT  112.381 2.448 112.889 107.592 ;
     RECT  112.889 2.544 112.993 107.592 ;
     RECT  112.993 2.544 113.123 107.784 ;
     RECT  113.123 2.544 113.573 107.592 ;
     RECT  113.573 2.544 114.433 107.16 ;
     RECT  114.433 2.496 114.577 107.16 ;
     RECT  114.577 2.208 114.613 107.16 ;
     RECT  114.613 2.208 114.685 107.352 ;
     RECT  114.685 2.208 115.045 107.496 ;
     RECT  115.045 2.208 115.808 107.64 ;
     RECT  115.808 2.148 115.912 108.012 ;
     RECT  115.912 2.256 116.104 107.742 ;
     RECT  116.104 2.256 116.819 107.64 ;
     RECT  116.819 2.304 117.205 107.64 ;
     RECT  117.205 2.304 117.395 107.784 ;
     RECT  117.395 2.304 117.677 107.64 ;
     RECT  117.677 2.304 119.149 107.112 ;
     RECT  119.149 2.304 119.267 107.784 ;
     RECT  119.267 2.304 121.208 107.688 ;
     RECT  121.208 2.148 121.312 108.012 ;
     RECT  121.312 2.304 121.504 107.742 ;
     RECT  121.504 2.304 121.565 107.4 ;
     RECT  121.565 2.688 123.443 107.4 ;
     RECT  123.443 2.736 123.941 107.4 ;
     RECT  123.941 2.784 124.265 107.4 ;
     RECT  124.265 2.784 125.593 107.208 ;
     RECT  125.593 2.784 125.881 107.592 ;
     RECT  125.881 2.256 126.608 107.592 ;
     RECT  126.608 2.148 126.712 108.012 ;
     RECT  126.712 2.418 126.904 107.742 ;
     RECT  126.904 2.736 127.043 107.208 ;
     RECT  127.043 91.872 127.091 107.208 ;
     RECT  127.091 91.92 127.685 107.208 ;
     RECT  127.685 91.92 128.675 106.68 ;
     RECT  127.043 2.736 128.689 90.888 ;
     RECT  128.675 91.92 128.689 104.856 ;
     RECT  128.675 105.888 128.797 106.68 ;
     RECT  128.797 105.888 128.869 107.016 ;
     RECT  128.869 105.888 129.049 107.208 ;
     RECT  128.689 2.736 129.377 104.856 ;
     RECT  129.377 2.736 129.521 59.736 ;
     RECT  129.521 34.8 129.701 59.736 ;
     RECT  129.377 60.816 129.773 104.856 ;
     RECT  129.773 71.04 129.875 104.856 ;
     RECT  129.875 71.04 129.881 80.712 ;
     RECT  129.521 2.736 129.949 33.336 ;
     RECT  129.773 60.816 129.953 70.056 ;
     RECT  129.949 2.544 130.019 33.336 ;
     RECT  129.875 81.792 130.067 104.856 ;
     RECT  130.067 81.936 130.237 104.856 ;
     RECT  129.049 105.888 130.237 107.304 ;
     RECT  130.019 2.736 130.241 33.336 ;
     RECT  129.701 34.992 130.381 59.736 ;
     RECT  129.953 60.816 130.381 66.168 ;
     RECT  130.381 34.992 130.403 66.168 ;
     RECT  130.403 47.088 130.421 66.168 ;
     RECT  130.241 2.784 130.457 33.336 ;
     RECT  130.403 34.992 130.493 45.912 ;
     RECT  130.457 13.296 130.561 33.336 ;
     RECT  130.457 2.784 130.565 11.976 ;
     RECT  130.565 5.28 130.601 11.976 ;
     RECT  130.421 47.088 130.601 60.84 ;
     RECT  130.601 5.28 130.637 5.832 ;
     RECT  130.601 6.816 130.637 11.976 ;
     RECT  130.601 47.088 130.673 56.088 ;
     RECT  130.493 34.992 130.781 40.056 ;
     RECT  130.237 81.936 130.789 107.304 ;
     RECT  129.953 67.248 130.813 70.056 ;
     RECT  129.881 71.04 130.813 80.568 ;
     RECT  130.565 2.784 130.853 4.296 ;
     RECT  130.561 13.296 130.853 34.008 ;
     RECT  130.781 38.16 130.883 40.056 ;
     RECT  130.853 2.784 130.961 4.008 ;
     RECT  130.853 32.208 131.173 34.008 ;
     RECT  130.781 34.992 131.173 37.08 ;
     RECT  130.789 81.936 131.269 107.784 ;
     RECT  130.493 41.136 131.413 45.912 ;
     RECT  130.637 7.392 131.461 11.976 ;
     RECT  130.853 13.296 131.461 31.032 ;
     RECT  130.813 67.248 131.497 80.568 ;
     RECT  131.269 81.888 131.497 107.784 ;
     RECT  130.637 5.616 131.605 5.832 ;
     RECT  131.461 7.392 131.605 31.032 ;
     RECT  131.605 5.616 131.641 31.032 ;
     RECT  131.413 41.136 131.641 46.104 ;
     RECT  130.673 47.088 131.641 54.168 ;
     RECT  130.421 61.92 131.641 66.168 ;
     RECT  131.497 67.248 131.641 107.784 ;
     RECT  130.883 38.496 131.713 40.056 ;
     RECT  131.641 41.136 131.713 54.168 ;
     RECT  131.641 5.568 131.893 31.032 ;
     RECT  131.173 32.208 131.893 37.08 ;
     RECT  130.673 55.296 131.893 56.088 ;
     RECT  130.601 57.312 131.893 60.84 ;
     RECT  131.713 38.496 131.929 54.168 ;
     RECT  131.893 55.152 131.929 60.84 ;
     RECT  130.961 2.784 132.008 2.856 ;
     RECT  130.961 3.984 132.008 4.008 ;
     RECT  131.893 5.568 132.008 37.08 ;
     RECT  131.929 38.496 132.008 60.84 ;
     RECT  131.641 61.92 132.008 107.784 ;
     RECT  132.008 2.148 132.112 108.012 ;
     RECT  132.112 2.418 132.304 107.742 ;
     RECT  132.304 56.976 132.329 60.84 ;
     RECT  132.329 56.976 132.401 58.152 ;
     RECT  132.304 62.112 132.401 70.824 ;
     RECT  132.304 79.2 132.401 107.304 ;
     RECT  132.304 3.408 132.419 20.424 ;
     RECT  132.304 21.6 132.437 27.336 ;
     RECT  132.304 41.232 132.437 44.04 ;
     RECT  132.401 79.2 132.437 96.36 ;
     RECT  132.419 3.408 132.467 9.768 ;
     RECT  132.419 11.232 132.473 20.424 ;
     RECT  132.437 79.2 132.473 84.936 ;
     RECT  132.467 3.408 132.515 7.176 ;
     RECT  132.467 8.16 132.515 9.768 ;
     RECT  132.304 31.344 132.515 39.528 ;
     RECT  132.304 45.504 132.515 55.32 ;
     RECT  132.304 76.656 132.515 78.12 ;
     RECT  132.473 79.2 132.515 79.512 ;
     RECT  132.401 97.344 132.515 107.304 ;
     RECT  132.515 45.888 132.545 55.32 ;
     RECT  132.515 79.248 132.545 79.512 ;
     RECT  132.437 86.208 132.563 96.36 ;
     RECT  132.515 97.392 132.563 102.984 ;
     RECT  132.437 21.6 132.581 22.2 ;
     RECT  132.545 45.888 132.581 54.024 ;
     RECT  132.473 81.12 132.581 84.936 ;
     RECT  132.563 99.36 132.581 102.984 ;
     RECT  132.304 28.368 132.611 30.072 ;
     RECT  132.515 31.344 132.611 35.448 ;
     RECT  132.437 42.144 132.611 44.04 ;
     RECT  132.581 49.344 132.611 54.024 ;
     RECT  132.401 56.976 132.611 57.624 ;
     RECT  132.581 84.912 132.611 84.936 ;
     RECT  132.563 86.208 132.611 91.848 ;
     RECT  132.437 23.328 132.617 27.336 ;
     RECT  132.611 29.952 132.617 30.072 ;
     RECT  132.611 50.976 132.617 54.024 ;
     RECT  132.581 81.12 132.617 83.64 ;
     RECT  132.563 97.392 132.617 97.608 ;
     RECT  132.515 4.8 132.653 7.176 ;
     RECT  132.611 28.368 132.653 28.488 ;
     RECT  132.611 33.504 132.653 35.448 ;
     RECT  132.617 50.976 132.653 53.784 ;
     RECT  132.329 59.232 132.653 60.84 ;
     RECT  132.401 62.112 132.653 70.296 ;
     RECT  132.515 76.656 132.653 77.256 ;
     RECT  132.563 92.928 132.653 94.824 ;
     RECT  132.515 104.592 132.653 107.304 ;
     RECT  132.581 21.6 132.659 22.008 ;
     RECT  132.617 23.328 132.659 25.368 ;
     RECT  132.653 28.464 132.659 28.488 ;
     RECT  132.611 31.344 132.659 32.184 ;
     RECT  132.611 43.248 132.659 44.04 ;
     RECT  132.581 45.888 132.659 47.736 ;
     RECT  132.653 60.384 132.659 60.84 ;
     RECT  132.653 4.8 132.689 6.84 ;
     RECT  132.617 29.952 132.689 30.024 ;
     RECT  132.659 43.248 132.689 43.608 ;
     RECT  132.611 86.208 132.689 91.608 ;
     RECT  132.653 66.432 132.707 70.296 ;
     RECT  132.545 79.248 132.707 79.272 ;
     RECT  132.653 94.032 132.707 94.824 ;
     RECT  132.581 99.36 132.707 102.072 ;
     RECT  132.689 43.248 132.725 43.272 ;
     RECT  132.611 49.344 132.725 49.512 ;
     RECT  132.653 50.976 132.725 53.544 ;
     RECT  132.611 57.024 132.725 57.624 ;
     RECT  132.653 62.112 132.725 65.304 ;
     RECT  132.304 72.528 132.725 73.272 ;
     RECT  132.563 95.904 132.725 96.36 ;
     RECT  132.707 99.36 132.725 101.592 ;
     RECT  132.653 104.592 132.725 106.296 ;
     RECT  132.659 23.328 132.755 25.176 ;
     RECT  132.473 18.288 132.761 20.184 ;
     RECT  132.755 24.192 132.761 25.176 ;
     RECT  132.653 33.504 132.761 33.528 ;
     RECT  132.611 42.144 132.761 42.168 ;
     RECT  132.659 46.08 132.761 47.736 ;
     RECT  132.725 49.488 132.761 49.512 ;
     RECT  132.725 52.224 132.761 53.544 ;
     RECT  132.689 89.184 132.761 91.608 ;
     RECT  132.473 11.232 132.797 17.112 ;
     RECT  132.761 52.656 132.797 53.544 ;
     RECT  132.707 66.528 132.797 70.296 ;
     RECT  132.617 81.6 132.797 83.64 ;
     RECT  132.761 89.28 132.797 89.304 ;
     RECT  132.515 8.16 132.803 8.856 ;
     RECT  132.797 12.288 132.803 15.288 ;
     RECT  132.761 19.248 132.803 20.184 ;
     RECT  132.761 24.192 132.803 25.128 ;
     RECT  132.659 31.728 132.803 32.184 ;
     RECT  132.761 46.08 132.803 46.92 ;
     RECT  132.725 57.6 132.803 57.624 ;
     RECT  132.797 66.72 132.803 70.296 ;
     RECT  132.725 73.248 132.803 73.272 ;
     RECT  132.304 74.448 132.803 74.472 ;
     RECT  132.304 75.552 132.803 75.576 ;
     RECT  132.689 86.208 132.803 87.96 ;
     RECT  132.761 91.584 132.803 91.608 ;
     RECT  132.725 99.36 132.803 100.344 ;
     RECT  132.803 46.896 132.833 46.92 ;
     RECT  132.797 52.992 132.833 53.544 ;
     RECT  132.617 97.584 132.833 97.608 ;
     RECT  132.515 3.408 132.851 3.432 ;
     RECT  132.689 5.76 132.869 6.84 ;
     RECT  132.803 8.16 132.869 8.184 ;
     RECT  132.659 21.984 132.869 22.008 ;
     RECT  132.803 66.72 132.869 69.432 ;
     RECT  132.653 77.232 132.869 77.256 ;
     RECT  132.653 92.928 132.869 92.952 ;
     RECT  132.869 6.288 132.899 6.84 ;
     RECT  132.797 11.232 132.899 11.256 ;
     RECT  132.803 12.288 132.899 13.656 ;
     RECT  132.689 30 132.899 30.024 ;
     RECT  132.725 50.976 132.899 51 ;
     RECT  132.545 55.296 132.899 55.32 ;
     RECT  132.659 60.384 132.899 60.408 ;
     RECT  132.797 81.936 132.899 83.208 ;
     RECT  132.803 87.312 132.899 87.96 ;
     RECT  132.707 94.8 132.899 94.824 ;
     RECT  132.725 101.568 132.899 101.592 ;
     RECT  132.725 104.592 132.899 105.336 ;
     RECT  132.899 6.288 132.905 6.312 ;
     RECT  132.899 12.288 132.905 12.888 ;
     RECT  132.617 27.312 132.905 27.336 ;
     RECT  132.653 35.424 132.905 35.448 ;
     RECT  132.761 90.288 132.905 90.312 ;
     RECT  132.803 99.36 132.905 99.384 ;
     RECT  132.653 59.232 132.941 59.256 ;
     RECT  132.899 81.936 132.941 82.968 ;
     RECT  132.725 96.336 132.941 96.36 ;
     RECT  132.905 12.864 132.947 12.888 ;
     RECT  132.803 15.264 132.947 15.288 ;
     RECT  132.797 17.088 132.947 17.112 ;
     RECT  132.803 20.16 132.947 20.184 ;
     RECT  132.803 31.728 132.947 31.8 ;
     RECT  132.515 36.48 132.947 39.528 ;
     RECT  132.725 62.112 132.947 64.728 ;
     RECT  132.947 62.208 132.977 64.728 ;
     RECT  132.869 66.72 133.013 68.712 ;
     RECT  132.941 81.936 133.013 82.296 ;
     RECT  132.803 86.208 133.013 86.232 ;
     RECT  132.803 25.104 133.085 25.128 ;
     RECT  132.899 87.312 133.085 87.672 ;
     RECT  132.947 31.728 133.121 31.752 ;
     RECT  132.833 52.992 133.121 53.016 ;
     RECT  133.013 66.72 133.121 68.424 ;
     RECT  132.977 62.304 133.229 64.728 ;
     RECT  133.121 66.72 133.235 67.272 ;
     RECT  133.229 62.304 133.265 64.344 ;
     RECT  133.085 87.312 133.265 87.576 ;
     RECT  133.265 87.552 133.409 87.576 ;
     RECT  133.121 68.4 133.475 68.424 ;
     RECT  133.265 62.832 133.481 64.344 ;
     RECT  133.235 66.72 133.661 66.744 ;
     RECT  132.947 36.48 133.697 39.144 ;
     RECT  133.697 36.48 134.021 38.712 ;
     RECT  133.481 62.832 134.521 64.2 ;
     RECT  134.021 37.344 135.097 38.712 ;
     RECT  134.521 62.784 135.889 64.2 ;
     RECT  135.097 37.2 136.044 38.712 ;
     RECT  135.889 62.784 136.044 64.248 ;
    LAYER M5 ;
     RECT  11.856 0.016 13.368 0.037 ;
     RECT  101.328 0.016 102.84 0.133 ;
     RECT  11.856 0.037 13.464 0.277 ;
     RECT  11.856 0.277 13.656 1.763 ;
     RECT  74.448 0.016 74.52 1.763 ;
     RECT  74.496 1.763 74.52 1.859 ;
     RECT  2.4 2.137 2.52 2.151 ;
     RECT  7.8 2.137 7.92 2.151 ;
     RECT  18.6 2.137 18.72 2.151 ;
     RECT  24 2.137 24.12 2.151 ;
     RECT  29.4 2.137 29.52 2.151 ;
     RECT  34.8 2.137 34.92 2.151 ;
     RECT  40.2 2.137 40.32 2.151 ;
     RECT  45.6 2.137 45.72 2.151 ;
     RECT  51 2.137 51.12 2.151 ;
     RECT  56.4 2.137 56.52 2.151 ;
     RECT  61.8 2.137 61.92 2.151 ;
     RECT  67.2 2.137 67.32 2.151 ;
     RECT  72.6 2.137 72.72 2.151 ;
     RECT  78 2.137 78.12 2.151 ;
     RECT  83.4 2.137 83.52 2.151 ;
     RECT  88.8 2.137 88.92 2.151 ;
     RECT  94.2 2.137 94.32 2.151 ;
     RECT  99.6 2.137 99.72 2.151 ;
     RECT  105 2.137 105.12 2.151 ;
     RECT  110.4 2.137 110.52 2.151 ;
     RECT  115.8 2.137 115.92 2.151 ;
     RECT  121.2 2.137 121.32 2.151 ;
     RECT  126.6 2.137 126.72 2.151 ;
     RECT  132 2.137 132.12 2.151 ;
     RECT  101.328 0.133 102.936 2.197 ;
     RECT  115.8 2.151 116.112 2.197 ;
     RECT  18.6 2.151 18.912 2.245 ;
     RECT  40.2 2.151 40.512 2.245 ;
     RECT  51 2.151 51.312 2.245 ;
     RECT  56.4 2.151 56.712 2.245 ;
     RECT  72.6 2.151 72.912 2.245 ;
     RECT  78 2.151 78.312 2.245 ;
     RECT  88.8 2.151 89.112 2.245 ;
     RECT  115.392 2.197 116.112 2.245 ;
     RECT  126.6 2.151 126.912 2.245 ;
     RECT  99.6 2.151 99.912 2.293 ;
     RECT  115.392 2.245 116.808 2.293 ;
     RECT  94.2 2.151 94.512 2.485 ;
     RECT  107.808 2.293 107.832 2.533 ;
     RECT  24 2.151 24.312 2.581 ;
     RECT  34.8 2.151 35.112 2.677 ;
     RECT  87.168 2.245 87.192 2.677 ;
     RECT  99.6 2.293 100.008 2.677 ;
     RECT  101.04 2.197 103.752 2.677 ;
     RECT  32.064 2.245 32.088 2.723 ;
     RECT  7.8 2.151 8.112 2.725 ;
     RECT  40.2 2.245 41.496 2.725 ;
     RECT  91.152 2.245 91.176 2.725 ;
     RECT  98.736 2.677 100.008 2.725 ;
     RECT  101.04 2.677 103.944 2.725 ;
     RECT  105 2.151 105.312 2.725 ;
     RECT  29.4 2.151 29.712 2.773 ;
     RECT  33.84 2.677 35.112 2.773 ;
     RECT  77.376 2.245 78.312 2.773 ;
     RECT  118.272 2.629 118.296 2.773 ;
     RECT  2.4 2.151 2.712 2.821 ;
     RECT  28.896 2.773 30.648 2.821 ;
     RECT  33.84 2.773 35.88 2.821 ;
     RECT  40.2 2.725 42.264 2.821 ;
     RECT  49.392 2.245 49.416 2.821 ;
     RECT  50.688 2.245 51.312 2.821 ;
     RECT  53.424 2.245 53.448 2.821 ;
     RECT  83.4 2.151 83.712 2.821 ;
     RECT  93.744 2.485 94.632 2.821 ;
     RECT  95.616 2.629 95.64 2.821 ;
     RECT  98.736 2.725 103.944 2.821 ;
     RECT  105 2.725 106.056 2.821 ;
     RECT  110.4 2.151 110.712 2.821 ;
     RECT  115.392 2.293 117 2.821 ;
     RECT  118.176 2.773 118.296 2.821 ;
     RECT  123.408 2.677 123.432 2.821 ;
     RECT  132 2.151 132.312 2.821 ;
     RECT  39.456 2.821 43.896 2.867 ;
     RECT  27.312 2.677 27.336 2.869 ;
     RECT  55.728 2.245 56.712 2.915 ;
     RECT  22.272 2.053 22.296 2.917 ;
     RECT  98.736 2.821 106.056 2.965 ;
     RECT  26.88 2.869 27.336 3.013 ;
     RECT  88.704 2.245 89.112 3.013 ;
     RECT  90.576 2.725 91.176 3.013 ;
     RECT  15.6 2.821 15.624 3.061 ;
     RECT  33.36 2.821 35.88 3.107 ;
     RECT  93.744 2.821 95.64 3.107 ;
     RECT  72.384 2.245 72.912 3.109 ;
     RECT  81.888 2.821 81.912 3.109 ;
     RECT  83.4 2.821 83.976 3.109 ;
     RECT  110.4 2.821 110.808 3.157 ;
     RECT  123.264 2.821 123.432 3.157 ;
     RECT  5.952 2.677 5.976 3.205 ;
     RECT  45.6 2.151 45.912 3.205 ;
     RECT  47.952 2.821 47.976 3.205 ;
     RECT  67.2 2.151 67.512 3.205 ;
     RECT  81.888 3.109 83.976 3.205 ;
     RECT  97.056 2.917 97.08 3.205 ;
     RECT  98.16 2.965 106.056 3.205 ;
     RECT  107.472 2.533 107.832 3.205 ;
     RECT  128.832 2.821 128.856 3.205 ;
     RECT  129.984 2.533 130.008 3.205 ;
     RECT  88.704 3.013 91.176 3.251 ;
     RECT  22.272 2.917 22.824 3.301 ;
     RECT  24 2.581 25.272 3.301 ;
     RECT  61.8 2.151 62.112 3.301 ;
     RECT  67.2 3.205 67.704 3.301 ;
     RECT  70.56 3.109 70.584 3.301 ;
     RECT  71.856 3.109 72.912 3.301 ;
     RECT  98.16 3.205 107.832 3.349 ;
     RECT  109.296 2.965 109.32 3.349 ;
     RECT  121.2 2.151 121.512 3.349 ;
     RECT  22.272 3.301 25.272 3.395 ;
     RECT  4.752 2.821 4.776 3.397 ;
     RECT  5.952 3.205 6.744 3.397 ;
     RECT  10.08 2.821 10.104 3.397 ;
     RECT  12.192 1.763 13.656 3.397 ;
     RECT  15.6 3.061 16.104 3.397 ;
     RECT  17.616 2.245 18.912 3.397 ;
     RECT  20.304 2.245 20.328 3.397 ;
     RECT  22.272 3.395 22.296 3.397 ;
     RECT  26.784 3.013 27.336 3.397 ;
     RECT  58.896 2.341 58.92 3.397 ;
     RECT  61.632 3.301 62.112 3.397 ;
     RECT  63.792 2.821 63.816 3.397 ;
     RECT  65.04 2.245 65.064 3.397 ;
     RECT  66.864 3.301 67.704 3.397 ;
     RECT  70.56 3.301 72.912 3.397 ;
     RECT  81.888 3.205 84.504 3.397 ;
     RECT  90.432 3.251 91.176 3.397 ;
     RECT  96.912 3.205 97.08 3.397 ;
     RECT  98.16 3.349 109.32 3.397 ;
     RECT  131.28 2.821 132.312 3.397 ;
     RECT  12.192 3.397 14.184 3.443 ;
     RECT  28.896 2.821 32.04 3.443 ;
     RECT  86.784 2.677 87.192 3.443 ;
     RECT  15.6 3.397 18.912 3.445 ;
     RECT  20.304 3.397 21.048 3.445 ;
     RECT  113.904 3.349 113.928 3.445 ;
     RECT  113.472 3.445 113.928 3.587 ;
     RECT  128.832 3.205 130.008 3.589 ;
     RECT  131.28 3.397 132.84 3.589 ;
     RECT  26.784 3.397 27.816 3.635 ;
     RECT  4.752 3.397 6.744 3.685 ;
     RECT  7.8 2.725 8.28 3.685 ;
     RECT  23.376 3.395 25.272 3.685 ;
     RECT  37.728 2.245 37.752 3.685 ;
     RECT  69.072 2.821 69.096 3.685 ;
     RECT  70.56 3.397 73.944 3.685 ;
     RECT  2.4 2.821 2.808 3.733 ;
     RECT  9.552 3.397 10.104 3.733 ;
     RECT  42.816 2.867 43.896 3.733 ;
     RECT  77.376 2.773 78.408 3.733 ;
     RECT  79.824 2.677 79.848 3.733 ;
     RECT  115.392 2.821 118.296 3.733 ;
     RECT  128.832 3.589 132.84 3.733 ;
     RECT  81.12 3.397 84.504 3.827 ;
     RECT  55.776 2.915 56.712 3.829 ;
     RECT  76.176 2.677 76.2 3.829 ;
     RECT  58.272 3.397 58.92 3.877 ;
     RECT  59.904 3.397 59.928 3.877 ;
     RECT  61.632 3.397 62.616 3.877 ;
     RECT  63.792 3.397 67.896 3.877 ;
     RECT  75.456 3.829 76.2 3.877 ;
     RECT  77.376 3.733 79.848 3.877 ;
     RECT  81.12 3.827 81.912 3.877 ;
     RECT  83.4 3.827 84.504 3.877 ;
     RECT  92.976 3.397 93 3.877 ;
     RECT  96.912 3.397 109.32 3.877 ;
     RECT  120 2.821 120.024 3.877 ;
     RECT  121.104 3.349 121.512 3.877 ;
     RECT  123.264 3.157 124.248 3.877 ;
     RECT  125.952 2.245 126.912 3.877 ;
     RECT  12.48 3.443 14.184 3.925 ;
     RECT  27.312 3.635 27.816 3.925 ;
     RECT  37.152 3.685 37.752 3.925 ;
     RECT  45.6 3.205 46.056 3.925 ;
     RECT  47.472 3.205 47.976 3.925 ;
     RECT  88.704 3.251 89.112 3.973 ;
     RECT  86.784 3.443 87.144 4.021 ;
     RECT  90.432 3.397 91.56 4.069 ;
     RECT  92.928 3.877 93 4.069 ;
     RECT  58.272 3.877 59.928 4.213 ;
     RECT  61.392 3.877 62.616 4.213 ;
     RECT  86.592 4.021 87.144 4.213 ;
     RECT  88.272 3.973 89.112 4.213 ;
     RECT  90.432 4.069 93 4.213 ;
     RECT  37.152 3.925 38.232 4.261 ;
     RECT  39.456 2.867 41.736 4.261 ;
     RECT  42.816 3.733 43.992 4.261 ;
     RECT  88.272 4.213 93 4.261 ;
     RECT  96.624 3.877 109.32 4.261 ;
     RECT  110.304 3.157 110.808 4.261 ;
     RECT  111.84 2.629 111.864 4.261 ;
     RECT  122.496 3.877 124.248 4.261 ;
     RECT  125.664 3.877 126.912 4.261 ;
     RECT  88.272 4.261 93.144 4.355 ;
     RECT  15.6 3.445 21.048 4.453 ;
     RECT  22.128 3.397 22.296 4.453 ;
     RECT  91.536 4.355 93.144 4.499 ;
     RECT  2.4 3.733 2.856 4.501 ;
     RECT  27.312 3.925 27.912 4.501 ;
     RECT  28.896 3.443 30.936 4.501 ;
     RECT  32.016 3.443 32.04 4.501 ;
     RECT  49.392 2.821 51.312 4.501 ;
     RECT  52.32 3.925 52.344 4.501 ;
     RECT  53.328 2.821 53.64 4.501 ;
     RECT  55.776 3.829 56.904 4.501 ;
     RECT  58.272 4.213 62.616 4.501 ;
     RECT  63.792 3.877 67.992 4.501 ;
     RECT  69.072 3.685 73.944 4.501 ;
     RECT  83.4 3.877 84.744 4.501 ;
     RECT  94.2 3.107 95.64 4.501 ;
     RECT  96.624 4.261 110.808 4.501 ;
     RECT  113.904 3.587 113.928 4.501 ;
     RECT  115.392 3.733 118.824 4.501 ;
     RECT  120 3.877 121.512 4.501 ;
     RECT  122.496 4.261 126.912 4.501 ;
     RECT  128.112 3.733 132.84 4.501 ;
     RECT  83.4 4.501 84.984 4.693 ;
     RECT  86.112 4.213 87.144 4.693 ;
     RECT  63.792 4.501 73.944 4.741 ;
     RECT  75.312 3.877 76.2 4.741 ;
     RECT  9.504 3.733 10.104 4.837 ;
     RECT  11.184 3.397 11.208 4.837 ;
     RECT  12.48 3.925 14.472 4.837 ;
     RECT  45.072 3.925 46.056 4.837 ;
     RECT  47.376 3.925 47.976 4.837 ;
     RECT  113.904 4.501 114.072 4.837 ;
     RECT  115.248 4.501 118.824 4.837 ;
     RECT  23.376 3.685 26.184 4.931 ;
     RECT  45.072 4.837 46.344 4.979 ;
     RECT  92.928 4.499 93.144 4.981 ;
     RECT  94.2 4.501 110.808 4.981 ;
     RECT  92.928 4.981 110.808 5.027 ;
     RECT  63.792 4.741 76.2 5.029 ;
     RECT  77.376 3.877 81.912 5.029 ;
     RECT  83.4 4.693 87.144 5.029 ;
     RECT  120 4.501 132.84 5.075 ;
     RECT  9.504 4.837 14.472 5.077 ;
     RECT  23.568 4.931 26.184 5.077 ;
     RECT  27.312 4.501 32.808 5.077 ;
     RECT  33.84 3.107 35.88 5.077 ;
     RECT  55.776 4.501 62.616 5.077 ;
     RECT  53.328 4.501 53.688 5.125 ;
     RECT  77.376 5.029 87.144 5.317 ;
     RECT  4.752 3.685 8.28 5.365 ;
     RECT  53.328 5.125 53.736 5.365 ;
     RECT  88.272 4.355 90.456 5.365 ;
     RECT  91.536 4.499 91.56 5.365 ;
     RECT  53.328 5.365 54.168 5.461 ;
     RECT  55.248 5.077 62.616 5.461 ;
     RECT  94.08 5.027 110.808 5.557 ;
     RECT  111.84 4.261 112.488 5.557 ;
     RECT  113.904 4.837 118.824 5.557 ;
     RECT  2.4 4.501 3.624 5.653 ;
     RECT  4.752 5.365 8.52 5.653 ;
     RECT  9.504 5.077 14.616 5.653 ;
     RECT  15.6 4.453 22.296 5.653 ;
     RECT  47.376 4.837 48.312 5.653 ;
     RECT  49.392 4.501 52.344 5.653 ;
     RECT  53.328 5.461 62.616 5.653 ;
     RECT  63.696 5.029 76.2 5.653 ;
     RECT  9.504 5.653 22.296 5.747 ;
     RECT  88.272 5.365 91.56 5.893 ;
     RECT  92.928 5.027 93.048 5.893 ;
     RECT  37.152 4.261 43.992 6.181 ;
     RECT  45.072 4.979 46.056 6.181 ;
     RECT  77.376 5.317 87.192 6.181 ;
     RECT  23.568 5.077 35.88 6.229 ;
     RECT  37.152 6.181 46.056 6.229 ;
     RECT  47.376 5.653 48.36 6.229 ;
     RECT  94.08 5.557 118.824 6.229 ;
     RECT  120 5.075 130.008 6.229 ;
     RECT  23.568 6.229 46.056 6.661 ;
     RECT  47.04 6.229 48.36 6.661 ;
     RECT  2.4 5.653 8.52 6.709 ;
     RECT  9.504 5.747 22.2 6.709 ;
     RECT  23.568 6.661 48.36 6.709 ;
     RECT  88.272 5.893 93.048 6.709 ;
     RECT  94.08 6.229 130.008 6.709 ;
     RECT  88.272 6.709 130.008 6.757 ;
     RECT  131.28 5.075 132.84 6.757 ;
     RECT  2.4 6.709 48.36 6.805 ;
     RECT  77.328 6.181 87.192 6.805 ;
     RECT  88.272 6.757 132.84 6.805 ;
     RECT  49.392 5.653 76.2 7.861 ;
     RECT  77.328 6.805 132.888 7.861 ;
     RECT  2.304 6.805 48.36 9.253 ;
     RECT  49.392 7.861 132.888 9.253 ;
     RECT  2.304 9.253 132.888 9.443 ;
     RECT  2.304 9.443 48.504 11.653 ;
     RECT  49.488 9.443 132.888 11.653 ;
     RECT  2.304 11.653 132.888 12.853 ;
     RECT  2.304 12.853 132.936 19.429 ;
     RECT  2.256 19.429 132.936 20.195 ;
     RECT  2.256 20.195 132.888 21.011 ;
     RECT  2.304 21.011 132.888 31.765 ;
     RECT  2.304 31.765 132.936 37.715 ;
     RECT  2.4 37.715 132.936 39.539 ;
     RECT  2.4 39.539 132.888 40.693 ;
     RECT  0.144 51.157 0.168 52.931 ;
     RECT  0.288 53.269 0.312 53.411 ;
     RECT  2.304 40.693 132.888 54.179 ;
     RECT  128.688 54.179 132.888 55.331 ;
     RECT  2.304 54.179 127.704 55.955 ;
     RECT  2.304 55.955 127.416 56.483 ;
     RECT  38.88 56.483 127.416 56.531 ;
     RECT  2.304 56.483 37.896 56.819 ;
     RECT  4.704 56.819 37.896 57.299 ;
     RECT  2.304 56.819 3.72 57.635 ;
     RECT  38.88 56.531 127.32 57.635 ;
     RECT  128.688 55.331 132.792 57.635 ;
     RECT  38.88 57.635 121.944 57.875 ;
     RECT  6.576 57.299 37.896 58.163 ;
     RECT  38.88 57.875 98.376 58.163 ;
     RECT  99.504 57.875 121.944 58.163 ;
     RECT  128.688 57.635 132.648 58.163 ;
     RECT  123.12 57.635 127.32 58.213 ;
     RECT  123.12 58.213 127.704 58.451 ;
     RECT  11.952 58.163 37.896 58.547 ;
     RECT  21.456 58.547 37.896 58.643 ;
     RECT  21.456 58.643 22.248 58.691 ;
     RECT  4.704 57.299 5.304 58.739 ;
     RECT  6.576 58.163 10.728 58.739 ;
     RECT  23.232 58.643 37.896 58.739 ;
     RECT  70.368 58.163 98.376 58.739 ;
     RECT  99.504 58.163 111.096 58.739 ;
     RECT  2.4 57.635 3.72 58.787 ;
     RECT  21.456 58.691 22.2 58.979 ;
     RECT  23.616 58.739 37.896 58.981 ;
     RECT  38.88 58.163 69.336 58.981 ;
     RECT  99.504 58.739 110.712 59.173 ;
     RECT  123.12 58.451 127.128 59.267 ;
     RECT  10.656 58.739 10.728 59.315 ;
     RECT  23.616 58.981 69.336 59.315 ;
     RECT  99.36 59.173 110.712 59.315 ;
     RECT  112.32 58.163 121.944 59.315 ;
     RECT  123.12 59.267 127.032 59.315 ;
     RECT  11.952 58.547 20.328 59.843 ;
     RECT  24 59.315 69.336 59.845 ;
     RECT  70.368 58.739 74.856 59.845 ;
     RECT  21.456 58.979 21.768 59.939 ;
     RECT  21.648 59.939 21.768 60.131 ;
     RECT  2.4 58.787 3.288 60.133 ;
     RECT  123.12 59.315 124.248 60.275 ;
     RECT  24 59.845 74.856 60.373 ;
     RECT  75.936 58.739 98.376 60.373 ;
     RECT  99.36 59.315 108.984 60.373 ;
     RECT  110.016 59.315 110.712 60.373 ;
     RECT  129.264 58.163 132.648 60.373 ;
     RECT  4.944 58.739 5.304 60.661 ;
     RECT  10.704 59.315 10.728 60.661 ;
     RECT  11.952 59.843 15.816 60.661 ;
     RECT  24 60.373 110.808 60.661 ;
     RECT  112.32 59.315 121.896 60.661 ;
     RECT  10.704 60.661 15.816 60.803 ;
     RECT  24 60.661 121.896 60.851 ;
     RECT  17.328 59.843 20.328 60.901 ;
     RECT  4.944 60.661 5.544 60.949 ;
     RECT  6.96 58.739 9.336 60.949 ;
     RECT  10.704 60.803 10.728 60.949 ;
     RECT  21.648 60.131 21.672 60.949 ;
     RECT  112.32 60.851 121.896 60.949 ;
     RECT  123.12 60.275 124.104 60.949 ;
     RECT  125.52 59.315 126.912 60.949 ;
     RECT  11.952 60.803 15.816 61.189 ;
     RECT  17.232 60.901 20.328 61.189 ;
     RECT  2.4 60.133 3.816 61.237 ;
     RECT  4.944 60.949 5.592 61.237 ;
     RECT  24 60.851 111.24 61.237 ;
     RECT  125.52 60.949 127.272 61.237 ;
     RECT  125.52 61.237 128.136 61.333 ;
     RECT  129.264 60.373 132.888 61.333 ;
     RECT  23.904 61.237 111.24 61.523 ;
     RECT  23.904 61.523 69.48 61.717 ;
     RECT  11.952 61.189 20.328 61.765 ;
     RECT  21.552 60.949 21.672 61.765 ;
     RECT  70.464 61.523 111.24 61.811 ;
     RECT  11.952 61.765 21.672 62.005 ;
     RECT  125.52 61.333 132.888 62.101 ;
     RECT  112.32 60.949 124.104 62.197 ;
     RECT  125.52 62.101 132.936 62.197 ;
     RECT  125.472 62.197 132.936 62.243 ;
     RECT  6.96 60.949 10.728 62.341 ;
     RECT  85.92 61.811 111.24 62.581 ;
     RECT  112.32 62.197 124.344 62.581 ;
     RECT  6.96 62.341 10.968 62.677 ;
     RECT  11.952 62.005 22.536 62.677 ;
     RECT  6.96 62.677 22.536 62.725 ;
     RECT  23.52 61.717 69.48 62.725 ;
     RECT  70.464 61.811 84.648 62.773 ;
     RECT  85.92 62.581 124.344 62.773 ;
     RECT  2.4 61.237 5.592 63.205 ;
     RECT  6.96 62.725 69.48 63.205 ;
     RECT  70.464 62.773 124.344 63.205 ;
     RECT  129.264 62.243 132.936 63.205 ;
     RECT  2.4 63.205 5.88 63.301 ;
     RECT  6.96 63.205 124.344 63.301 ;
     RECT  2.4 63.301 124.344 63.493 ;
     RECT  125.472 62.243 128.04 63.493 ;
     RECT  2.4 63.493 128.04 63.589 ;
     RECT  129.072 63.205 132.984 63.589 ;
     RECT  2.4 63.589 132.984 63.733 ;
     RECT  2.4 63.733 133.224 64.067 ;
     RECT  7.2 64.067 133.224 64.165 ;
     RECT  2.4 64.067 6.216 65.509 ;
     RECT  2.304 65.509 6.216 66.661 ;
     RECT  7.2 64.165 133.464 66.661 ;
     RECT  2.304 66.661 133.464 68.099 ;
     RECT  0.192 68.197 0.312 68.387 ;
     RECT  22.416 68.099 133.464 68.435 ;
     RECT  22.416 68.435 132.936 68.723 ;
     RECT  0.288 68.387 0.312 68.771 ;
     RECT  2.304 68.099 21.432 69.061 ;
     RECT  22.416 68.723 132.888 69.061 ;
     RECT  2.304 69.061 132.888 82.261 ;
     RECT  2.256 82.261 132.888 98.099 ;
     RECT  2.304 98.099 132.888 99.635 ;
     RECT  2.304 99.635 32.472 99.779 ;
     RECT  69.12 99.635 132.888 100.739 ;
     RECT  2.304 99.779 32.424 101.603 ;
     RECT  33.504 99.635 68.136 101.603 ;
     RECT  69.12 100.739 96.888 101.747 ;
     RECT  2.304 101.603 20.664 102.131 ;
     RECT  33.504 101.603 67.992 102.611 ;
     RECT  33.504 102.611 38.712 102.659 ;
     RECT  39.696 102.611 67.992 102.659 ;
     RECT  57.984 102.659 67.992 102.901 ;
     RECT  69.12 101.747 86.28 102.901 ;
     RECT  57.984 102.901 86.28 102.997 ;
     RECT  87.264 101.747 96.888 102.997 ;
     RECT  2.4 102.131 20.664 103.235 ;
     RECT  57.984 102.997 96.888 103.235 ;
     RECT  64.896 103.235 96.888 103.237 ;
     RECT  97.872 100.739 132.888 103.237 ;
     RECT  20.64 103.235 20.664 103.285 ;
     RECT  21.936 101.603 32.424 103.285 ;
     RECT  20.64 103.285 32.424 103.571 ;
     RECT  64.896 103.237 132.888 103.619 ;
     RECT  71.664 103.619 132.888 103.715 ;
     RECT  2.4 103.235 19.368 103.763 ;
     RECT  64.896 103.619 70.68 103.763 ;
     RECT  71.664 103.715 125.448 103.763 ;
     RECT  79.968 103.763 86.28 103.811 ;
     RECT  80.16 103.811 86.28 103.859 ;
     RECT  2.4 103.763 9 104.099 ;
     RECT  39.696 102.659 56.904 104.099 ;
     RECT  69.36 103.763 70.68 104.195 ;
     RECT  20.64 103.571 20.664 104.245 ;
     RECT  39.696 104.099 56.808 104.339 ;
     RECT  71.664 103.763 78.888 104.387 ;
     RECT  71.664 104.387 78.792 104.579 ;
     RECT  64.896 103.763 68.328 104.675 ;
     RECT  80.16 103.859 86.232 104.771 ;
     RECT  21.936 103.571 32.424 104.773 ;
     RECT  126.6 103.715 132.888 104.819 ;
     RECT  2.4 104.099 5.448 104.915 ;
     RECT  21.648 104.773 32.424 104.915 ;
     RECT  33.744 102.659 38.712 104.915 ;
     RECT  41.712 104.339 56.808 104.915 ;
     RECT  87.264 103.763 125.448 104.915 ;
     RECT  103.392 104.915 125.448 104.963 ;
     RECT  41.712 104.915 49.56 105.011 ;
     RECT  103.392 104.963 105.864 105.011 ;
     RECT  106.944 104.963 125.448 105.011 ;
     RECT  20.4 104.245 20.664 105.013 ;
     RECT  21.648 104.915 26.76 105.013 ;
     RECT  4.272 104.915 5.448 105.107 ;
     RECT  114.864 105.011 125.448 105.107 ;
     RECT  20.4 105.013 26.76 105.203 ;
     RECT  49.008 105.011 49.56 105.251 ;
     RECT  92.928 104.915 96.744 105.299 ;
     RECT  20.4 105.203 20.664 105.347 ;
     RECT  130.032 104.819 132.888 105.347 ;
     RECT  6.528 104.099 9 105.349 ;
     RECT  10.224 103.763 19.368 105.349 ;
     RECT  51 104.915 56.808 105.349 ;
     RECT  6.528 105.349 19.368 105.491 ;
     RECT  21.648 105.203 26.76 105.491 ;
     RECT  27.792 104.915 32.424 105.491 ;
     RECT  39.696 104.339 40.512 105.491 ;
     RECT  41.712 105.011 47.544 105.491 ;
     RECT  51 105.349 57 105.491 ;
     RECT  57.984 103.235 63.912 105.491 ;
     RECT  71.664 104.579 75.624 105.491 ;
     RECT  80.16 104.771 84.6 105.491 ;
     RECT  85.68 104.771 86.232 105.491 ;
     RECT  87.264 104.915 91.464 105.539 ;
     RECT  106.944 105.011 110.808 105.539 ;
     RECT  111.792 105.011 113.88 105.539 ;
     RECT  93.024 105.299 96.744 105.587 ;
     RECT  21.648 105.491 26.28 105.635 ;
     RECT  33.744 104.915 37.272 105.635 ;
     RECT  94.032 105.587 96.744 105.635 ;
     RECT  4.272 105.107 5.352 105.779 ;
     RECT  7.632 105.491 19.032 105.779 ;
     RECT  111.792 105.539 113.208 105.875 ;
     RECT  81.456 105.491 84.6 105.923 ;
     RECT  7.632 105.779 8.232 106.067 ;
     RECT  9.36 105.779 19.032 106.067 ;
     RECT  23.76 105.635 26.28 106.067 ;
     RECT  27.792 105.491 31.032 106.067 ;
     RECT  53.568 105.491 54.024 106.067 ;
     RECT  55.152 105.491 57 106.067 ;
     RECT  63.648 105.491 63.768 106.067 ;
     RECT  76.608 104.579 78.792 106.067 ;
     RECT  81.456 105.923 81.912 106.067 ;
     RECT  107.472 105.539 110.808 106.067 ;
     RECT  114.864 105.107 119.592 106.067 ;
     RECT  57.984 105.491 62.232 106.115 ;
     RECT  64.896 104.675 67.992 106.115 ;
     RECT  15.6 106.067 19.032 106.163 ;
     RECT  69.36 104.195 70.488 106.163 ;
     RECT  111.792 105.875 113.112 106.163 ;
     RECT  81.552 106.067 81.912 106.211 ;
     RECT  97.872 104.915 102.312 106.259 ;
     RECT  114.864 106.067 119.256 106.259 ;
     RECT  71.712 105.491 75.624 106.403 ;
     RECT  99.456 106.259 102.312 106.403 ;
     RECT  114.864 106.259 118.104 106.403 ;
     RECT  10.656 106.067 13.992 106.451 ;
     RECT  33.744 105.635 36.792 106.451 ;
     RECT  69.36 106.163 69.48 106.451 ;
     RECT  72.336 106.403 75.624 106.451 ;
     RECT  120.576 105.107 125.448 106.451 ;
     RECT  15.6 106.163 16.248 106.547 ;
     RECT  99.456 106.403 101.832 106.547 ;
     RECT  94.032 105.635 96.504 106.595 ;
     RECT  12.096 106.451 13.992 106.643 ;
     RECT  15.6 106.547 16.152 106.643 ;
     RECT  17.424 106.163 19.032 106.643 ;
     RECT  21.648 105.635 22.776 106.643 ;
     RECT  23.76 106.067 24.312 106.643 ;
     RECT  32.352 105.491 32.424 106.643 ;
     RECT  41.712 105.491 47.496 106.643 ;
     RECT  57.984 106.115 60.408 106.643 ;
     RECT  87.648 105.539 91.464 106.643 ;
     RECT  93.024 105.587 93.048 106.643 ;
     RECT  107.472 106.067 108.984 106.643 ;
     RECT  110.304 106.067 110.808 106.643 ;
     RECT  120.576 106.451 123.816 106.643 ;
     RECT  124.8 106.451 125.448 106.643 ;
     RECT  28.32 106.067 31.032 106.691 ;
     RECT  105 105.011 105.864 106.691 ;
     RECT  126.6 104.819 129 106.691 ;
     RECT  57.984 106.643 59.832 106.787 ;
     RECT  130.032 105.347 132.504 106.835 ;
     RECT  38.688 104.915 38.712 106.837 ;
     RECT  38.592 106.837 38.712 106.883 ;
     RECT  72.336 106.451 74.328 106.883 ;
     RECT  18.048 106.643 19.032 106.979 ;
     RECT  83.232 105.923 84.6 106.979 ;
     RECT  94.032 106.595 95.448 106.979 ;
     RECT  55.68 106.067 57 107.075 ;
     RECT  2.4 104.915 3.288 107.219 ;
     RECT  4.464 105.779 5.352 107.219 ;
     RECT  6.528 105.491 6.552 107.219 ;
     RECT  9.36 106.067 9.384 107.219 ;
     RECT  10.656 106.451 11.064 107.219 ;
     RECT  13.104 106.643 13.992 107.219 ;
     RECT  15.6 106.643 15.624 107.219 ;
     RECT  18.048 106.979 18.912 107.219 ;
     RECT  20.4 105.347 20.616 107.219 ;
     RECT  22.224 106.643 22.776 107.219 ;
     RECT  28.32 106.691 28.344 107.219 ;
     RECT  29.4 106.691 31.032 107.219 ;
     RECT  32.4 106.643 32.424 107.219 ;
     RECT  33.84 106.451 36.792 107.219 ;
     RECT  41.712 106.643 41.736 107.219 ;
     RECT  44.064 106.643 44.088 107.219 ;
     RECT  45.6 106.643 47.496 107.219 ;
     RECT  49.392 105.251 49.56 107.219 ;
     RECT  51 105.491 51.768 107.219 ;
     RECT  53.568 106.067 53.592 107.219 ;
     RECT  55.68 107.075 56.712 107.219 ;
     RECT  57.984 106.787 59.352 107.219 ;
     RECT  61.68 106.115 62.232 107.219 ;
     RECT  65.232 106.115 67.992 107.219 ;
     RECT  69.456 106.451 69.48 107.219 ;
     RECT  70.464 106.163 70.488 107.219 ;
     RECT  72.6 106.883 74.328 107.219 ;
     RECT  75.6 106.451 75.624 107.219 ;
     RECT  76.8 106.067 76.824 107.219 ;
     RECT  77.904 106.067 78.792 107.219 ;
     RECT  80.352 105.491 80.376 107.219 ;
     RECT  83.4 106.979 84.6 107.219 ;
     RECT  88.08 106.643 91.08 107.219 ;
     RECT  94.032 106.979 94.512 107.219 ;
     RECT  97.872 106.259 97.896 107.219 ;
     RECT  99.456 106.547 100.536 107.219 ;
     RECT  101.808 106.547 101.832 107.219 ;
     RECT  103.392 105.011 103.992 107.219 ;
     RECT  107.472 106.643 107.496 107.219 ;
     RECT  108.816 106.643 108.984 107.219 ;
     RECT  112.368 106.163 113.112 107.219 ;
     RECT  120.576 106.643 121.512 107.219 ;
     RECT  122.784 106.643 123.816 107.219 ;
     RECT  124.8 106.643 124.824 107.219 ;
     RECT  126.6 106.691 127.656 107.219 ;
     RECT  128.976 106.691 129 107.219 ;
     RECT  130.032 106.835 132.312 107.219 ;
     RECT  7.8 106.067 8.232 107.267 ;
     RECT  57.984 107.219 58.824 107.267 ;
     RECT  88.176 107.219 89.112 107.267 ;
     RECT  96.48 106.595 96.504 107.267 ;
     RECT  121.104 107.219 121.512 107.267 ;
     RECT  57.984 107.267 58.008 107.315 ;
     RECT  110.4 106.643 110.808 107.315 ;
     RECT  12.096 106.643 12.12 107.363 ;
     RECT  22.32 107.219 22.776 107.363 ;
     RECT  105 106.691 105.72 107.363 ;
     RECT  114.864 106.403 117.384 107.363 ;
     RECT  122.784 107.219 122.808 107.363 ;
     RECT  25.632 106.067 25.656 107.411 ;
     RECT  33.84 107.219 35.544 107.411 ;
     RECT  49.536 107.219 49.56 107.411 ;
     RECT  103.68 107.219 103.704 107.507 ;
     RECT  105 107.363 105.432 107.507 ;
     RECT  114.864 107.363 116.112 107.507 ;
     RECT  85.872 105.491 86.232 107.555 ;
     RECT  81.888 106.211 81.912 107.603 ;
     RECT  10.656 107.219 10.68 107.795 ;
     RECT  20.592 107.219 20.616 107.795 ;
     RECT  22.752 107.363 22.776 107.795 ;
     RECT  30.96 107.219 30.984 107.795 ;
     RECT  33.84 107.411 35.112 107.795 ;
     RECT  36.768 107.219 36.792 107.795 ;
     RECT  38.592 106.883 38.616 107.795 ;
     RECT  39.744 105.491 40.512 107.795 ;
     RECT  45.6 107.219 46.584 107.795 ;
     RECT  63.648 106.067 63.672 107.795 ;
     RECT  65.712 107.219 65.736 107.795 ;
     RECT  72.6 107.219 73.464 107.795 ;
     RECT  86.208 107.555 86.232 107.795 ;
     RECT  108.96 107.219 108.984 107.795 ;
     RECT  113.088 107.219 113.112 107.795 ;
     RECT  117.36 107.363 117.384 107.795 ;
     RECT  119.232 106.259 119.256 107.795 ;
     RECT  130.8 107.219 130.824 107.795 ;
     RECT  51 107.219 51.576 107.843 ;
     RECT  67.2 107.219 67.752 107.891 ;
     RECT  2.4 107.219 2.712 108.009 ;
     RECT  7.8 107.267 8.112 108.009 ;
     RECT  13.2 107.219 13.512 108.009 ;
     RECT  18.6 107.219 18.912 108.009 ;
     RECT  24 106.643 24.312 108.009 ;
     RECT  29.4 107.219 29.712 108.009 ;
     RECT  34.8 107.795 35.112 108.009 ;
     RECT  40.2 107.795 40.512 108.009 ;
     RECT  45.6 107.795 45.912 108.009 ;
     RECT  51 107.843 51.312 108.009 ;
     RECT  56.4 107.219 56.712 108.009 ;
     RECT  61.8 107.219 62.112 108.009 ;
     RECT  67.2 107.891 67.512 108.009 ;
     RECT  72.6 107.795 72.912 108.009 ;
     RECT  78 107.219 78.312 108.009 ;
     RECT  83.4 107.219 83.712 108.009 ;
     RECT  88.8 107.267 89.112 108.009 ;
     RECT  94.2 107.219 94.512 108.009 ;
     RECT  99.6 107.219 99.912 108.009 ;
     RECT  105 107.507 105.312 108.009 ;
     RECT  110.4 107.315 110.712 108.009 ;
     RECT  115.8 107.507 116.112 108.009 ;
     RECT  121.2 107.267 121.512 108.009 ;
     RECT  126.6 107.219 126.912 108.009 ;
     RECT  132 107.219 132.312 108.009 ;
     RECT  2.4 108.009 2.52 108.023 ;
     RECT  7.8 108.009 7.92 108.023 ;
     RECT  13.2 108.009 13.32 108.023 ;
     RECT  18.6 108.009 18.72 108.023 ;
     RECT  24 108.009 24.12 108.023 ;
     RECT  29.4 108.009 29.52 108.023 ;
     RECT  34.8 108.009 34.92 108.023 ;
     RECT  40.2 108.009 40.32 108.023 ;
     RECT  45.6 108.009 45.72 108.023 ;
     RECT  51 108.009 51.12 108.023 ;
     RECT  56.4 108.009 56.52 108.023 ;
     RECT  61.8 108.009 61.92 108.023 ;
     RECT  67.2 108.009 67.32 108.023 ;
     RECT  72.6 108.009 72.72 108.023 ;
     RECT  78 108.009 78.12 108.023 ;
     RECT  83.4 108.009 83.52 108.023 ;
     RECT  88.8 108.009 88.92 108.023 ;
     RECT  94.2 108.009 94.32 108.023 ;
     RECT  99.6 108.009 99.72 108.023 ;
     RECT  105 108.009 105.12 108.023 ;
     RECT  110.4 108.009 110.52 108.023 ;
     RECT  115.8 108.009 115.92 108.023 ;
     RECT  121.2 108.009 121.32 108.023 ;
     RECT  126.6 108.009 126.72 108.023 ;
     RECT  132 108.009 132.12 108.023 ;
     RECT  99.912 2.151 101.328 2.197 ;
     RECT  99.912 2.197 101.04 2.293 ;
     RECT  103.752 2.197 105 2.677 ;
     RECT  18.912 2.245 20.304 3.445 ;
     RECT  49.416 2.245 50.688 2.821 ;
     RECT  87.192 2.245 88.704 3.443 ;
     RECT  100.008 2.293 101.04 2.725 ;
     RECT  94.632 2.629 95.616 2.821 ;
     RECT  110.712 2.629 111.84 2.821 ;
     RECT  117 2.629 118.272 2.773 ;
     RECT  76.2 2.677 77.376 6.181 ;
     RECT  78.312 2.677 79.824 2.773 ;
     RECT  103.944 2.677 105 2.821 ;
     RECT  32.064 2.723 32.088 2.773 ;
     RECT  89.112 2.725 90.576 3.013 ;
     RECT  106.056 2.725 107.472 3.205 ;
     RECT  30.648 2.773 32.088 2.821 ;
     RECT  78.408 2.773 79.824 3.733 ;
     RECT  117 2.773 118.176 2.821 ;
     RECT  4.776 2.821 5.952 3.397 ;
     RECT  32.04 2.821 33.36 3.107 ;
     RECT  47.976 2.821 49.392 4.837 ;
     RECT  63.816 2.821 65.04 3.397 ;
     RECT  81.912 2.821 83.4 3.109 ;
     RECT  110.808 2.821 111.84 5.557 ;
     RECT  120.024 2.821 121.2 3.349 ;
     RECT  128.856 2.821 129.984 3.205 ;
     RECT  130.008 2.821 131.28 3.589 ;
     RECT  41.736 2.867 42.816 4.261 ;
     RECT  22.824 2.917 24 3.301 ;
     RECT  95.64 2.917 97.056 3.205 ;
     RECT  97.08 2.965 98.16 3.397 ;
     RECT  107.832 2.965 109.296 3.349 ;
     RECT  109.32 2.965 110.4 3.157 ;
     RECT  25.272 3.013 26.784 3.635 ;
     RECT  16.104 3.061 17.616 3.397 ;
     RECT  32.04 3.107 33.84 4.501 ;
     RECT  93.744 3.107 94.2 3.397 ;
     RECT  69.096 3.109 70.56 3.685 ;
     RECT  70.584 3.109 71.856 3.301 ;
     RECT  109.32 3.157 110.304 4.261 ;
     RECT  6.744 3.205 7.8 3.685 ;
     RECT  46.056 3.205 47.472 3.925 ;
     RECT  67.704 3.205 69.072 3.397 ;
     RECT  95.64 3.205 96.912 3.877 ;
     RECT  89.112 3.251 90.432 4.213 ;
     RECT  113.928 3.349 115.392 4.501 ;
     RECT  120.024 3.349 121.104 3.877 ;
     RECT  22.296 3.395 23.376 4.931 ;
     RECT  8.28 3.397 9.552 3.733 ;
     RECT  10.104 3.397 11.184 4.837 ;
     RECT  11.208 3.397 12.192 3.443 ;
     RECT  14.184 3.397 15.6 3.925 ;
     RECT  21.048 3.397 22.128 4.453 ;
     RECT  27.816 3.397 28.896 3.925 ;
     RECT  58.92 3.397 59.904 3.877 ;
     RECT  62.616 3.397 63.792 5.029 ;
     RECT  67.896 3.397 69.072 3.877 ;
     RECT  79.848 3.397 81.12 3.877 ;
     RECT  91.56 3.397 92.976 3.877 ;
     RECT  93 3.397 94.2 4.261 ;
     RECT  11.208 3.443 12.48 4.837 ;
     RECT  30.936 3.443 32.016 4.501 ;
     RECT  87.144 3.443 88.704 3.973 ;
     RECT  113.472 3.587 113.904 4.261 ;
     RECT  25.272 3.635 27.312 3.685 ;
     RECT  26.184 3.685 27.312 5.077 ;
     RECT  35.88 3.685 37.152 6.229 ;
     RECT  8.28 3.733 9.504 5.365 ;
     RECT  118.824 3.733 120 6.229 ;
     RECT  126.912 3.733 128.112 4.501 ;
     RECT  81.912 3.827 83.4 5.029 ;
     RECT  56.904 3.829 58.272 4.501 ;
     RECT  73.944 3.829 75.456 3.877 ;
     RECT  59.928 3.877 61.392 4.213 ;
     RECT  67.992 3.877 69.072 4.501 ;
     RECT  73.944 3.877 75.312 4.741 ;
     RECT  91.56 3.877 92.928 4.069 ;
     RECT  95.64 3.877 96.624 4.501 ;
     RECT  121.512 3.877 122.496 4.501 ;
     RECT  124.248 3.877 125.664 4.261 ;
     RECT  14.472 3.925 15.6 5.077 ;
     RECT  27.912 3.925 28.896 4.501 ;
     RECT  38.232 3.925 39.456 4.261 ;
     RECT  43.992 3.925 45.072 6.181 ;
     RECT  46.056 3.925 47.376 4.837 ;
     RECT  51.312 3.925 52.32 4.501 ;
     RECT  52.344 3.925 53.328 5.653 ;
     RECT  87.144 3.973 88.272 5.317 ;
     RECT  84.744 4.213 86.112 4.501 ;
     RECT  93.144 4.261 94.2 4.981 ;
     RECT  112.488 4.261 113.904 5.557 ;
     RECT  90.456 4.355 91.536 5.365 ;
     RECT  91.56 4.499 92.928 5.893 ;
     RECT  3.624 4.501 4.752 5.653 ;
     RECT  32.808 4.501 33.84 5.077 ;
     RECT  84.984 4.501 86.112 4.693 ;
     RECT  114.072 4.501 115.248 4.837 ;
     RECT  46.344 4.837 47.376 4.979 ;
     RECT  48.312 4.837 49.392 5.653 ;
     RECT  22.296 4.931 23.568 5.747 ;
     RECT  46.056 4.979 47.376 6.229 ;
     RECT  93.048 5.027 94.08 6.709 ;
     RECT  62.616 5.029 63.696 5.653 ;
     RECT  130.008 5.075 131.28 6.757 ;
     RECT  14.616 5.077 15.6 5.653 ;
     RECT  53.736 5.125 55.248 5.365 ;
     RECT  87.192 5.317 88.272 6.805 ;
     RECT  8.52 5.365 9.504 6.709 ;
     RECT  54.168 5.365 55.248 5.461 ;
     RECT  48.36 5.653 49.392 9.253 ;
     RECT  22.2 5.747 23.568 6.709 ;
     RECT  76.2 6.181 77.328 7.861 ;
     RECT  46.056 6.229 47.04 6.661 ;
     RECT  48.504 9.443 49.488 11.653 ;
     RECT  127.704 54.179 128.688 55.955 ;
     RECT  127.416 55.955 128.688 56.531 ;
     RECT  37.896 56.483 38.88 58.981 ;
     RECT  127.32 56.531 128.688 58.163 ;
     RECT  3.72 56.819 4.704 58.739 ;
     RECT  5.304 57.299 6.576 58.739 ;
     RECT  121.944 57.635 123.12 59.315 ;
     RECT  98.376 57.875 99.504 59.173 ;
     RECT  10.728 58.163 11.952 60.661 ;
     RECT  69.336 58.163 70.368 59.845 ;
     RECT  111.096 58.163 112.32 58.739 ;
     RECT  127.32 58.163 127.704 58.213 ;
     RECT  20.328 58.547 21.456 59.939 ;
     RECT  22.248 58.643 23.232 58.691 ;
     RECT  22.2 58.691 23.232 58.739 ;
     RECT  3.72 58.739 4.944 58.787 ;
     RECT  9.336 58.739 10.656 59.315 ;
     RECT  22.2 58.739 23.616 58.979 ;
     RECT  74.856 58.739 75.936 60.373 ;
     RECT  3.288 58.787 4.944 60.133 ;
     RECT  98.376 59.173 99.36 60.373 ;
     RECT  9.336 59.315 10.704 60.949 ;
     RECT  108.984 59.315 110.016 60.373 ;
     RECT  121.896 59.315 123.12 60.949 ;
     RECT  124.248 59.315 125.52 60.275 ;
     RECT  15.816 59.843 17.328 60.901 ;
     RECT  20.328 59.939 21.648 60.949 ;
     RECT  3.816 60.133 4.944 61.237 ;
     RECT  124.104 60.275 125.52 62.197 ;
     RECT  110.808 60.373 112.32 60.661 ;
     RECT  5.544 60.661 6.96 60.949 ;
     RECT  10.728 60.803 11.952 62.341 ;
     RECT  111.24 60.851 112.32 62.581 ;
     RECT  15.816 60.901 17.232 61.189 ;
     RECT  5.592 60.949 6.96 63.205 ;
     RECT  20.328 60.949 21.552 61.765 ;
     RECT  128.136 61.237 129.264 61.333 ;
     RECT  69.48 61.523 70.464 63.205 ;
     RECT  84.648 61.811 85.92 62.773 ;
     RECT  22.536 62.005 23.52 62.725 ;
     RECT  124.344 62.197 125.472 63.493 ;
     RECT  128.04 62.243 129.264 63.205 ;
     RECT  10.968 62.341 11.952 62.677 ;
     RECT  5.88 63.205 6.96 63.301 ;
     RECT  128.04 63.205 129.072 63.589 ;
     RECT  6.216 64.067 7.2 66.661 ;
     RECT  21.432 68.099 22.416 69.061 ;
     RECT  32.472 99.635 33.504 99.779 ;
     RECT  68.136 99.635 69.12 101.603 ;
     RECT  32.424 99.779 33.504 102.659 ;
     RECT  96.888 100.739 97.872 103.237 ;
     RECT  20.664 101.603 21.936 103.285 ;
     RECT  67.992 101.603 69.12 102.901 ;
     RECT  86.28 101.747 87.264 102.997 ;
     RECT  38.712 102.611 39.696 105.491 ;
     RECT  32.424 102.659 33.744 106.451 ;
     RECT  56.904 102.659 57.984 104.099 ;
     RECT  19.368 103.235 20.64 104.245 ;
     RECT  63.912 103.235 64.896 105.491 ;
     RECT  20.664 103.571 21.936 104.773 ;
     RECT  70.68 103.619 71.664 104.195 ;
     RECT  125.448 103.715 126.6 106.643 ;
     RECT  9 103.763 10.224 105.349 ;
     RECT  68.328 103.763 69.36 104.675 ;
     RECT  78.888 103.763 79.968 103.811 ;
     RECT  86.28 103.763 87.264 103.859 ;
     RECT  78.888 103.811 80.16 104.387 ;
     RECT  86.232 103.859 87.264 105.539 ;
     RECT  5.448 104.099 6.528 105.107 ;
     RECT  56.808 104.099 57.984 105.349 ;
     RECT  70.488 104.195 71.664 105.491 ;
     RECT  19.368 104.245 20.4 105.491 ;
     RECT  40.512 104.339 41.712 107.219 ;
     RECT  78.792 104.387 80.16 105.491 ;
     RECT  75.624 104.579 76.608 106.067 ;
     RECT  67.992 104.675 69.36 106.451 ;
     RECT  84.6 104.771 85.68 105.491 ;
     RECT  20.664 104.773 21.648 105.013 ;
     RECT  129 104.819 130.032 107.219 ;
     RECT  3.288 104.915 4.272 105.779 ;
     RECT  26.76 104.915 27.792 105.491 ;
     RECT  37.272 104.915 38.688 105.635 ;
     RECT  49.56 104.915 51 107.411 ;
     RECT  91.464 104.915 92.928 105.299 ;
     RECT  96.744 104.915 97.872 105.635 ;
     RECT  102.312 104.915 103.392 106.403 ;
     RECT  105.864 104.963 106.944 105.539 ;
     RECT  47.544 105.011 49.008 105.251 ;
     RECT  103.992 105.011 105 107.219 ;
     RECT  110.808 105.011 111.792 106.163 ;
     RECT  113.88 105.011 114.864 105.539 ;
     RECT  5.352 105.107 6.528 107.219 ;
     RECT  119.592 105.107 120.576 106.067 ;
     RECT  20.664 105.203 21.648 105.347 ;
     RECT  20.616 105.347 21.648 106.643 ;
     RECT  57 105.349 57.984 107.075 ;
     RECT  6.552 105.491 7.632 106.067 ;
     RECT  19.032 105.491 20.4 106.979 ;
     RECT  26.28 105.491 27.792 106.067 ;
     RECT  31.032 105.491 32.352 106.643 ;
     RECT  38.712 105.491 39.744 106.883 ;
     RECT  54.024 105.491 55.152 106.067 ;
     RECT  62.232 105.491 63.648 107.219 ;
     RECT  63.768 105.491 64.896 106.067 ;
     RECT  70.488 105.491 71.712 106.403 ;
     RECT  80.376 105.491 81.456 106.067 ;
     RECT  84.6 105.491 85.872 107.219 ;
     RECT  86.232 105.539 87.648 106.643 ;
     RECT  93.048 105.587 94.032 106.643 ;
     RECT  22.776 105.635 23.76 106.643 ;
     RECT  38.592 105.635 38.688 106.837 ;
     RECT  96.504 105.635 97.872 107.219 ;
     RECT  3.288 105.779 4.464 107.219 ;
     RECT  8.232 105.779 9.36 107.219 ;
     RECT  81.912 105.923 83.232 106.979 ;
     RECT  6.552 106.067 7.8 107.219 ;
     RECT  9.384 106.067 10.656 107.219 ;
     RECT  24.312 106.067 25.632 107.411 ;
     RECT  63.672 106.067 64.896 106.115 ;
     RECT  75.624 106.067 76.8 107.219 ;
     RECT  76.824 106.067 77.904 107.219 ;
     RECT  80.376 106.067 81.552 106.211 ;
     RECT  108.984 106.067 110.304 106.643 ;
     RECT  119.256 106.067 120.576 107.219 ;
     RECT  60.408 106.115 61.68 106.643 ;
     RECT  16.248 106.163 17.424 106.547 ;
     RECT  69.48 106.163 70.464 107.219 ;
     RECT  80.376 106.211 81.888 107.219 ;
     RECT  118.104 106.259 119.232 106.403 ;
     RECT  11.064 106.451 12.096 107.219 ;
     RECT  32.424 106.451 33.84 107.219 ;
     RECT  67.992 106.451 69.456 107.219 ;
     RECT  74.328 106.451 75.6 107.219 ;
     RECT  123.816 106.451 124.8 107.219 ;
     RECT  16.152 106.547 17.424 106.643 ;
     RECT  100.536 106.547 101.808 107.219 ;
     RECT  95.448 106.595 96.48 106.979 ;
     RECT  12.12 106.643 13.104 107.219 ;
     RECT  22.776 106.643 24 107.795 ;
     RECT  31.032 106.643 32.4 107.219 ;
     RECT  44.088 106.643 45.6 107.219 ;
     RECT  107.496 106.643 108.816 107.219 ;
     RECT  108.984 106.643 110.4 107.795 ;
     RECT  121.512 106.643 122.784 107.363 ;
     RECT  28.344 106.691 29.4 107.219 ;
     RECT  127.656 106.691 128.976 107.219 ;
     RECT  38.616 106.883 39.744 107.795 ;
     RECT  18.912 106.979 20.4 107.219 ;
     RECT  81.912 106.979 83.4 107.603 ;
     RECT  56.712 107.075 57.984 107.315 ;
     RECT  10.68 107.219 12.096 107.363 ;
     RECT  12.12 107.219 13.2 107.363 ;
     RECT  29.712 107.219 30.96 107.795 ;
     RECT  35.544 107.219 36.768 107.411 ;
     RECT  65.736 107.219 67.2 107.795 ;
     RECT  103.704 107.219 105 107.507 ;
     RECT  130.824 107.219 132 107.795 ;
     RECT  116.112 107.363 117.36 107.795 ;
  END
END ot_hgi_sfu_ctl60lo
END LIBRARY
